FUNCTION "fc_515D_RecData" : VOID
TITLE =TYP GENERATOR  -select received MPI signals-
//version!date    !author !change_segm!change_description
//-------+--------+-------+-----------+-------------------------------
// 1.3   !23.05.00!Kahle  ! ---       ! last valid version
// 1.4   !11.08.00!Kahle  ! 1         ! new rec.data (DB101...124/DBB54)
// 1.5   !17.10.00!Kahle  ! 1         ! Rec.DBB124 change "IN_release"
// 1.6   !20.10.00!Kahle  ! 1         ! Rec dbx108.3 allways from actual config.
// 1.7   !10.11.00!Kahle  ! 2(new)    ! Option: commands supervision system
// 1.8   !11.11.00!Kahle  ! 2         ! Corr. call option
//       !        !       !           ! new rec.data (DB101...124/DBB55)
//       !        !       ! 1         ! Change mask DBX108.2 f_brk_clse
// 1.9   !08.12.00!Kahle  ! 1         ! new rec.date (DB105...124/DBB56)
AUTHOR : Kahle
FAMILY : PMA71
NAME : RecData
VERSION : 1.9


VAR_INPUT
  GENERATOR : BOOL ;
  IN_emergCond : BOOL ;	//Generator =Emergency generator
END_VAR
VAR_TEMP
  total_config11 : DWORD ;	//total configuration config11 (20bit long)
  total_configByte8 : DWORD ;	//total configuration byte8 only (20bit long)
  total_configPreSelect : DWORD ;	//total configuration pre select (20bit long)
  total_configAct : DWORD ;	//total actual configuration (20bit long)
  actCfg_byte8 : WORD ;	//actual configuration for received byte no.8
  cfg_preSelect : WORD ;	//bus configuration for preselection
  mpi_rcv_1 : BYTE ;	//temporary MPI receive Byte1 part1
  mpi_rcv_2 : BYTE ;	//temporary MPI receive Byte3 part2
  mpi_rcv_3 : BYTE ;	//temporary MPI receive Byte3 part3
  mpi_rcv_4 : BYTE ;	//temporary MPI receive Byte3 part4
  mpi_rcv_5 : BYTE ;	//temporary MPI receive Byte8 part1
  mpi_rcv_6 : BYTE ;	//temporary MPI receive Byte8 part2
  fdb_UBLunit : DINT ;	//temporary UBL unit
  equal_UBLunit : BOOL ;	//temporary equal flag UBL
END_VAR
BEGIN
NETWORK
TITLE =Select MPI signals
//Select MPI signals
//load cfg11
//
//1/1 bus configuration
      L     "prm_pma".p_cfg11; // 1/1 bus configuration (cfg11)
      L     "prm_pma".p_tiebrkCfg; //Tie breaker configuration
      CALL "fc_h17_20bitCfg" ;
      T     #total_config11;

//especial byte 8 configuration
      L     "prm_pma".p_cfg11; //configuration in case of EG
      U     #IN_emergCond;
      SPB   EG8B;
      L     "MEM".o51_actCfg; //standard configuration
EG8B: T     #actCfg_byte8;
      L     "prm_pma".p_tiebrkCfg; //Tie breaker configuration
      CALL "fc_h17_20bitCfg" ;
      T     #total_configByte8;

//PreSelect configuration
      L     "prm_pma".p_cfg11;
      L     "prm_pma".p_cfgUness;
      INVI  ;
      UW    ;
      L     2#1111111111111;
      UW    ;
      T     #cfg_preSelect; // 1/1 bus configuration without unessential stations, shore connection1&2,EG
      L     0; //Tie breaker configuration not used!
      CALL "fc_h17_20bitCfg" ;
      T     #total_configPreSelect;

//actual configuration
      L     "MEM".o51_actCfg; //only actual configuration
      L     "prm_pma".p_tiebrkCfg; //Tie breaker configuration
      CALL "fc_h17_20bitCfg" ;
      T     #total_configAct;

//Received commands from Gen 1 -13, EG, TieBrk 1-4, Shore1,2 (I_Gen1_SR ..13SR,I_tie1_SR ..4SR,I_Shr1SR..2SR  D30.0 -D 30.7) <OR>
      CALL "fc_95_fdbHndl" (
           IN_off                   := B#16#0,
           IN_mask                  := B#16#0,//bit0 -7: OR
           IN_release               := #total_config11,
           OUT_fdb                  := DB99.DBB  106);//received MPI commands (byte 0)

//Received commands from Gen 1 -13, EG, TieBrk 1-4, Shore1,2 (D31.0 -D 31.7) <OR>
      CALL "fc_95_fdbHndl" (
           IN_off                   := B#16#1,
           IN_mask                  := B#16#0,//bit0 -7: OR
           IN_release               := #total_config11,
           OUT_fdb                  := #mpi_rcv_1);//received MPI commands (byte 1, without bit1))

//no evaluation I_Gen1_SR ..13SR,I_tie1_SR ..4SR,I_Shr1SR..2SR  D31.1 "simultaneous lock" ->FC117 "simultanLock Handler
//              I_Gen1_SR ..13SR,I_tie1_SR ..4SR,I_Shr1SR..2SR  D31.6 "pre select lock" ->only single signal!
      L     #mpi_rcv_1;
      L     B#16#FD;
      UW    ;
      T     DB99.DBB  107; //received MPI commands (byte 1, bit x.0, x.2 -x.7)

//Received commands from Gen 1 -13, EG, TieBrk 1-4, Shore1,2 (D38.2, D 38.6) <OR>
      CALL "fc_95_fdbHndl" (
           IN_off                   := B#16#8,
           IN_mask                  := B#16#32,//bit1,4-5:AND ; bit0,2,3,6,7: OR
           IN_release               := #total_configByte8,
           OUT_fdb                  := #mpi_rcv_5);//received MPI commands (byte 8)
      L     #mpi_rcv_5;
      L     B#16#F3; //released bit 0,1,4,5,6,7
      UW    ;
      T     #mpi_rcv_5;

//Received commands from Gen 1 -13, EG, TieBrk 1-4, Shore1,2 (D38.2, D 38.6) <OR>
      CALL "fc_95_fdbHndl" (
           IN_off                   := B#16#8,
           IN_mask                  := B#16#32,//bit1,4-5:AND ; bit0,2,3,6,7: OR
           IN_release               := #total_configAct,
           OUT_fdb                  := #mpi_rcv_6);//received MPI commands (byte 8)
      L     #mpi_rcv_6;
      L     B#16#C; //released bit 2,3
      UW    ;
      L     #mpi_rcv_5;
      OW    ;
      T     DB99.DBB  108;

//Received commands from Gen 1 -13, EG, TieBrk 1-4, Shore1,2 (D39.3 -D 39.4) <AND>
      CALL "fc_95_fdbHndl" (
           IN_off                   := B#16#9,
           IN_mask                  := B#16#0,//bit0 -7: OR
           IN_release               := #total_config11,
           OUT_fdb                  := #mpi_rcv_2);//received MPI commands (byte 9)
      L     #mpi_rcv_2;
      L     B#16#18;
      UW    ;
      T     #mpi_rcv_2; //received MPI commands (byte 9, bit3, 4)

//Received commands from Gen 1 -13, EG, TieBrk 1-4, Shore1,2 (D39.2, D39.5 -D 39.7) <OR>
      CALL "fc_95_fdbHndl" (
           IN_off                   := B#16#9,
           IN_mask                  := B#16#0,// bit0 -7: OR
           IN_release               := #total_configAct,
           OUT_fdb                  := #mpi_rcv_3);//received MPI commands (byte 9)
      L     #mpi_rcv_3;
      L     B#16#E4;
      UW    ;
      T     #mpi_rcv_3; //received MPI commands (byte 9, bit2, 5 -7 )

//Received commands from Gen 1 -13, EG, TieBrk 1-4, Shore1,2 (D39.1) <AND>
      CALL "fc_95_fdbHndl" (
           IN_off                   := B#16#9,
           IN_mask                  := B#16#FF,//bit0 -7: AND
           IN_release               := #total_configPreSelect,// 1/1 bus configuration without unessential stations
           OUT_fdb                  := #mpi_rcv_4);//received MPI commands (byte 9)
      L     #mpi_rcv_4;
      L     B#16#2;
      UW    ;
      L     #mpi_rcv_2;
      OW    ;
      L     #mpi_rcv_3;
      OW    ;
      T     DB99.DBB  109; //received MPI commands (byte 9)

//Received commands from Gen 1 -13, EG, TieBrk 1-4, Shore1,2 (I_Gen1_SR ..13SR,I_tie1_SR ..4SR,I_Shr1SR..2SR  D40.0 -D 40.7) <OR>
      CALL "fc_95_fdbHndl" (
           IN_off                   := B#16#A,
           IN_mask                  := B#16#0,//bit0 -7: OR
           IN_release               := #total_configAct,//only actual configuration
           OUT_fdb                  := DB99.DBB  110);//received MPI commands (byte 4)


//Received commands from Gen 1 -13, EG, TieBrk 1-4, Shore1,2 (I_Gen1_SR ..13SR,I_tie1_SR ..4SR,I_Shr1SR..2SR  D41.0 -D 41.7) <OR>
      CALL "fc_95_fdbHndl" (
           IN_off                   := B#16#B,
           IN_mask                  := B#16#0,//bit0 -7: OR
           IN_release               := #total_config11,//1/1 bus configuration
           OUT_fdb                  := DB99.DBB  111);//received MPI commands (byte 5)


//Received commands from Gen 1 -13, EG, TieBrk 1-4, Shore1,2 (I_Gen1_SR ..13SR,I_tie1_SR ..4SR,I_Shr1SR..2SR  D54.0 -D 54.7) <OR>
      CALL "fc_95_fdbHndl" (
           IN_off                   := B#16#18,//24(d)
           IN_mask                  := B#16#0,//bit0 -7: OR
           IN_release               := #total_configAct,//only actual configuration
           OUT_fdb                  := DB99.DBB  124);//received MPI commands (especially up/down commands)

//Received commands from Gen 1 -13, EG, TieBrk 1-4, Shore1,2 (I_Gen1_SR ..13SR,I_tie1_SR ..4SR,I_Shr1SR..2SR  D55.0 -D 55.7) <OR>
      CALL "fc_95_fdbHndl" (
           IN_off                   := B#16#19,//25(d)
           IN_mask                  := B#16#0,//bit0 -7: OR
           IN_release               := #total_configAct,//only actual configuration
           OUT_fdb                  := DB99.DBB  125);//received MPI commands (especially up/down commands)

//Received commands from Gen 1 -13, EG, TieBrk 1-4, Shore1,2 (I_Gen1_SR ..13SR,I_tie1_SR ..4SR,I_Shr1SR..2SR  D56.0 -D 56.7) <OR>
      CALL "fc_95_fdbHndl" (
           IN_off                   := B#16#1A,//26(d)
           IN_mask                  := B#16#0,//bit0 -7: OR
           IN_release               := #total_config11,//only actual configuration
           OUT_fdb                  := DB99.DBB  126);//received MPI commands (especially up/down commands)

NETWORK
TITLE =Option: commands from the supervision system

      CALL "fb_opt_SVcmd" , "Options" ;

END_FUNCTION



FUNCTION "fb_515C_SendData" : VOID
TITLE =Collect the MPI Send signals especial Diesel generator
//version!date    !author !change_segm!change_description
//-------+--------+-------+-----------+-------------------------------
// 1.0   !12.11.99!Kahle  ! ---       ! 1st. valid version
// 1.1   !20.10.00!Kahle  ! 1         ! DBX86.0 f_EG_busbar
//       !        !       ! 1         ! del."I_MMI_SR".i_GenBrkClse->FB40
// 1.2   !26.01.01!Kahle  ! 1         ! corr.signal "on busbar in automatic"
AUTHOR : Kahle
FAMILY : PMA71
NAME : CollData
VERSION : 1.2


VAR_INPUT
  GENERATOR : BOOL ;
  IN_Mde_autoOP : BOOL ;	//mode =automatic from OP
END_VAR
VAR_OUTPUT
  IN_Mde_auto : BOOL ;	//mode =automatic from IMAC
END_VAR
VAR_TEMP
  local : BOOL ;	//mode =local
  semiOP : BOOL ;	//mode =semi OP
  autoOP : BOOL ;	//mode =auto OP
  semi : BOOL ;	//mode =semi
  auto : BOOL ;	//mode =auto
  var5 : BOOL ;
  var6 : BOOL ;
  var7 : BOOL ;
END_VAR
BEGIN
NETWORK
TITLE =Collect the MPI Send signals
// c_genBrkOpn, c_unitLock                            ->FB56 "GenProtect"
//
// c_simlLock                                         ->FC117 "SimultLockHandler"
//
// c_UBL_on, c_shoreMode, c_life, f_UBL_unit,         -> +++Baustelle+++
// UBLminU, f_UBL_on, f_shoreMode, f_actUBL,
// f_actMin, a_UBLunit
//
// c_preSeLock, f_preSeLock, f_busy_Gset              ->FC44 "Order Change", FC43
//"preSeLock"
//
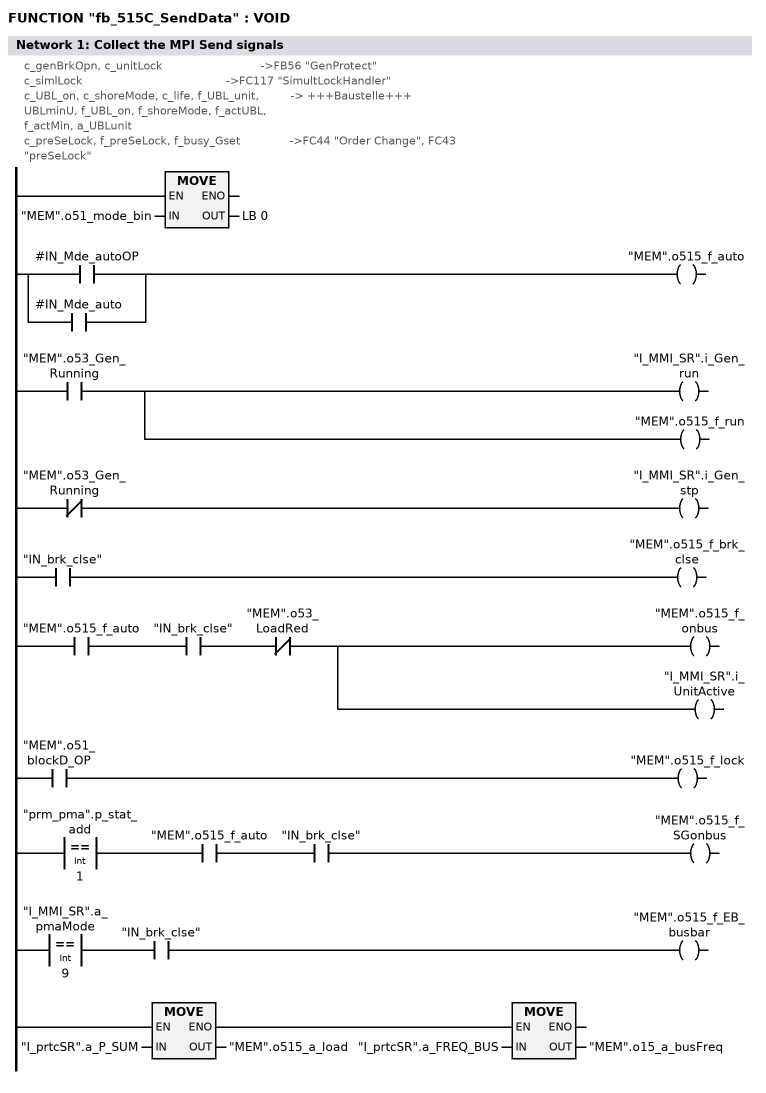
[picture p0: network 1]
      NOP   0;
//c_reqStrt, c_req2Start, c_reqEStart, c_req2EStart  ->FC60,FC61 "DG, SG"
//     O     "MEM".o511_req_Ustrt
//      O     "MEM".o512_req_Ustrt
//      =     "MEM".o515_c_reqStrt

//      O     "MEM".o511_req_Ustrt2
//      =     "MEM".o515_c_req2Strt

//      mode =automatic
      L     "MEM".o51_mode_bin;
      T     LB     0;
      O     #IN_Mde_autoOP;
      O     #IN_Mde_auto;
      =     "MEM".o515_f_auto;

// ready for standby   -->FC60/Segm 34

//Diesel/Shaftgenerator running
      U     "MEM".o53_Gen_Running;
      =     "I_MMI_SR".i_Gen_run;
      =     "MEM".o515_f_run;

//Diesel/Shaftgenerator stopped
      UN    "MEM".o53_Gen_Running;
      =     "I_MMI_SR".i_Gen_stp;

// generator breaker close
      U     "IN_brk_clse";
      =     "MEM".o515_f_brk_clse;

// f_onbus
      U     "MEM".o515_f_auto;
      U     "IN_brk_clse";
      UN    "MEM".o53_LoadRed;
      =     "MEM".o515_f_onbus;
      =     "I_MMI_SR".i_UnitActive;

// generator set blocked
      O     "MEM".o51_blockD_OP;
//                                                    ++++ FB56 "GenProtect" ++++
      =     "MEM".o515_f_lock;

// shaft generator set on busbar
      U(    ;
      L     "prm_pma".p_stat_add;
      L     1;
      ==I   ;
      )     ;
      U     "MEM".o515_f_auto;
      U     "IN_brk_clse";
      =     "MEM".o515_f_SGonbus;

// Diesel is running as emergency diesel on busbar
      U(    ;
      L     "I_MMI_SR".a_pmaMode;
      L     9; //mode =dynamic emergency mode
      ==I   ;
      )     ;
      U     "IN_brk_clse";
      =     "MEM".o515_f_EB_busbar;

// actual active load signal
      L     "I_prtcSR".a_P_SUM;
      T     "MEM".o515_a_load;

// order sequence start/stop                       ->FB44 "Order change"

// actual busbar frequency
      L     "I_prtcSR".a_FREQ_BUS;
      T     "MEM".o15_a_busFreq;

END_FUNCTION




FUNCTION "fc_917_minMax" : VOID
TITLE =Select the highest or lowest value
//The select typ is predefined by the selector switch.
//
//The following selections are possible:
//
//1.: the highest value of In_1, In_2, In_3
//2.: 1st step: the highest value of In_1 and In_2. From this result and In_3 the
//    lowest value.
//3.: the lowest value of In_1, In_2, In_3
//4.: 1st step: the lowest value of In_1 and In_2. From this result and In_3 the
//    highest value.
AUTHOR : Kahle
FAMILY : PMA71
NAME : Minmax
VERSION : 1.0


VAR_INPUT
  Selector : INT ;	//Selection type(1:HHH/2:HHL/3:LLL/4:LLH)
  In_1 : INT ;	//value 1
  In_2 : INT ;	//value 2
  In_3 : INT ;	//value 3
END_VAR
VAR_OUTPUT
  RetVal : INT ;	//return value
END_VAR
BEGIN
NETWORK
TITLE =Select the actual type

      L     #Selector;
      +     -1;
      SPL   fail;
      SPA   HHH;
      SPA   HHL;
      SPA   LLL;
      SPA   LLH;

fail: BEA   ; //in case of a wrong selctor value end of program
NETWORK
TITLE =Type: select the highest value

HHH:  L     #In_1;
      L     #In_2;
      >I    ;
      SPB   C_1; //In_1 > In_2 ?

//In_2 >In_1
      L     #In_2;
      L     #In_3;
      >I    ;
      SPBN  O_1; //In_2 > In_3 ?
      L     #In_2;
O_1:  T     #RetVal;
      BEA   ;

//In_1 >In_2
C_1:  L     #In_3;
      L     #In_1;
      >I    ;
      SPBN  O_1; //In_1 > In_3 ?
      L     #In_3;
      SPA   O_1;

NETWORK
TITLE =

HHL:  L     #In_1;
      L     #In_2;
      >I    ;
      SPB   C_2; //In_1 > In_2 ?

//In_2 >In_1
      L     #In_2;
      L     #In_3;
      <I    ;
      SPBN  O_2; //In_2 < In_3 ?
      L     #In_2;
O_2:  T     #RetVal;
      BEA   ;

//In_1 >In_2
C_2:  L     #In_3;
      L     #In_1;
      <I    ;
      SPBN  O_2; //In_1 < In_3 ?
      L     #In_3;
      SPA   O_2;

NETWORK
TITLE =

LLL:  L     #In_1;
      L     #In_2;
      <I    ;
      SPB   C_3; //In_1 < In_2 ?

//In_1 >In_2
      L     #In_2;
      L     #In_3;
      <I    ;
      SPBN  O_3; //In_2 < In_3 ?
      L     #In_2;
O_3:  T     #RetVal;
      BEA   ;

//In_1 <In_2
C_3:  L     #In_3;
      L     #In_1;
      <I    ;
      SPBN  O_1; //In_1 < In_3 ?
      L     #In_3;
      SPA   O_3;

NETWORK
TITLE =

LLH:  L     #In_1;
      L     #In_2;
      <I    ;
      SPB   C_4; //In_1 < In_2 ?

//In_1 >In_2
      L     #In_2;
      L     #In_3;
      >I    ;
      SPBN  O_4; //In_2 > In_3 ?
      L     #In_2;
O_4:  T     #RetVal;
      BEA   ;

//In_1 <In_2
C_4:  L     #In_3;
      L     #In_1;
      >I    ;
      SPBN  O_4; //In_1 > In_3 ?
      L     #In_3;
      SPA   O_4;

END_FUNCTION

FUNCTION_BLOCK "fb_59_GenSet"
TITLE =Start Unit
//version!date    !author !change_segm!change_description
//-------+--------+-------+-----------+-------------------------------
// 1.1   !28.02.00!Kahle  ! ---       ! last valid version
// 1.2   !15.11.00!Kahle  ! 11        ! no load sharing if semiIMAC (selectable)
// 1.3   !05.01.01!Kahle  ! 11        ! ext.lock L/F-controller
//
//
//
//  FUNKTION:
//  Es werden jeweils nur die Start-Kommandos der jeweiligen aktiven Betriebsart
//akzeptiert.
//
//  Start Kommandos 'Semi-Autom'
//  - Bedienerstart GenSch schliessen
//  Start Kommandos 'Autom'
//  - Bediener Start-Kommando
//  - Bediener Alarmstart-Kommando
//  - Aggregat anfordern
//  - 2. Aggregat anfordern
//  - Aggregat Alarmanforderung
//  - 2. Aggregat Alarmanforderung
//  Freigabe Kriterien
//  - Aggregat nicht am Netz
//  - Diesel verfügbar
//  - kein Notstopp Dieselschutz
//  - GenSch verfügbar
//  - Generatorschutz- u. Synchroniserung verfügbar
//
//  In der Start-Sequenz werden folgende Schritte ausgeführt:
//  - Diesel Start
//  - GenSch schliessen
//  - Lastverteilung
//
//  Bei bereits erfüllten Bedingungen wird der entspechende Schritt übersprungen
//(z.B. bei einem //  von Hand gestartetem Diesel geht die Startsequenz
//automatisch zum nächsten Schritt über).
//  Beim Kommando 'GenSch schliessen' wird der 1.Schritt (Dieselstart)
//übersprungen. Sobald die //  Freigabebedingungen für das Schliessen des GenSch
//erfüllt sind, wird das Kommando akzeptiert.
//  Es werden folgende Schritte ausgeführt:
//  - GenSch schliessen
//  - Lastverteilung
//
//  Beim Auftritt eines Fehlers innerhalb der Startsequenz wird ein neues
//Aggregat angefordert, //  sofern es ein Startkommando 'Automatik' war. Bei
//Startkommando 'Manuell' wird nur eine
// Fehlermeldung abgesetzt.
//  Siemens AG ATD IS3T, Kahle +494028892022, jens.kahle@hbg.siemens.de
//  PMA71
//  = Start Unit
//  Datum aktuelle Version: 09.02.99
//  Version, Datum,   Bearbeiter, geänderte Variablen
//   01.01,  09.02.99,  Kahle   , Ersterstellung
//
//KNOW_HOW_PROTECT
// (If specified, no more changes can be made once the block is generated)
//UNLINKED
// (If specified, the generated block is only available in the PLC load
//  memory)
//READ_ONLY
// (If specified, the generated block cannot be changed in the programmable
//  controller)
AUTHOR : Bauch
FAMILY : PMA71
NAME : StrtUnit
VERSION : 1.3


VAR_INPUT
  in_act_mode : BYTE ;	//Active operation mode
  in_Set_Avail : BOOL ;	//Generator set available for start
  in_PB_Start : BOOL ;	//Command from PB "Start" (in semi from OP/MMI or in local from local PB)
  in_PB_Stop : BOOL ;	//Command from PB "Stop" (in semi from OP/MMI or in local from local PB)
  in_PB_GB_Open : BOOL ;	//Command from PB "GB open" (in semi mode from OP/MMI)
  in_PB_Start_Auto : BOOL ;	//Command from PB "Start Generatorset" incl.Loadsharng (in auto mode)
  in_PB_Stop_Auto : BOOL ;	//Command from PB "Stop Generatorset" incl.Loadsharing (in auto mode)
  in_PB_StopRelease : BOOL ;	//Release for stop command in automatic mode
  in_Standby_Start : BOOL ;	//Standby start command (only in Automatic mode)
  in_Standby_Release : BOOL ;	//Release of standby start (this set as standby set)
  in_Standby_Start2 : BOOL ;	//2nd standby start command (only in Automatic mode)
  in_Standby_Release2 : BOOL ;	//Release of  2nd standby start (this set as standby set)
  in_Stop_Auto : BOOL ;	//Stop command in automatic mode
  in_DI_FB_GenBrk_On : BOOL ;	//Feedback signal Generator breaker is ON
  in_DI_FB_GenBrk_Off : BOOL ;	//Feedback signal Generator breaker is OFF
  in_DI_FireSpeed : BOOL ;	//Ignition speed
  in_GenVolt : BOOL ;	//Generator voltage available (>85%)
  in_lockCtrl : BOOL ;	//lock load/frequency controller
  in_reset : BOOL ;	//Reset failure memory
END_VAR
VAR_OUTPUT
  out_Start_Comm : BOOL ;	//Start command to own set (Pulse)
  out_Stop_Comm : BOOL ;	//Stop command to own set (Pulse)
  out_StopAuto : BOOL ;	//Auto stop command (deloading, GBoff, DG stop)
  out_GenBrk_Off : BOOL ;	//Command "OFF" to generator breaker (Pulse)
  out_LoadBal_On : BOOL ;	//Command "Load balancing ON" (Pulse)
  out_fail_noStopPos : BOOL ;	//In automatic mode no stop permitted
END_VAR
VAR
  stat_Automatic : BOOL ;	//Automatic mode
  stat_Auto_PAux : BOOL ;	//Auxiliary (pulse) flag for automatic mode
  stat_Auto_Pulse : BOOL ;	//Automatic mode (pulse)
  stat_Start_Auto_PAux : BOOL ;	//Auxiliary (pulse) flag for start in auto mode
  stat_Start_Semi_PAux : BOOL ;	//Auxiliary (pulse) flag for start in semi auto mode
  stat_Start_Auto_PB : BOOL ;	//Auxiliary (pulse) flag for PB "Start" in auto mode
  stat_Stop_Auto_PAux : BOOL ;	//Auxiliary (pulse) flag for stop in auto mode
  stat_Stop_Semi_PAux : BOOL ;	//Auxiliary (pulse) flag for stop in semi auto mode
  stat_Stop_Auto_PB : BOOL ;	//Auxiliary (pulse) flag for PB "Stop" in auto mode
  stat_GBOn_Semi_PAux : BOOL ;	//Auxiliary (pulse) flag for gen. breaker closing in semi auto mode
  stat_BrkOff_Semi_PAux : BOOL ;	//Auxiliary (pulse) flag for generator breaker Off command in semi auto mode
  stat_LoadBal_Auto_PAux : BOOL ;	//Auxiliary (pulse) flag for "Load balance mode" On command in auto mode
  stat_LoadBal_Semi_PAux : BOOL ;	//Auxiliary (pulse) flag for "Load balance mode" On command in semi auto mode
  stat_StpNoPos : BOOL ;	//Stop gen.set not possible
END_VAR
VAR_TEMP
  temp_OM_Local : BOOL ;	//Active operation mode: Local
  temp_OM_Semi_OP : BOOL ;	//Active operation mode: Semi automatic OP
  temp_OM_Auto_OP : BOOL ;	//Active operation mode: Auto OP
  temp_OM_Semi_MMI : BOOL ;	//Active operation mode: Semi automatic MMI
  temp_OM_Auto_MMI : BOOL ;	//Active operation mode: Auto MMI
  temp_Reserve_005 : BOOL ;	//Reserved (Transfer Byte --> Bit)
  temp_Reserve_006 : BOOL ;	//Reserved (Transfer Byte --> Bit)
  temp_Reserve_007 : BOOL ;	//Reserved (Transfer Byte --> Bit)
  temp_Auto : BOOL ;	//Active operation mode: Auto
  temp_Semi : BOOL ;	//Active operation mode: Semi automatic
  temp_ScratchFlag : BOOL ;	//Scratch flag
  in_Genop_noFail : BOOL ;	//	no failure at Genop
  in_loadsharing_ok : BOOL ;	//	feedback loadsharing in normal range
  temp_PB_autoStop : BOOL ;	//Stop generator set in automatic mode
  temp_preCondPBstp : BOOL ;	//Preconditions for stop via pushbutton
END_VAR
BEGIN
NETWORK
TITLE =Active operation mode (Transfer Byte --> Bit)
//This transfer function is relaying on the relative addresses of the "temp"
//variables "temp_OM_Local" ... "temp_OM_Auto" in the area from 0.0 ... 0.7.
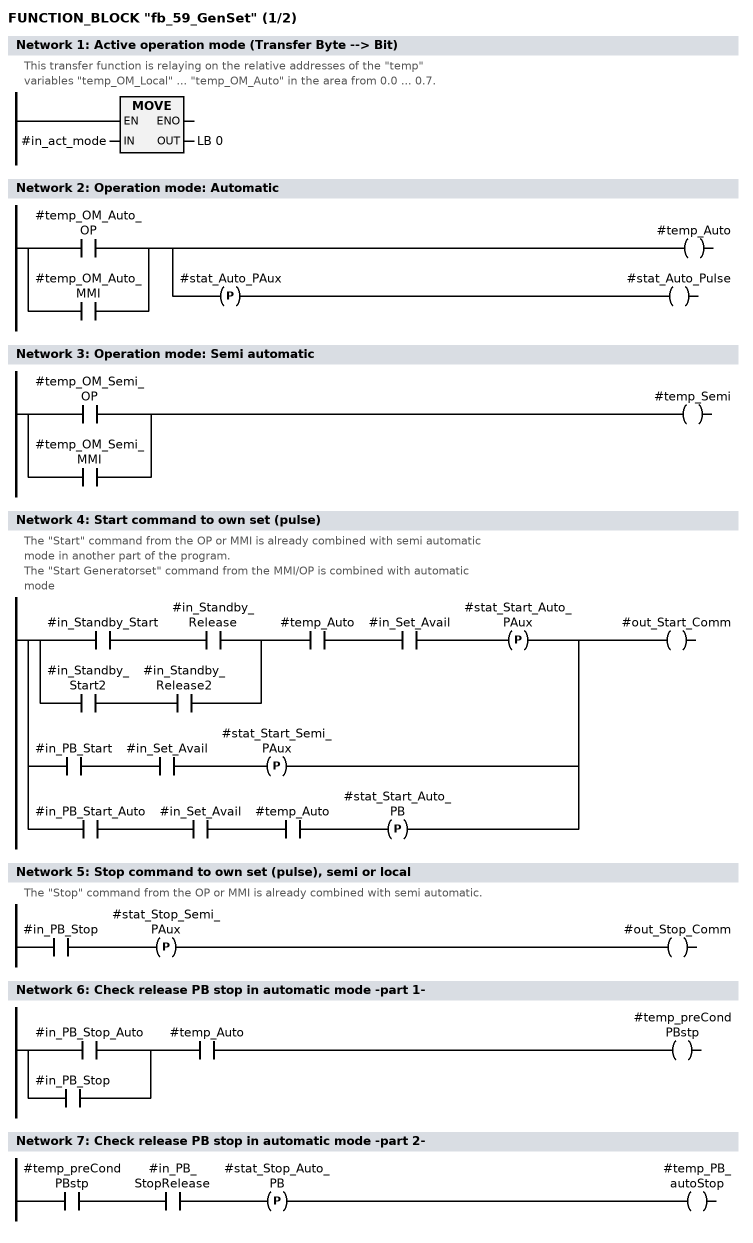
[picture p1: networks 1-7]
      L     #in_act_mode;
      T     LB     0;
NETWORK
TITLE =Operation mode: Automatic

      O     #temp_OM_Auto_OP;
      O     #temp_OM_Auto_MMI;
      =     L      2.0;
      U     L      2.0;
      BLD   102;
      =     #temp_Auto;
      U     L      2.0;
      FP    #stat_Auto_PAux;
      =     #stat_Auto_Pulse;
NETWORK
TITLE =Operation mode: Semi automatic

      O     #temp_OM_Semi_OP;
      O     #temp_OM_Semi_MMI;
      =     #temp_Semi;
NETWORK
TITLE =Start command to own set (pulse)
//The "Start" command from the OP or MMI is already combined with semi automatic
//mode in another part of the program.
//
//The "Start Generatorset" command from the MMI/OP is combined with automatic
//mode
      U(    ;
      U     #in_Standby_Start;
      U     #in_Standby_Release;
      O     ;
      U     #in_Standby_Start2;
      U     #in_Standby_Release2;
      )     ;
      U     #temp_Auto;
      U     #in_Set_Avail;
      FP    #stat_Start_Auto_PAux;
      O(    ;
      U     #in_PB_Start;
      U     #in_Set_Avail;
      FP    #stat_Start_Semi_PAux;
      )     ;
      O(    ;
      U     #in_PB_Start_Auto;
      U     #in_Set_Avail;
      U     #temp_Auto;
      FP    #stat_Start_Auto_PB;
      )     ;
      =     #out_Start_Comm;
NETWORK
TITLE =Stop command to own set (pulse), semi or local
//The "Stop" command from the OP or MMI is already combined with semi automatic.
//
//
      U     #in_PB_Stop;
      FP    #stat_Stop_Semi_PAux;
      =     #out_Stop_Comm;
NETWORK
TITLE =Check release PB stop in automatic mode -part 1-

      U(    ;
      O     #in_PB_Stop_Auto;
      O     #in_PB_Stop;
      )     ;
      U     #temp_Auto;
      =     #temp_preCondPBstp;
NETWORK
TITLE =Check release PB stop in automatic mode -part 2-

      U     #temp_preCondPBstp;
      U     #in_PB_StopRelease;
      FP    #stat_Stop_Auto_PB;
      =     #temp_PB_autoStop;
NETWORK
TITLE =Check release PB stop in automatic mode -part 2-

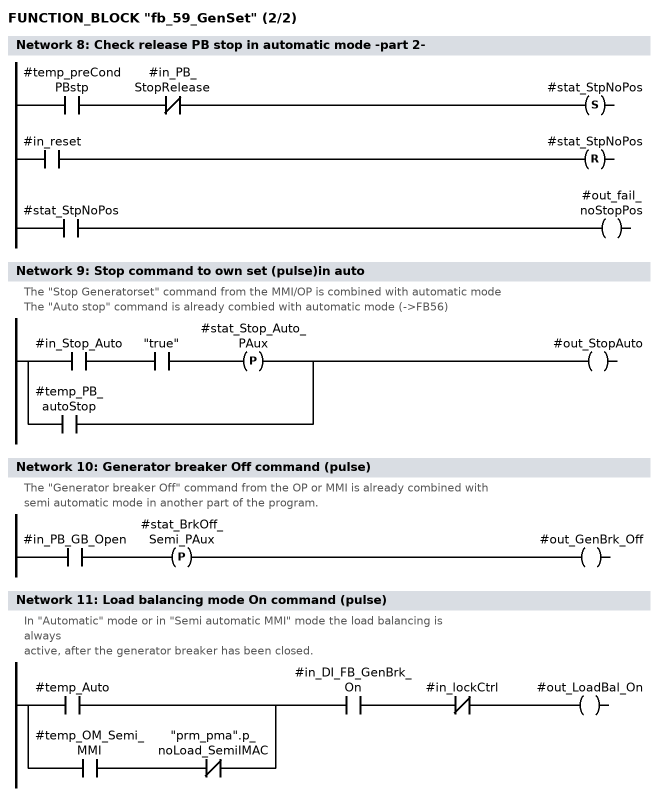
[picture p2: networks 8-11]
      U     #temp_preCondPBstp;
      UN    #in_PB_StopRelease;
      S     #stat_StpNoPos;
      U     #in_reset;
      R     #stat_StpNoPos;
      U     #stat_StpNoPos;
      =     #out_fail_noStopPos;
NETWORK
TITLE =Stop command to own set (pulse)in auto
//The "Stop Generatorset" command from the MMI/OP is combined with automatic mode
//
//The "Auto stop" command is already combied with automatic mode (->FB56)
      U     #in_Stop_Auto;
      U     "true";
      FP    #stat_Stop_Auto_PAux;
      O     #temp_PB_autoStop;
      =     #out_StopAuto;
NETWORK
TITLE =Generator breaker Off command (pulse)
//The "Generator breaker Off" command from the OP or MMI is already combined with
//semi automatic mode in another part of the program.
      U     #in_PB_GB_Open;
      FP    #stat_BrkOff_Semi_PAux;
      =     #out_GenBrk_Off;
NETWORK
TITLE =Load balancing mode On command (pulse)
//In "Automatic" mode or in "Semi automatic MMI" mode the load balancing is
//always
//active, after the generator breaker has been closed.
      U(    ;
      O     #temp_Auto;
      O     ;
      U     #temp_OM_Semi_MMI;
      UN    "prm_pma".p_noLoad_SemiIMAC;
      )     ;
      U     #in_DI_FB_GenBrk_On;
      UN    #in_lockCtrl;
      =     #out_LoadBal_On;
END_FUNCTION_BLOCK




DATA_BLOCK "startU"
TITLE =
VERSION : 0.0

"fb_59_GenSet"
BEGIN
   in_act_mode := B#16#0;
   in_Set_Avail := FALSE;
   in_PB_Start := FALSE;
   in_PB_Stop := FALSE;
   in_PB_GB_Open := FALSE;
   in_PB_Start_Auto := FALSE;
   in_PB_Stop_Auto := FALSE;
   in_PB_StopRelease := FALSE;
   in_Standby_Start := FALSE;
   in_Standby_Release := FALSE;
   in_Standby_Start2 := FALSE;
   in_Standby_Release2 := FALSE;
   in_Stop_Auto := FALSE;
   in_DI_FB_GenBrk_On := FALSE;
   in_DI_FB_GenBrk_Off := FALSE;
   in_DI_FireSpeed := FALSE;
   in_GenVolt := FALSE;
   in_reset := FALSE;
   out_Start_Comm := FALSE;
   out_Stop_Comm := FALSE;
   out_StopAuto := FALSE;
   out_GenBrk_Off := FALSE;
   out_LoadBal_On := FALSE;
   out_fail_noStopPos := FALSE;
   stat_Automatic := FALSE;
   stat_Auto_PAux := FALSE;
   stat_Auto_Pulse := FALSE;
   stat_Start_Auto_PAux := FALSE;
   stat_Start_Semi_PAux := FALSE;
   stat_Start_Auto_PB := FALSE;
   stat_Stop_Auto_PAux := FALSE;
   stat_Stop_Semi_PAux := FALSE;
   stat_Stop_Auto_PB := FALSE;
   stat_GBOn_Semi_PAux := FALSE;
   stat_BrkOff_Semi_PAux := FALSE;
   stat_LoadBal_Auto_PAux := FALSE;
   stat_LoadBal_Semi_PAux := FALSE;
   stat_StpNoPos := FALSE;
END_DATA_BLOCK





FUNCTION "fc_opt1_AO" : VOID
TITLE =Option: Analog output channels
//- active load as 4 -20mA signal
AUTHOR : Kahle
FAMILY : PMA71
NAME : Opt1_AO
VERSION : 1.0


VAR_TEMP
  temp_GEN_P_SUM : INT ;	//Generator active load (in 100.00% of nominal value)
END_VAR
BEGIN
END_FUNCTION

FUNCTION "fc_511A_Prtct_Limit" : VOID
TITLE =Limit monitoring with time delay (one limit, one value)
//version!date    !author !change_segm!change_description
//-------+--------+-------+-----------+-------------------------------
// 1.0   !10.11.99!Bauch  ! ---       ! 1st vaild version
// 1.1   !10.01.01!Kahle  ! 3,4(del)  ! Corr. time delay set 'limit exceeded'
//
//
//
//This FC compares the actual value (in %) with a limit (in %) and creates an
//output signal without and with time delay.
//
//This monitoring function can be adapted with the following parameters:
//
//- Limit (in 0.01% of nominal value)
//- Hysteresis (in 0.01%, percent points)
//- Time delay (formate: S5TIME)
//- Low limit or high limit evaluation (0=Low limit, 1=High limit)
//- Release of the function: 0=Function not released (Output="0"),
//                           1=Function released (Normal function)
//
//Example: Limit 85.00%, hysteresis 2.00%, MinMax="1":
//         Output "1" with actual value > 85%
//         Output "0" with actual value < 83%
AUTHOR : Bauch
FAMILY : PMA71
NAME : Limit
VERSION : 1.1


VAR_INPUT
  in_Actual : INT ;	//Actual value (in 0.01%)
  in_Limit : INT ;	//Limiting value (in 0.01%)
  in_Hysteresis : INT ;	//Hysteresis (in 0.01%)
  in_Delay : S5TIME ;	//Delay time (S5TIME)
  in_Timer : TIMER ;	//Timer No. for delay time
  in_MinMax : BOOL ;	//Selection min./max. (0=Min.=Low limit evaluation, 1=Max.=High limit evaluation)
  in_Prtct_Release : BOOL ;	//Release of limit monitoring (0=No monitoring, Output=Off)
END_VAR
VAR_OUTPUT
  out_Limit_Exc_Undel : BOOL ;	//Out-of-limit condition, undelayed
  out_Limit_Exc_Del : BOOL ;	//Out-of-limit condition, delayed
END_VAR
VAR_IN_OUT
  inout_Limit : BOOL ;	//Limit exceeded
END_VAR
VAR_TEMP
  temp_LimLowHyst : INT ;	//Low limit with hysteresis
  temp_LimHighHyst : INT ;	//High limit with hysteresis
END_VAR
BEGIN
NETWORK
TITLE =Low limit with hysteresis

      U     "true";
      SPBNB _001;
      L     #in_Limit;
      L     #in_Hysteresis;
      +I    ;
      T     #temp_LimLowHyst;
_001: NOP   0;
NETWORK
TITLE =High limit with hysteresis

      U     "true";
      SPBNB _002;
      L     #in_Limit;
      L     #in_Hysteresis;
      -I    ;
      T     #temp_LimHighHyst;
_002: NOP   0;
NETWORK
TITLE =Low limit exceeded

      U(    ;
      U(    ;
      L     #in_Actual;
      L     #in_Limit;
      <I    ;
      )     ;
      UN    #in_MinMax;
      O     ;
      U(    ;
      L     #in_Actual;
      L     #in_Limit;
      >I    ;
      )     ;
      U     #in_MinMax;
      )     ;
      U     #in_Prtct_Release;
      =     L      4.0;
      U(    ;
      U     L      4.0;
      L     #in_Delay;
      SE    #in_Timer;
      NOP   0;
      NOP   0;
      NOP   0;
      U     #in_Timer;
      )     ;
      S     #inout_Limit;
      U(    ;
      U(    ;
      L     #in_Actual;
      L     #temp_LimLowHyst;
      >I    ;
      )     ;
      UN    #in_MinMax;
      O     ;
      U(    ;
      L     #in_Actual;
      L     #temp_LimHighHyst;
      <I    ;
      )     ;
      U     #in_MinMax;
      ON    #in_Prtct_Release;
      )     ;
      R     #inout_Limit;
      U     #inout_Limit;
      =     #out_Limit_Exc_Del;
      U     L      4.0;
      BLD   102;
      =     #out_Limit_Exc_Undel;
END_FUNCTION


FUNCTION_BLOCK "fb_511_GenProtect"
TITLE =Monitoring and protection (generator, mains, etc.)
//version!date    !author !change_segm!change_description
//-------+--------+-------+-----------+-------------------------------
// 1.3   !28.02.00!Bauch  ! ---       ! last vaild version
// 1.4   !31.07.00!Bauch  ! 18,50     ! select the max.voltage
//       !        !       !58,67,68,69! function block if EG mode
//       !        !       ! 71        ! Ind'short circuit'
//       !        !       ! 83        ! Ind'underload SD'
//       !        !       ! 84        ! corr.pointer
// 1.5   !05.10.00!Kahle  ! 11        ! min.limit current monit.adjust.
// 1.6   !05.12.00!Bauch  ! 25        ! Blocking by short-circuit of other gen.
//       !        !       ! 15        ! New variable "temp_Volt_Blackout"
// 1.7   !11.10.01!Kahle  ! 67,68     ! Corr. blocking
// 1.8   !23.01.01!Kahle  ! 80        ! Underload shutdown possible (Calculation
//       !        !       !           ! is made for the whole network)
// 1.9   !07.03.01!Kahle  !27,55,56,57! blocked of uness.consumer trip if select
//       !        !       ! 72,73(new)! Ind 'overcurrent', Ind 'overload'
// 1.10  !12.03.01!Kahle  ! 26 new    ! Indication "diff.protection warning"
//       !        !       ! 40 new    ! load limit 7,especially EG
//       !        !       ! 61        ! add.signal'stat_Trip_TempOverc'
//       !        !       ! 71        ! Latch 'overcurrent + overtemp'
// 1.11  !16.11.01!Kahle  ! 4         ! EG mode active in automatic only
//       !        !       ! 28        ! del.block uness.consumer GENOP
//       !        !       !           ! ##### At GENOP Version 1.7 ############
//       !        !       ! 54        ! Genop71_GW3 exceeded ->Stdby Start only
//       !        !       !           ! #######################################
//       !        !       ! 60        ! I7& OvTemp ->Brk off in normMode also
//
//This FB carries out the following monitoring functions:
//- Blackout detection
//- Monitoring of the mains (busbar): Under-/overfrequency, under-/overvoltage
//- Generator protection: Overcurrent, overload
//- Underload detection with different limits for 2, 3, 4 generators in load
//  sharing mode
//- Plausibility check of generator currents
//- Monitoring of generator voltage, digital signal for normal generator
//  functions, after generator voltage is available
//
//The following signals are given:
//- Start command for standby generator
//- Trip command for unessential consumers (in 3 groups)
//- Trip command for generator breaker
//- Blackout
//- Start command for 2. standby generator in case of blackout (if selected)
//- Generator voltage available (standard: gen. voltage >85%, limit adjustable)
//- Underload shutdown
//- Indication signals (Standby start, uness. consumers 1, 2, 3, generator breaker
//
//  Off by overcurrent, reverse power, underfrequency 1, 2, 3, overfrequency,
//  undervoltage 1, 2, 3, overvoltage, failure busbar monitoring, failure
//  current measuring, underload indication)
//The indication for "Trip of unessential consumers" is not coming directly from
//this FB, as there are also other reasons for trip (for example shut down of the
//diesel engine).
AUTHOR : Bauch
FAMILY : PMA71
NAME : GenProt
VERSION : 1.11


VAR_INPUT
  in_GEN_I_L1 : INT ;	//Actual value generator current phase L1 (in 0.01% of nominal value)
  in_GEN_I_L2 : INT ;	//Actual value generator current phase L2 (in 0.01% of nominal value)
  in_GEN_I_L3 : INT ;	//Actual value generator current phase L3 (in 0.01% of nominal value)
  in_GEN_P_SUM : INT ;	//Actual value generator load L1/L2/L3 (in 0.01% of nominal value)
  in_BUS_f : INT ;	//Actual value mains (busbar) frequency (in 0.01% of nominal value)
  in_BUS_U_L1L2 : INT ;	//Actual value mains (busbar) voltage phase L1/L2 (in 0.01% of nominal value)
  in_BUS_U_L2L3 : INT ;	//Actual value mains (busbar) voltage phase L2/L3 (in 0.01% of nominal value)
  in_BUS_U_L3L1 : INT ;	//Actual value mains (busbar) voltage phase L3/L1 (in 0.01% of nominal value)
  in_GEN_U_L1L2 : INT ;	//Actual value generator voltage phase L1/L2 (in 0.01% of nominal value)
  in_GEN_U_L2L3 : INT ;	//Actual value generator voltage phase L2/L3 (in 0.01% of nominal value)
  in_GEN_U_L3L1 : INT ;	//Actual value generator voltage phase L3/L1 (in 0.01% of nominal value)
  in_Nmb_Generator : INT ;	//Number of other generators taking part in loadsharing (for underload shutdown)
  in_act_mode : BYTE ;	//Active operation mode
  in_EG_Set : BOOL ;	//Generator set is an Emergency generator
  in_EG_Harbour_Mode : BOOL ;	//Emergency generator is in "Harbour mode"
  in_EG_PowerFb_Mode : BOOL ;	//Emergency generator is in "Power feedback mode"
  in_DI_Blackout : BOOL ;	//Blackout, from DI
  in_DI_BusbarVolt : BOOL ;	//Busbar voltage present (no blackout), from DI
  in_DI_FireSpeedRelGenBrk : BOOL ;	//Ignition speed (DG) / Release of generator breaker (SG)
  in_DI_FB_GenBrk_On : BOOL ;	//Feedback signal generator breaker is ON
  in_DI_Wind_Overtemp : BOOL ;	//Generator windings overtemperature
  in_DiffProt_warn : BOOL ;	//Differentail protection device: Warning
  in_DiffProt_Trip : BOOL ;	//Differential protection device, tripping
  in_Overc_ShortC_extern : BOOL ;	//Signal "Overcurrent,Short circuit" from external device (gen. breaker built-in)
  in_GENOP_ShortCircuit : BOOL ;	//Signal "Short circuit" from GENOP71
  in_GENOP_OvCurr_trip : BOOL ;	//Signal "Generator breaker trip by overcurrent" from GENOP71
  in_GENOP_ReversePower : BOOL ;	//Signal "Generator breaker trip by reverse power" from GENOP71
  in_GENOP_OvCurr_1_dly_1 : BOOL ;	//"Trip uness.consumer 1" because of limit 1 & delay time exceeded (GENOP71)
  in_GENOP_OvCurr_1_dly_2 : BOOL ;	//"Trip uness.consumer 1" because of limit 2 & delay time exceeded (GENOP71)
  in_GENOP_OvCurr_1_dly_3 : BOOL ;	//"Trip uness.consumer 1" because of limit 3 & delay time exceeded (GENOP71)
  in_GENOP_OvCurr_3 : BOOL ;	//"Trip uness.consumers 1 -3" because of limit 3 exceeded (from GENOP71)
  in_Rel_UnderlShd : BOOL ;	//Release of underload shutdown
  in_UnderShd_pos : BOOL ;	//Underload shutdown posible
  in_ShortCirc_OtherGen : BOOL ;	//Short circuit signal from other generator set
  in_Reset : BOOL ;	//Reset
  in_p_uncond_reset : BOOL ;	//Reset without conditions possible
END_VAR
VAR_OUTPUT
  out_Blackout : BOOL ;	//Blackout
  out_BusVolt_avail : BOOL ;	//Busbar voltage available (standard: >85% of nominal value)
  out_GenVolt_avail : BOOL ;	//Generator voltage available (standard: >85% of nominal value; adjustable)
  out_StandbyStart : BOOL ;	//Request for standby generator start
  out_Uness1_Off : BOOL ;	//Trip command for unessential consumers 1
  out_Uness2_Off : BOOL ;	//Trip command for unessential consumers 2
  out_Uness3_Off : BOOL ;	//Trip command for unessential consumers 3
  out_GenBrk_Off : BOOL ;	//Trip command for generator breaker
  out_ShortCirc_OtherGen : BOOL ;	//Signal "Short circuit" to other generator sets (blocking of gen. sets)
  out_VoltContr_Off : BOOL ;	//Off command to the voltage controller (deexitation of the generator)
  out_UndelayStop : BOOL ;	//Undelayed stop command
  out_Blocking : BOOL ;	//Blocking of generator set
  out_ChOver_Semi : BOOL ;	//Forced change over from automatic to semi automatic mode
  out_ChOver_Blackout : BOOL ;	//Change over to new started standby set via blackout (no synchronizing)
  out_Underload_Limit : BOOL ;	//Load < underload limit (for shutdown from MMI)
  out_Underload_Shd : BOOL ;	//Shutdown by underload
  out_Fail_Busbar : BOOL ;	//Indication "Busbar monitoring failure"
  out_Fail_Current : BOOL ;	//Indication "Current monitoring failure"
  out_Fail_Overcurr : BOOL ;	//Indication "Generator breaker trip by overcurrent"
  out_Fail_shortCirc : BOOL ;	//Indication "Short circuit"
  out_Fail_RevPower : BOOL ;	//Indication "Reverse power trip"
  out_Fail_overcurrent : BOOL ;	//Indication "overcurrent"
  out_Fail_overload : BOOL ;	//Indication "overload"
  out_Fail_Underfrequ1 : BOOL ;	//Indication "Underfrequency 1"
  out_Fail_Underfrequ2 : BOOL ;	//Indication "Underfrequency 2"
  out_Fail_Underfrequ3 : BOOL ;	//Indication "Underfrequency 3"
  out_Fail_Overfrequ : BOOL ;	//Indication "Overfrequency"
  out_Fail_Undervolt1 : BOOL ;	//Indication "Undervoltage 1" (limit 1)
  out_Fail_Undervolt2 : BOOL ;	//Indication "Undervoltage 2" (U<85%)
  out_Fail_Overvolt1 : BOOL ;	//Indication "Overvoltage" (limit 3)
  out_Fail_Overvolt2 : BOOL ;	//Indication "Overvoltage 2" (limit 4)
  out_Fail_ShortCirc_Other : BOOL ;	//Indication "Blocking by short circuit from other gen. set"
  out_Fail_DiffProt_Warn : BOOL ;	//Indication "Differential protection device: warning"
  out_Fail_DiffProt_Trip : BOOL ;	//Indication "Differential protection device, tripping"
  out_Fail_Wind_Overtemp : BOOL ;	//Indication "Generator windings overtemperature"
  out_Fail_Underload : BOOL ;	//Indication "Underload"
  out_Fail_Underl_SD : BOOL ;	//Indication "Underload shutdown, activation"
  out_Spare_1 : BOOL ;	//Spare output 1
  out_Spare_2 : BOOL ;	//Spare output 2
  out_PrtcEG_sign : DWORD ;	//Protection signals especially for emergency diesel
END_VAR
VAR
  stat_GEN_I_Min : INT ;	//Generator current, lowest value (phase L1, L2, L3)
  stat_GEN_I_Max : INT ;	//Generator current, highest value (phase L1, L2, L3)
  stat_GEN_I_Mean : INT ;	//Generator current, mean value (phase L1, L2, L3)
  stat_BUS_U_Min : INT ;	//Mains (busbar) voltage, lowest value (phase L1/L2, L2/L3, L3/L1)
  stat_BUS_U_Max : INT ;	//Mains (busbar) voltage, highest value (phase L1/L2, L2/L3, L3/L1)
  stat_GEN_U_Min : INT ;	//Generator voltage, lowest value (phase L1/L2, L2/L3, L3/L1)
  stat_GEN_U_Max : INT ;	//Generator voltage, highest value (phase L1/L2, L2/L3, L3/L1)
  stat_Limit_I1 : BOOL ;	//Generator current, limit 1 exceeded (Standby start)
  stat_Limit_I2 : BOOL ;	//Generator current, limit 2 exceeded (Standby start)
  stat_Limit_I3 : BOOL ;	//Generator current, limit 3 exceeded (Uness. consumers 1)
  stat_Limit_I4 : BOOL ;	//Generator current, limit 4 exceeded (Uness. consumers 2)
  stat_Limit_I5 : BOOL ;	//Generator current, limit 5 exceeded (Uness. consumers 3)
  stat_Limit_I6 : BOOL ;	//Generator current, limit 6 exceeded (Standby start, Uness. consumers 1-3)
  stat_Limit_I7 : BOOL ;	//Generator current, limit 7 exceeded (Generator breaker Off)
  stat_Limit_P1 : BOOL ;	//Generator load, limit 1 exceeded (Standby start)
  stat_Limit_P2 : BOOL ;	//Generator load, limit 2 exceeded (Standby start)
  stat_Limit_P3 : BOOL ;	//Generator load, limit 3 exceeded (Uness. consumers 1)
  stat_Limit_P4 : BOOL ;	//Generator load, limit 4 exceeded (Uness. consumers 2)
  stat_Limit_P5 : BOOL ;	//Generator load, limit 5 exceeded (Uness. consumers 3)
  stat_Limit_P6 : BOOL ;	//Generator load, limit 6 exceeded (Standby start, Uness. consumers 1, 2, 3)
  stat_Limit_P7 : BOOL ;	//Generator load, limit 7 exceeded (Gen. breaker Off)
  stat_Limit_f1 : BOOL ;	//Busbar frequency, limit 1 exceeded (Standby start)
  stat_Limit_f2 : BOOL ;	//Busbar frequency, limit 2 exceeded (Standby start)
  stat_Limit_f3 : BOOL ;	//Busbar frequency, limit 3 exceeded (Uness. consumers 1)
  stat_Limit_f4 : BOOL ;	//Busbar frequency, limit 4 exceeded (Uness. consumers 2)
  stat_Limit_f5 : BOOL ;	//Busbar frequency, limit 5 exceeded (Uness. consumers 3)
  stat_Limit_f6 : BOOL ;	//Busbar frequency, limit 6 exceeded (Standby start, Uness. consumers 1, 2, 3)
  stat_Limit_f7 : BOOL ;	//Busbar frequency, limit 7 exceeded (Gen. breaker Off)
  stat_Limit_f8 : BOOL ;	//Busbar frequency, limit 8 exceeded (Overfrequency alarm)
  stat_Limit_U1 : BOOL ;	//Busbar voltage, limit 1 exceeded (Undervoltage, standby start)
  stat_Limit_U2 : BOOL ;	//Busbar voltage, limit 2 exceeded (Undervoltage, Gen. breaker Off)
  stat_Limit_U3 : BOOL ;	//Busbar voltage, limit 3 exceeded (Overvoltage, standby start)
  stat_Limit_U4 : BOOL ;	//Busbar voltage, limit 4 exceeded (Overvoltage, blocking of voltage controller)
  stat_Limit_P7_undel : BOOL ;	//Generator load, limit 7 exceeded, undelayed (Gen. breaker Off)
  stat_Limit_P7_Warn : BOOL ;	//Generator load, limit 7 exceeded, protection warning
  stat_ShortCircuit : BOOL ;	//Latch for signal "Short circuit"
  stat_Wind_Overtemp : BOOL ;	//Generator winding overtemperature, time delayed
  stat_Standby_ProtWarn : BOOL ;	//Request for standby start (EG: Protection warning)
  stat_Uness1_TransfLBrk : BOOL ;	//Trip command for unessential consumers 1 (EG: Trip of transfer line CB)
  stat_ShC_OtherSet_Aux : BOOL ;	//Auxiliary flag for signal "Short circuit from other set"
  stat_ShC_OtherSet_Pulse : BOOL ;	//Pulse signal "Short circuit from other generator set"
  stat_ShC_OtherSet1 : BOOL ;	//Latch for signal "1. short circuit from other generator set"
  stat_ShC_OtherSet2 : BOOL ;	//Latch for signal "2. short circuit from other generator set"
  stat_ShC_OtherSet_Reset : BOOL ;	//Automatic reset of short circuit from other generator set (after a delay time)
  stat_Block_ShC_OtherSet : BOOL ;	//Blocking of generator set by short circuit signal from other gen. set
  stat_DiffProt_Trip : BOOL ;	//Latch for signal "Diff. protection tripping"
  stat_Trip_Overcurrent : BOOL ;	//Latch for signal "Generator breaker trip by overcurrent"
  stat_Trip_RevPower : BOOL ;	//Latch for signal "Generator breaker trip by reverse power"
  stat_Trip_Underfrequ : BOOL ;	//Latch for signal "Generator breaker trip by underfrequency"
  stat_Trip_Undervoltage : BOOL ;	//Latch for signal "Generator breaker trip by undervoltage"
  stat_Uness2_Uness1 : BOOL ;	//Trip command for unessential consumers 2 (EG: Trip of uness. cons. 1)
  stat_Uness3_Uness2 : BOOL ;	//Trip command for unessential consumers 3 (EG: Trip of uness. cons. 3)
  stat_GenRunning : BOOL ;	//Diesel/Shaft generator running (Ignition speed/Release gen. breaker, or U>85%)
  stat_Harb_Feedb_Mode : BOOL ;	//Emergency generator in harbour mode or in power feedback mode
  stat_GENOP_StandbySt : BOOL ;	//Start command for standby generator, caused by GENOP71
  stat_FC56_Limit_01 : BOOL ;	//Memory for FC56, Limit No. 01 (Current, limit 1)
  stat_FC56_Limit_02 : BOOL ;	//Memory for FC56, Limit No. 02 (Current, limit 2)
  stat_FC56_Limit_03 : BOOL ;	//Memory for FC56, Limit No. 03 (Current, limit 3)
  stat_FC56_Limit_04 : BOOL ;	//Memory for FC56, Limit No. 04 (Current, limit 4)
  stat_FC56_Limit_05 : BOOL ;	//Memory for FC56, Limit No. 05 (Current, limit 5)
  stat_FC56_Limit_06 : BOOL ;	//Memory for FC56, Limit No. 06 (Current, limit 6)
  stat_FC56_Limit_07 : BOOL ;	//Memory for FC56, Limit No. 07 (Current, limit 7)
  stat_FC56_Limit_08 : BOOL ;	//Memory for FC56, Limit No. 08 (Load, limit 1)
  stat_FC56_Limit_09 : BOOL ;	//Memory for FC56, Limit No. 09 (Load, limit 2)
  stat_FC56_Limit_10 : BOOL ;	//Memory for FC56, Limit No. 10 (Load, limit 3)
  stat_FC56_Limit_11 : BOOL ;	//Memory for FC56, Limit No. 11 (Load, limit 4)
  stat_FC56_Limit_12 : BOOL ;	//Memory for FC56, Limit No. 12 (Load, limit 5)
  stat_FC56_Limit_13 : BOOL ;	//Memory for FC56, Limit No. 13 (Load, limit 6)
  stat_FC56_Limit_131 : BOOL ;	//Memory for FC56, Limit No. 14 (Load, limit 7)
  stat_FC56_Limit_14 : BOOL ;	//Memory for FC56, Limit No. 14 (Frequency, limit 1)
  stat_FC56_Limit_15 : BOOL ;	//Memory for FC56, Limit No. 15 (Frequency, limit 2)
  stat_FC56_Limit_16 : BOOL ;	//Memory for FC56, Limit No. 16 (Frequency, limit 3)
  stat_FC56_Limit_17 : BOOL ;	//Memory for FC56, Limit No. 17 (Frequency, limit 4)
  stat_FC56_Limit_18 : BOOL ;	//Memory for FC56, Limit No. 18 (Frequency, limit 5)
  stat_FC56_Limit_19 : BOOL ;	//Memory for FC56, Limit No. 19 (Frequency, limit 6)
  stat_FC56_Limit_20 : BOOL ;	//Memory for FC56, Limit No. 20 (Frequency, limit 7)
  stat_FC56_Limit_21 : BOOL ;	//Memory for FC56, Limit No. 21 (Frequency, limit 8)
  stat_FC56_Limit_22 : BOOL ;	//Memory for FC56, Limit No. 22 (Voltage, limit 1)
  stat_FC56_Limit_23 : BOOL ;	//Memory for FC56, Limit No. 23 (Voltage, limit 2)
  stat_FC56_Limit_24 : BOOL ;	//Memory for FC56, Limit No. 24 (Voltage, limit 3)
  stat_FC56_Limit_25 : BOOL ;	//Memory for FC56, Limit No. 25 (Voltage, limit 4)
  stat_Underload : BOOL ;	//Generator underload  and 2, 3, 4 or more gen. sets in loadsharing mode
  stat_UndelayStop : BOOL ;	//Undelayed stop activated by generator protection
  stat_Trip_Temp_Overcurr : BOOL ;	//Genrator breaker off by Gen.Overtemp+Current limit 7
END_VAR
VAR_TEMP
  temp_OM_Local : BOOL ;	//Active operation mode: Local
  temp_OM_Semi_OP : BOOL ;	//Active operation mode: Semi automatic OP
  temp_OM_Auto_OP : BOOL ;	//Active operation mode: Auto OP
  temp_OM_Semi_MMI : BOOL ;	//Active operation mode: Semi automatic MMI
  temp_OM_Auto_MMI : BOOL ;	//Active operation mode: Auto MMI
  temp_OM_Test : BOOL ;	//Active operation mode: Test (EG only)
  temp_Reserve_006 : BOOL ;	//Reserved (Transfer Byte --> Bit)
  temp_Reserve_007 : BOOL ;	//Reserved (Transfer Byte --> Bit)
  temp_Limit_I1_used : BOOL ;	//Generator current, limit 1 used
  temp_Limit_I2_used : BOOL ;	//Generator current, limit 2 used
  temp_Limit_I3_used : BOOL ;	//Generator current, limit 3 used
  temp_Limit_I4_used : BOOL ;	//Generator current, limit 4 used
  temp_Limit_I5_used : BOOL ;	//Generator current, limit 5 used
  temp_Limit_I6_used : BOOL ;	//Generator current, limit 6 used
  temp_Limit_I7_used : BOOL ;	//Generator current, limit 7 used
  temp_Reserve_017 : BOOL ;	//Reserved (Transfer Byte --> Bit)
  temp_Limit_P1_used : BOOL ;	//Generator load, limit 1 used
  temp_Limit_P2_used : BOOL ;	//Generator load, limit 2 used
  temp_Limit_P3_used : BOOL ;	//Generator load, limit 3 used
  temp_Limit_P4_used : BOOL ;	//Generator load, limit 4 used
  temp_Limit_P5_used : BOOL ;	//Generator load, limit 5 used
  temp_Limit_P6_used : BOOL ;	//Generator load, limit 6 used
  temp_Limit_P7_used : BOOL ;	//Generator load, limit 7 used
  temp_Reserve_027 : BOOL ;	//Reserved (Transfer Byte --> Bit)
  temp_Limit_f1_used : BOOL ;	//Busbar frequency, limit 1 used
  temp_Limit_f2_used : BOOL ;	//Busbar frequency, limit 2 used
  temp_Limit_f3_used : BOOL ;	//Busbar frequency, limit 3 used
  temp_Limit_f4_used : BOOL ;	//Busbar frequency, limit 4 used
  temp_Limit_f5_used : BOOL ;	//Busbar frequency, limit 5 used
  temp_Limit_f6_used : BOOL ;	//Busbar frequency, limit 6 used
  temp_Limit_f7_used : BOOL ;	//Busbar frequency, limit 7 used
  temp_Limit_f8_used : BOOL ;	//Busbar frequency, limit 8 used
  temp_Limit_U1_used : BOOL ;	//Busbar voltage, limit 1 used
  temp_Limit_U2_used : BOOL ;	//Busbar voltage, limit 2 used
  temp_Limit_U3_used : BOOL ;	//Busbar voltage, limit 3 used
  temp_Limit_U4_used : BOOL ;	//Busbar voltage, limit 4 used
  temp_Reserve_044 : BOOL ;	//Reserved (Transfer Byte --> Bit)
  temp_Reserve_045 : BOOL ;	//Reserved (Transfer Byte --> Bit)
  temp_Reserve_046 : BOOL ;	//Reserved (Transfer Byte --> Bit)
  temp_Reserve_047 : BOOL ;	//Reserved (Transfer Byte --> Bit)
  temp_Auto : BOOL ;	//Active operation mode: Auto
  temp_Semi : BOOL ;	//Active operation mode: Semi automatic
  temp_ScratchFlag : BOOL ;	//Scratch flag
  temp_GenBrk_IndOn_Del : BOOL ;	//Off-delayed signal "Generator breaker On"
  temp_Stop_Overcurrent : BOOL ;	//Generator undelayed stop caused by overcurrent
  temp_Stop_ReversePower : BOOL ;	//Generator undelayed stop caused by reverse power
  temp_Stop_Underfrequ : BOOL ;	//Generator undelayed stop caused by underfrequency
  temp_Stop_Undervoltage : BOOL ;	//Generator undelayed stop caused by undervoltage
  temp_I_MeanMax : INT ;	//Difference mean value - extreme value
  temp_I_Max075 : INT ;	//Extreme value x 0,75
  temp_OverC_ext : BOOL ;	//overcurrent external exceeded
  temp_Volt_Blackout : BOOL ;	//Busbar voltage below the level for detecting blackout
END_VAR
BEGIN
NETWORK
TITLE =Active operation mode (Transfer Byte --> Bit)
//This transfer function is relaying on the relative addresses of the "temp"
//variables "temp_OM_Local" ... "temp_OM_Auto" in the area from 0.0 ... 0.7.
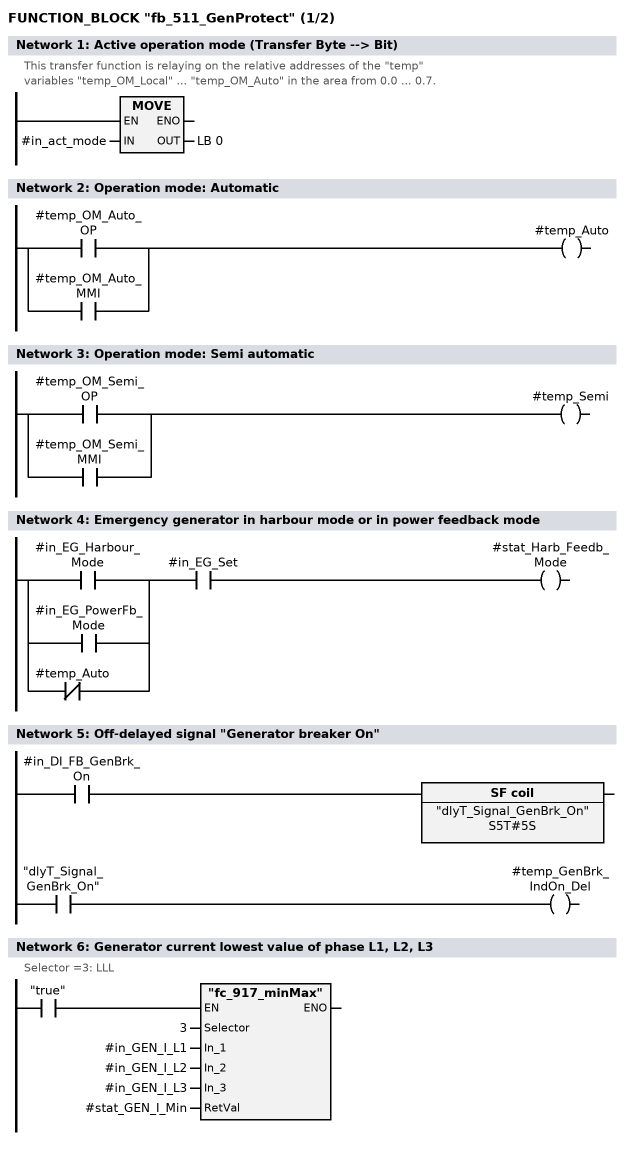
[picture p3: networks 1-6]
      L     #in_act_mode;
      T     LB     0;

NETWORK
TITLE =Operation mode: Automatic

      O     #temp_OM_Auto_OP;
      O     #temp_OM_Auto_MMI;
      =     #temp_Auto;
NETWORK
TITLE =Operation mode: Semi automatic

      O     #temp_OM_Semi_OP;
      O     #temp_OM_Semi_MMI;
      =     #temp_Semi;
NETWORK
TITLE =Emergency generator in harbour mode or in power feedback mode

      U(    ;
      O     #in_EG_Harbour_Mode;
      O     #in_EG_PowerFb_Mode;
      ON    #temp_Auto;
      )     ;
      U     #in_EG_Set;
      =     #stat_Harb_Feedb_Mode;
NETWORK
TITLE =Off-delayed signal "Generator breaker On"

      U     #in_DI_FB_GenBrk_On;
      L     S5T#5S;
      SA    "dlyT_Signal_GenBrk_On";
      NOP   0;
      NOP   0;
      NOP   0;
      U     "dlyT_Signal_GenBrk_On";
      =     #temp_GenBrk_IndOn_Del;
NETWORK
TITLE =Generator current lowest value of phase L1, L2, L3
//Selector =3: LLL
      U     "true";
      SPBNB _007;
      CALL "fc_917_minMax" (
           Selector                 := 3,
           In_1                     := #in_GEN_I_L1,
           In_2                     := #in_GEN_I_L2,
           In_3                     := #in_GEN_I_L3,
           RetVal                   := #stat_GEN_I_Min);
_007: NOP   0;
NETWORK
TITLE =Generator current highest value of phase L1, L2, L3
//Selector =1: HHH
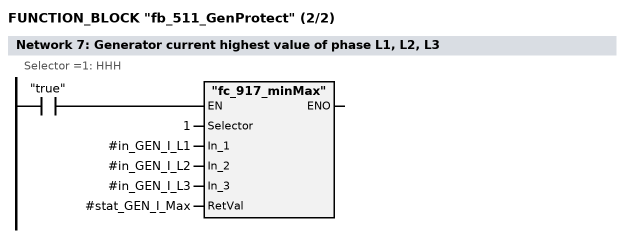
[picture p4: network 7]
      U     "true";
      SPBNB _00b;
      CALL "fc_917_minMax" (
           Selector                 := 1,
           In_1                     := #in_GEN_I_L1,
           In_2                     := #in_GEN_I_L2,
           In_3                     := #in_GEN_I_L3,
           RetVal                   := #stat_GEN_I_Max);
_00b: NOP   0;
NETWORK
TITLE =Generator current mean value of phase L1, L2, L3

      L     #in_GEN_I_L1;
      L     #in_GEN_I_L2;
      +I    ;
      L     #in_GEN_I_L3;
      +I    ;
      L     3;
      /I    ;
      T     #stat_GEN_I_Mean;
NETWORK
TITLE =Generator current highest value x factor (standard: 75%)

      L     #stat_GEN_I_Max;
      L     "prm_pma".p_DifCurrent;
      *D    ;
      L     10000;
      /D    ;
      T     #temp_I_Max075;
NETWORK
TITLE =Difference generator current mean value - highest value

      U     "true";
      SPBNB _00e;
      L     #stat_GEN_I_Mean;
      L     #stat_GEN_I_Max;
      -I    ;
      T     #temp_I_MeanMax;
_00e: NOP   0;
NETWORK
TITLE =Plausibility check of generator currents
//With this function the lowest value, the highest value and the mean value of
//the
//3 phases of the generator current are monitored and compared with each other.
//The monitoring is only active, when the generator breaker is closed.
//The following values are monitored:
//a) Mean value < 75% of highest value (i.e. unsymetrical current on the 3 phases)
//b) Mean value - highest value > 3% of nominal current
//   (i.e. mean value > highest value)
//c) Lowest value < 3% of nominal current
//d) Mean value < 3% of nominal current
//The monitoring functions a) or b) are only active, when the mean value or the
//highest value are > 10% of nominal current.
      U     #in_Reset;
      R     #out_Fail_Current;
      U(    ;
      U(    ;
      U(    ;
      L     #stat_GEN_I_Mean;
      L     #temp_I_Max075;
      <I    ;
      )     ;
      U(    ;
      L     #stat_GEN_I_Mean;
      L     1000;
      >I    ;
      )     ;
      O     ;
      U(    ;
      L     #temp_I_MeanMax;
      L     "prm_pma".p_LimCurrMonit;
      >I    ;
      )     ;
      U(    ;
      L     #stat_GEN_I_Max;
      L     1000;
      >I    ;
      )     ;
      O(    ;
      L     #stat_GEN_I_Min;
      L     "prm_pma".p_LimCurrMonit;
      <I    ;
      )     ;
      O(    ;
      L     #stat_GEN_I_Mean;
      L     "prm_pma".p_LimCurrMonit;
      <I    ;
      )     ;
      )     ;
      U     #in_DI_FB_GenBrk_On;
      L     "prm_pma".P_TFCurrent;
      SE    "dlyT_CurrMeasFail";
      NOP   0;
      NOP   0;
      NOP   0;
      U     "dlyT_CurrMeasFail";
      )     ;
      S     #out_Fail_Current;
      NOP   0;
NETWORK
TITLE =Mains (busbar) voltage, lowest value phase L1/L2, L2/L3, L3/L1
//Selector =3: LLL
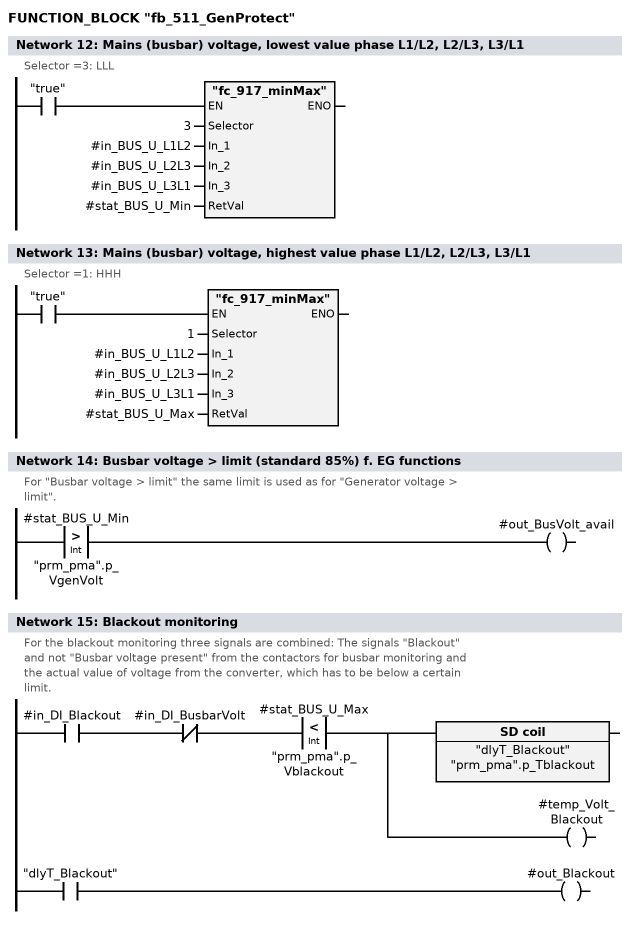
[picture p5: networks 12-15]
      U     "true";
      SPBNB _011;
      CALL "fc_917_minMax" (
           Selector                 := 3,
           In_1                     := #in_BUS_U_L1L2,
           In_2                     := #in_BUS_U_L2L3,
           In_3                     := #in_BUS_U_L3L1,
           RetVal                   := #stat_BUS_U_Min);
_011: NOP   0;
NETWORK
TITLE =Mains (busbar) voltage, highest value phase L1/L2, L2/L3, L3/L1
//Selector =1: HHH
      U     "true";
      SPBNB _012;
      CALL "fc_917_minMax" (
           Selector                 := 1,
           In_1                     := #in_BUS_U_L1L2,
           In_2                     := #in_BUS_U_L2L3,
           In_3                     := #in_BUS_U_L3L1,
           RetVal                   := #stat_BUS_U_Max);
_012: NOP   0;
NETWORK
TITLE =Busbar voltage > limit (standard 85%) f. EG functions
//For "Busbar voltage > limit" the same limit is used as for "Generator voltage >
//limit".
      L     #stat_BUS_U_Min;
      L     "prm_pma".p_VgenVolt;
      >I    ;
      =     #out_BusVolt_avail;
NETWORK
TITLE =Blackout monitoring
//For the blackout monitoring three signals are combined: The signals "Blackout"
//and not "Busbar voltage present" from the contactors for busbar monitoring and
//the actual value of voltage from the converter, which has to be below a certain
//limit.
      U     #in_DI_Blackout;
      UN    #in_DI_BusbarVolt;
      U(    ;
      L     #stat_BUS_U_Max;
      L     "prm_pma".p_Vblackout;
      <I    ;
      )     ;
      =     L     11.0;
      U     L     11.0;
      L     "prm_pma".p_Tblackout;
      SE    "dlyT_Blackout";
      NOP   0;
      NOP   0;
      NOP   0;
      U     "dlyT_Blackout";
      =     #out_Blackout;
      U     L     11.0;
      BLD   102;
      =     #temp_Volt_Blackout;
NETWORK
TITLE =Indication "Failure busbar/blackout monitoring"
//If both signals "Blackout" and "Busbar voltage present" from the contactors for
//busbar monitoring are present or both are not present, there is a failure in
//the
//busbar monitoring.
      U     #in_Reset;
      R     #out_Fail_Busbar;
      U(    ;
      U(    ;
      U     #in_DI_Blackout;
      U     #in_DI_BusbarVolt;
      O     ;
      UN    #in_DI_Blackout;
      UN    #in_DI_BusbarVolt;
      )     ;
      L     "prm_pma".p_TFBusbar;
      SE    "dlyT_BusbarFail";
      NOP   0;
      NOP   0;
      NOP   0;
      U     "dlyT_BusbarFail";
      )     ;
      S     #out_Fail_Busbar;
      NOP   0;
NETWORK
TITLE =Generator voltage, lowest value of phase L1/L2, L2/L3, L3/L1
//Selector =3: LLL
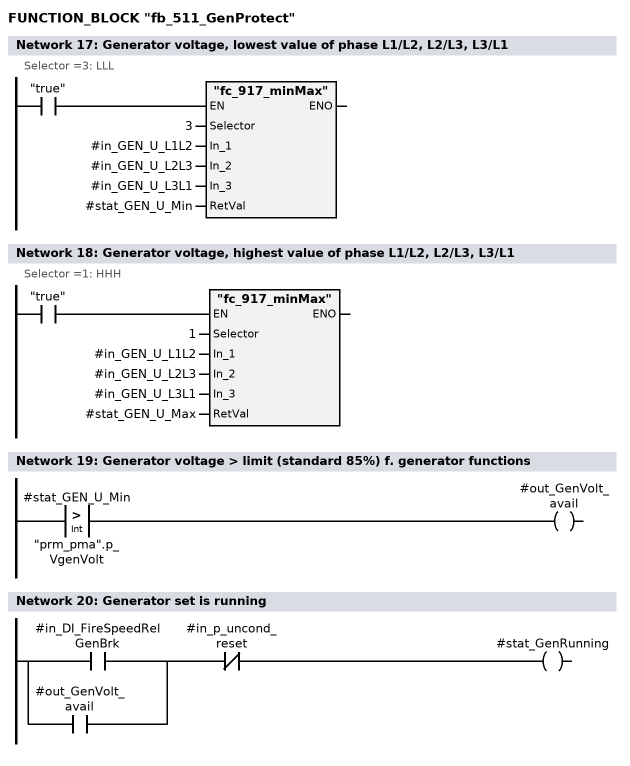
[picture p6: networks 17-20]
      U     "true";
      SPBNB _013;
      CALL "fc_917_minMax" (
           Selector                 := 3,
           In_1                     := #in_GEN_U_L1L2,
           In_2                     := #in_GEN_U_L2L3,
           In_3                     := #in_GEN_U_L3L1,
           RetVal                   := #stat_GEN_U_Min);
_013: NOP   0;
NETWORK
TITLE =Generator voltage, highest value of phase L1/L2, L2/L3, L3/L1
//Selector =1: HHH
      U     "true";
      SPBNB _017;
      CALL "fc_917_minMax" (
           Selector                 := 1,
           In_1                     := #in_GEN_U_L1L2,
           In_2                     := #in_GEN_U_L2L3,
           In_3                     := #in_GEN_U_L3L1,
           RetVal                   := #stat_GEN_U_Max);
_017: NOP   0;
NETWORK
TITLE =Generator voltage > limit (standard 85%) f. generator functions

      L     #stat_GEN_U_Min;
      L     "prm_pma".p_VgenVolt;
      >I    ;
      =     #out_GenVolt_avail;
NETWORK
TITLE =Generator set is running

      U(    ;
      O     #in_DI_FireSpeedRelGenBrk;
      O     #out_GenVolt_avail;
      )     ;
      UN    #in_p_uncond_reset;
      =     #stat_GenRunning;
NETWORK
TITLE =Short circuit
//The generator breaker trip in case of short circuit is made independently of
//the
//Simatic S7
//a) by the GENOP71 (internal) or
//b) by a tripping device installed in the generator breaker (external).
//
//The signal from the GENOP71 is surpressed after the run-up of the SIMATIC
//S7-CPU
//(Initializing pulse, 2s) in order to avoid a short circuit trip due to wrong
//signals on the bus GENOP71-CPU at this time.
//
//The signal from an external tripping device can be used only, if this signals
//is
//exclusively a short circuit signal, and is not activated by other reasons (for
//example overcurrent).
//
//The short circuit signal is sent to other generator sets in order to avoid a
//second generator to connect to a bus bar short circuit. This signal is delayed
//for a short time in order to give time for a bus tie breaker to open. It is
//given as a pulse in order to allow other sets to be resetted and started by the
//operator.
      U(    ;
      U     #in_Reset;
      UN    #stat_GenRunning;
      R     #stat_ShortCircuit;
      U(    ;
      U     #in_GENOP_ShortCircuit;
      UN    "INIT_Pulse";
      O     ;
      U     #in_Overc_ShortC_extern;
      U     "prm_pma".p_SC_Device_Avail;
      )     ;
      S     #stat_ShortCircuit;
      U     #stat_ShortCircuit;
      )     ;
      L     "prm_pma".p_TPulse_sc;
      SV    "plsT_sc";
      NOP   0;
      NOP   0;
      NOP   0;
      U     "plsT_sc";
      =     #out_ShortCirc_OtherGen;
NETWORK
TITLE =Latch for signal "2. short circuit from other generator set"

      U     #in_ShortCirc_OtherGen;
      FP    #stat_ShC_OtherSet_Aux;
      =     L     11.0;
      U     #stat_ShC_OtherSet1;
      U     L     11.0;
      S     #stat_ShC_OtherSet2;
      U     #stat_ShC_OtherSet_Reset;
      R     #stat_ShC_OtherSet2;
      NOP   0;
      U     L     11.0;
      BLD   102;
      =     #stat_ShC_OtherSet_Pulse;
NETWORK
TITLE =Latch for signal "1. short circuit from other generator set"

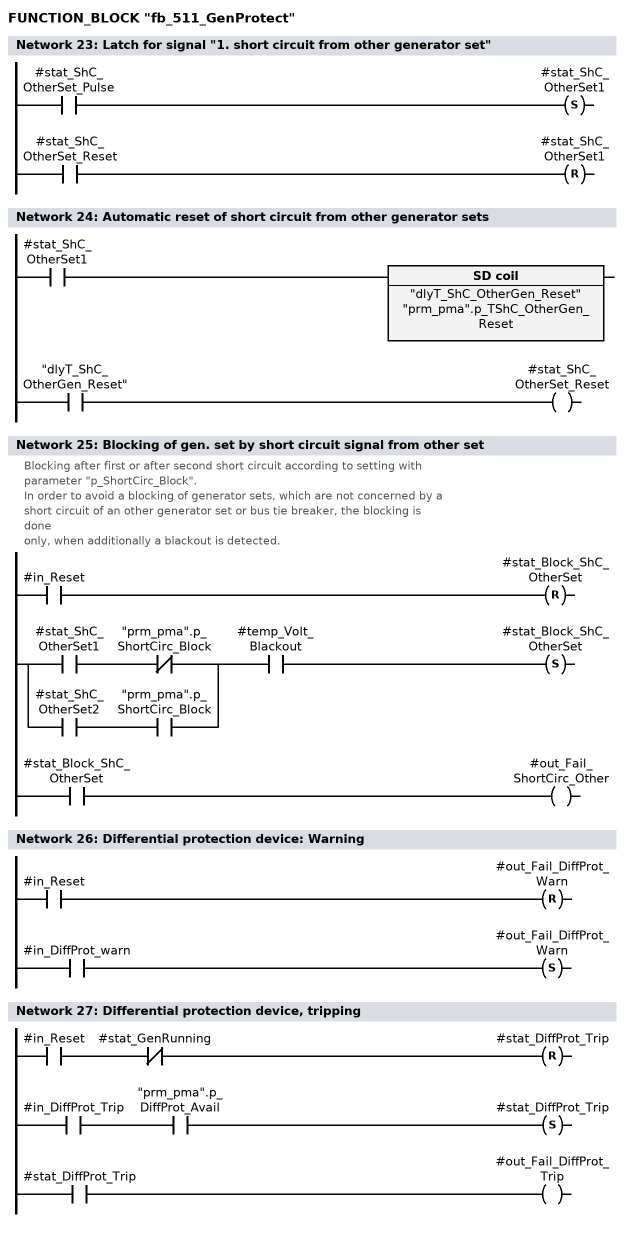
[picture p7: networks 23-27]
      U     #stat_ShC_OtherSet_Pulse;
      S     #stat_ShC_OtherSet1;
      U     #stat_ShC_OtherSet_Reset;
      R     #stat_ShC_OtherSet1;
      NOP   0;
NETWORK
TITLE =Automatic reset of short circuit from other generator sets

      U     #stat_ShC_OtherSet1;
      L     "prm_pma".p_TShC_OtherGen_Reset;
      SE    "dlyT_ShC_OtherGen_Reset";
      NOP   0;
      NOP   0;
      NOP   0;
      U     "dlyT_ShC_OtherGen_Reset";
      =     #stat_ShC_OtherSet_Reset;
NETWORK
TITLE =Blocking of gen. set by short circuit signal from other set
//Blocking after first or after second short circuit according to setting with
//parameter "p_ShortCirc_Block".
//In order to avoid a blocking of generator sets, which are not concerned by a
//short circuit of an other generator set or bus tie breaker, the blocking is
//done
//only, when additionally a blackout is detected.
      U     #in_Reset;
      R     #stat_Block_ShC_OtherSet;
      U(    ;
      U     #stat_ShC_OtherSet1;
      UN    "prm_pma".p_ShortCirc_Block;
      O     ;
      U     #stat_ShC_OtherSet2;
      U     "prm_pma".p_ShortCirc_Block;
      )     ;
      U     #temp_Volt_Blackout;
      S     #stat_Block_ShC_OtherSet;
      U     #stat_Block_ShC_OtherSet;
      =     #out_Fail_ShortCirc_Other;
NETWORK
TITLE =Differential protection device: Warning

      U     #in_Reset;
      R     #out_Fail_DiffProt_Warn;
      U     #in_DiffProt_warn;
      S     #out_Fail_DiffProt_Warn;
      NOP   0;
NETWORK
TITLE =Differential protection device, tripping

      U     #in_Reset;
      UN    #stat_GenRunning;
      R     #stat_DiffProt_Trip;
      U     #in_DiffProt_Trip;
      U     "prm_pma".p_DiffProt_Avail;
      S     #stat_DiffProt_Trip;
      U     #stat_DiffProt_Trip;
      =     #out_Fail_DiffProt_Trip;
NETWORK
TITLE =Transfer of parameters (Byte --> Bit)
//This transfer function is relaying on the relative adresses of the "temp"
//variables "temp_Limit_I1_used" ... "temp_Limit_U3_used" in the address area
//1.0 ...  4.7.
      U     #in_EG_Set;
      SPB   EG;
//Standard Diesel/Shaft generator mode
      L     DB41.DBW  178;
      T     LB     1;
      L     DB41.DBW  180;
      T     LB     2;
      L     DB41.DBW  182;
      T     LB     3;
      L     DB41.DBW  184;
      T     LB     4;
      SPA   End;

EG:   O     #in_EG_Harbour_Mode;
      O     #in_EG_PowerFb_Mode;
      SPB   Harb;
//Emergency generator mode
      L     DB41.DBW  564;
      T     LB     1;
      L     DB41.DBW  566;
      T     LB     2;
      L     DB41.DBW  568;
      T     LB     3;
      L     DB41.DBW  570;
      T     LB     4;
      SPA   End;

Harb: U     #in_EG_PowerFb_Mode;
      SPB   PFbk;
//Harbour mode
      L     DB41.DBW  572;
      T     LB     1;
      L     DB41.DBW  574;
      T     LB     2;
      L     DB41.DBW  576;
      T     LB     3;
      L     DB41.DBW  578;
      T     LB     4;
      SPA   End;

PFbk: NOP   0;
//Power feedback mode
      L     DB41.DBW  580;
      T     LB     1;
      L     DB41.DBW  582;
      T     LB     2;
      L     DB41.DBW  584;
      T     LB     3;
      L     DB41.DBW  586;
      T     LB     4;

End:  NOP   0;
NETWORK
TITLE =Generator current, limit 1 (Standby start)

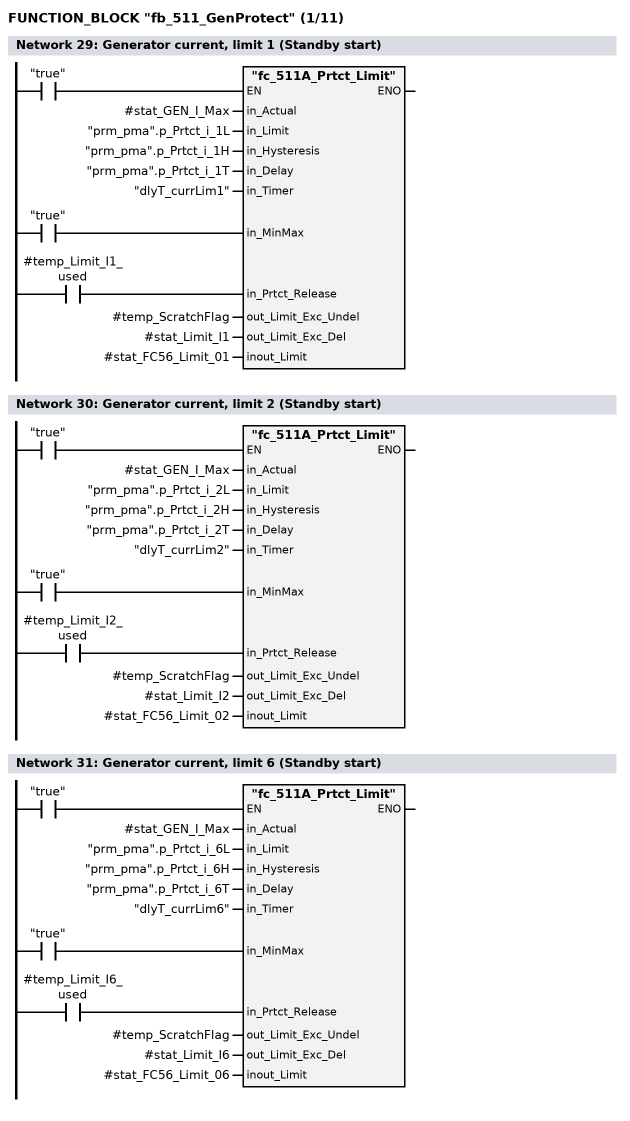
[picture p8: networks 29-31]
      U     "true";
      =     L     11.0;
      BLD   103;
      U     #temp_Limit_I1_used;
      =     L     11.1;
      BLD   103;
      U     "true";
      SPBNB _01b;
      CALL "fc_511A_Prtct_Limit" (
           in_Actual                := #stat_GEN_I_Max,
           in_Limit                 := "prm_pma".p_Prtct_i_1L,
           in_Hysteresis            := "prm_pma".p_Prtct_i_1H,
           in_Delay                 := "prm_pma".p_Prtct_i_1T,
           in_Timer                 := "dlyT_currLim1",
           in_MinMax                := L     11.0,
           in_Prtct_Release         := L     11.1,
           out_Limit_Exc_Undel      := #temp_ScratchFlag,
           out_Limit_Exc_Del        := #stat_Limit_I1,
           inout_Limit              := #stat_FC56_Limit_01);
_01b: NOP   0;
NETWORK
TITLE =Generator current, limit 2 (Standby start)

      U     "true";
      =     L     11.0;
      BLD   103;
      U     #temp_Limit_I2_used;
      =     L     11.1;
      BLD   103;
      U     "true";
      SPBNB _01c;
      CALL "fc_511A_Prtct_Limit" (
           in_Actual                := #stat_GEN_I_Max,
           in_Limit                 := "prm_pma".p_Prtct_i_2L,
           in_Hysteresis            := "prm_pma".p_Prtct_i_2H,
           in_Delay                 := "prm_pma".p_Prtct_i_2T,
           in_Timer                 := "dlyT_currLim2",
           in_MinMax                := L     11.0,
           in_Prtct_Release         := L     11.1,
           out_Limit_Exc_Undel      := #temp_ScratchFlag,
           out_Limit_Exc_Del        := #stat_Limit_I2,
           inout_Limit              := #stat_FC56_Limit_02);
_01c: NOP   0;
NETWORK
TITLE =Generator current, limit 6 (Standby start)

      U     "true";
      =     L     11.0;
      BLD   103;
      U     #temp_Limit_I6_used;
      =     L     11.1;
      BLD   103;
      U     "true";
      SPBNB _01d;
      CALL "fc_511A_Prtct_Limit" (
           in_Actual                := #stat_GEN_I_Max,
           in_Limit                 := "prm_pma".p_Prtct_i_6L,
           in_Hysteresis            := "prm_pma".p_Prtct_i_6H,
           in_Delay                 := "prm_pma".p_Prtct_i_6T,
           in_Timer                 := "dlyT_currLim6",
           in_MinMax                := L     11.0,
           in_Prtct_Release         := L     11.1,
           out_Limit_Exc_Undel      := #temp_ScratchFlag,
           out_Limit_Exc_Del        := #stat_Limit_I6,
           inout_Limit              := #stat_FC56_Limit_06);
_01d: NOP   0;
NETWORK
TITLE =Generator current, limit 7 (Generator breaker Off)

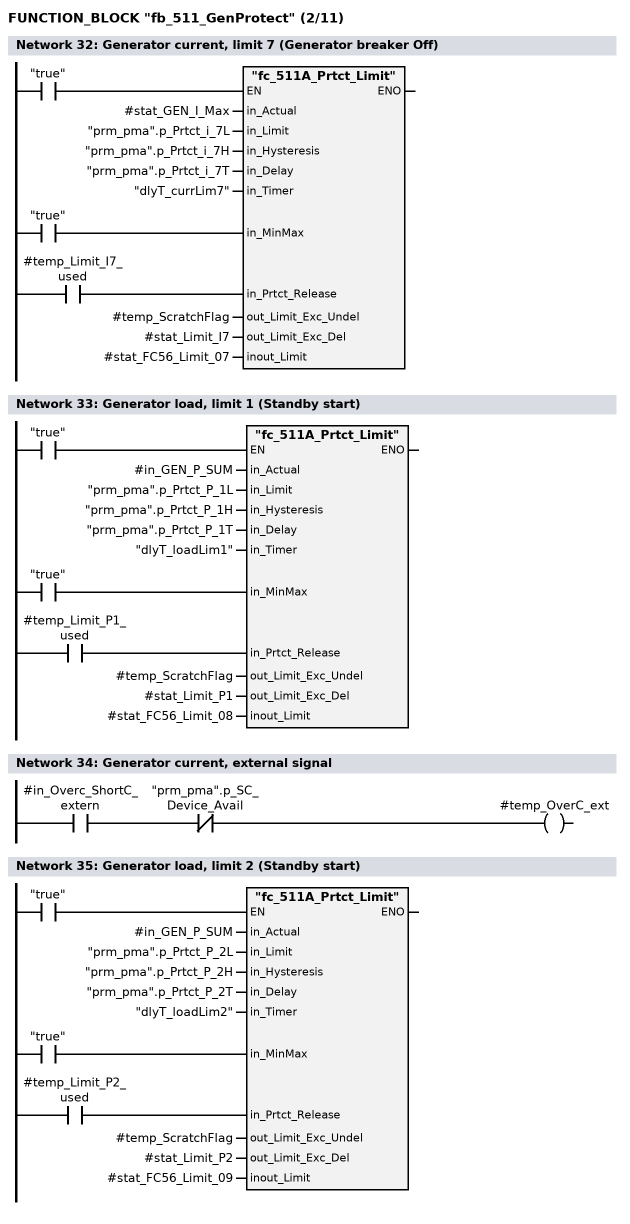
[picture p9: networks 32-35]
      U     "true";
      =     L     11.0;
      BLD   103;
      U     #temp_Limit_I7_used;
      =     L     11.1;
      BLD   103;
      U     "true";
      SPBNB _01e;
      CALL "fc_511A_Prtct_Limit" (
           in_Actual                := #stat_GEN_I_Max,
           in_Limit                 := "prm_pma".p_Prtct_i_7L,
           in_Hysteresis            := "prm_pma".p_Prtct_i_7H,
           in_Delay                 := "prm_pma".p_Prtct_i_7T,
           in_Timer                 := "dlyT_currLim7",
           in_MinMax                := L     11.0,
           in_Prtct_Release         := L     11.1,
           out_Limit_Exc_Undel      := #temp_ScratchFlag,
           out_Limit_Exc_Del        := #stat_Limit_I7,
           inout_Limit              := #stat_FC56_Limit_07);
_01e: NOP   0;
NETWORK
TITLE =Generator load, limit 1 (Standby start)

      U     "true";
      =     L     11.0;
      BLD   103;
      U     #temp_Limit_P1_used;
      =     L     11.1;
      BLD   103;
      U     "true";
      SPBNB _01f;
      CALL "fc_511A_Prtct_Limit" (
           in_Actual                := #in_GEN_P_SUM,
           in_Limit                 := "prm_pma".p_Prtct_P_1L,
           in_Hysteresis            := "prm_pma".p_Prtct_P_1H,
           in_Delay                 := "prm_pma".p_Prtct_P_1T,
           in_Timer                 := "dlyT_loadLim1",
           in_MinMax                := L     11.0,
           in_Prtct_Release         := L     11.1,
           out_Limit_Exc_Undel      := #temp_ScratchFlag,
           out_Limit_Exc_Del        := #stat_Limit_P1,
           inout_Limit              := #stat_FC56_Limit_08);
_01f: NOP   0;
NETWORK
TITLE =Generator current, external signal

      U     #in_Overc_ShortC_extern;
      UN    "prm_pma".p_SC_Device_Avail;
      =     #temp_OverC_ext;
NETWORK
TITLE =Generator load, limit 2 (Standby start)

      U     "true";
      =     L     11.0;
      BLD   103;
      U     #temp_Limit_P2_used;
      =     L     11.1;
      BLD   103;
      U     "true";
      SPBNB _024;
      CALL "fc_511A_Prtct_Limit" (
           in_Actual                := #in_GEN_P_SUM,
           in_Limit                 := "prm_pma".p_Prtct_P_2L,
           in_Hysteresis            := "prm_pma".p_Prtct_P_2H,
           in_Delay                 := "prm_pma".p_Prtct_P_2T,
           in_Timer                 := "dlyT_loadLim2",
           in_MinMax                := L     11.0,
           in_Prtct_Release         := L     11.1,
           out_Limit_Exc_Undel      := #temp_ScratchFlag,
           out_Limit_Exc_Del        := #stat_Limit_P2,
           inout_Limit              := #stat_FC56_Limit_09);
_024: NOP   0;
NETWORK
TITLE =Generator load, limit 3 (Unessential consumers 1)

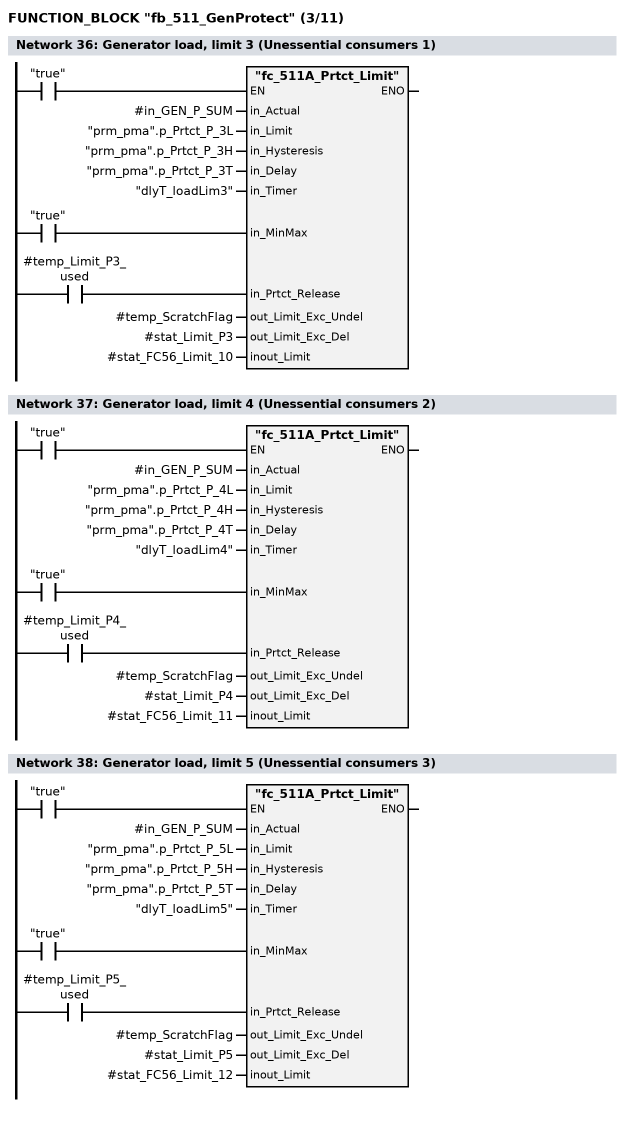
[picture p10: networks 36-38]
      U     "true";
      =     L     11.0;
      BLD   103;
      U     #temp_Limit_P3_used;
      =     L     11.1;
      BLD   103;
      U     "true";
      SPBNB _025;
      CALL "fc_511A_Prtct_Limit" (
           in_Actual                := #in_GEN_P_SUM,
           in_Limit                 := "prm_pma".p_Prtct_P_3L,
           in_Hysteresis            := "prm_pma".p_Prtct_P_3H,
           in_Delay                 := "prm_pma".p_Prtct_P_3T,
           in_Timer                 := "dlyT_loadLim3",
           in_MinMax                := L     11.0,
           in_Prtct_Release         := L     11.1,
           out_Limit_Exc_Undel      := #temp_ScratchFlag,
           out_Limit_Exc_Del        := #stat_Limit_P3,
           inout_Limit              := #stat_FC56_Limit_10);
_025: NOP   0;
NETWORK
TITLE =Generator load, limit 4 (Unessential consumers 2)

      U     "true";
      =     L     11.0;
      BLD   103;
      U     #temp_Limit_P4_used;
      =     L     11.1;
      BLD   103;
      U     "true";
      SPBNB _026;
      CALL "fc_511A_Prtct_Limit" (
           in_Actual                := #in_GEN_P_SUM,
           in_Limit                 := "prm_pma".p_Prtct_P_4L,
           in_Hysteresis            := "prm_pma".p_Prtct_P_4H,
           in_Delay                 := "prm_pma".p_Prtct_P_4T,
           in_Timer                 := "dlyT_loadLim4",
           in_MinMax                := L     11.0,
           in_Prtct_Release         := L     11.1,
           out_Limit_Exc_Undel      := #temp_ScratchFlag,
           out_Limit_Exc_Del        := #stat_Limit_P4,
           inout_Limit              := #stat_FC56_Limit_11);
_026: NOP   0;
NETWORK
TITLE =Generator load, limit 5 (Unessential consumers 3)

      U     "true";
      =     L     11.0;
      BLD   103;
      U     #temp_Limit_P5_used;
      =     L     11.1;
      BLD   103;
      U     "true";
      SPBNB _027;
      CALL "fc_511A_Prtct_Limit" (
           in_Actual                := #in_GEN_P_SUM,
           in_Limit                 := "prm_pma".p_Prtct_P_5L,
           in_Hysteresis            := "prm_pma".p_Prtct_P_5H,
           in_Delay                 := "prm_pma".p_Prtct_P_5T,
           in_Timer                 := "dlyT_loadLim5",
           in_MinMax                := L     11.0,
           in_Prtct_Release         := L     11.1,
           out_Limit_Exc_Undel      := #temp_ScratchFlag,
           out_Limit_Exc_Del        := #stat_Limit_P5,
           inout_Limit              := #stat_FC56_Limit_12);
_027: NOP   0;
NETWORK
TITLE =Gen. load, limit 6 (Standby start, uness. consumers 1, 2, 3)

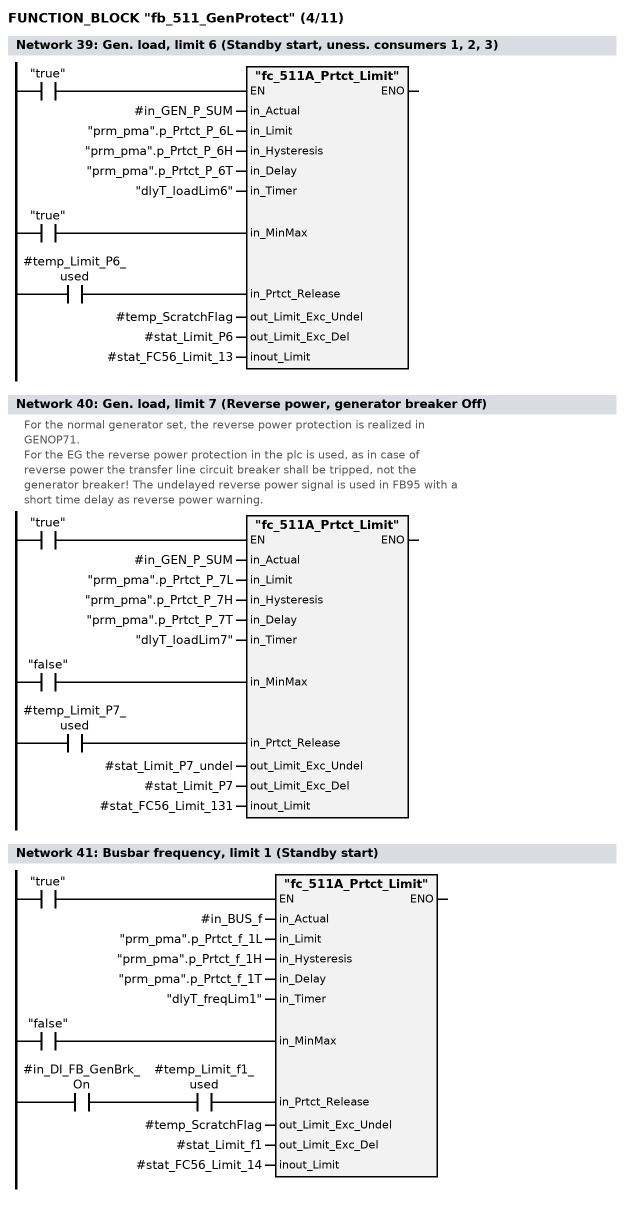
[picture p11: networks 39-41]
      U     "true";
      =     L     11.0;
      BLD   103;
      U     #temp_Limit_P6_used;
      =     L     11.1;
      BLD   103;
      U     "true";
      SPBNB _02a;
      CALL "fc_511A_Prtct_Limit" (
           in_Actual                := #in_GEN_P_SUM,
           in_Limit                 := "prm_pma".p_Prtct_P_6L,
           in_Hysteresis            := "prm_pma".p_Prtct_P_6H,
           in_Delay                 := "prm_pma".p_Prtct_P_6T,
           in_Timer                 := "dlyT_loadLim6",
           in_MinMax                := L     11.0,
           in_Prtct_Release         := L     11.1,
           out_Limit_Exc_Undel      := #temp_ScratchFlag,
           out_Limit_Exc_Del        := #stat_Limit_P6,
           inout_Limit              := #stat_FC56_Limit_13);
_02a: NOP   0;
NETWORK
TITLE =Gen. load, limit 7 (Reverse power, generator breaker Off)
//For the normal generator set, the reverse power protection is realized in
//GENOP71.
//
//For the EG the reverse power protection in the plc is used, as in case of
//reverse power the transfer line circuit breaker shall be tripped, not the
//generator breaker! The undelayed reverse power signal is used in FB95 with a
//short time delay as reverse power warning.
      U     "false";
      =     L     11.0;
      BLD   103;
      U     #temp_Limit_P7_used;
      =     L     11.1;
      BLD   103;
      U     "true";
      SPBNB _02f;
      CALL "fc_511A_Prtct_Limit" (
           in_Actual                := #in_GEN_P_SUM,
           in_Limit                 := "prm_pma".p_Prtct_P_7L,
           in_Hysteresis            := "prm_pma".p_Prtct_P_7H,
           in_Delay                 := "prm_pma".p_Prtct_P_7T,
           in_Timer                 := "dlyT_loadLim7",
           in_MinMax                := L     11.0,
           in_Prtct_Release         := L     11.1,
           out_Limit_Exc_Undel      := #stat_Limit_P7_undel,
           out_Limit_Exc_Del        := #stat_Limit_P7,
           inout_Limit              := #stat_FC56_Limit_131);
_02f: NOP   0;
NETWORK
TITLE =Busbar frequency, limit 1 (Standby start)

      U     "false";
      =     L     11.0;
      BLD   103;
      U     #in_DI_FB_GenBrk_On;
      U     #temp_Limit_f1_used;
      =     L     11.1;
      BLD   103;
      U     "true";
      SPBNB _031;
      CALL "fc_511A_Prtct_Limit" (
           in_Actual                := #in_BUS_f,
           in_Limit                 := "prm_pma".p_Prtct_f_1L,
           in_Hysteresis            := "prm_pma".p_Prtct_f_1H,
           in_Delay                 := "prm_pma".p_Prtct_f_1T,
           in_Timer                 := "dlyT_freqLim1",
           in_MinMax                := L     11.0,
           in_Prtct_Release         := L     11.1,
           out_Limit_Exc_Undel      := #temp_ScratchFlag,
           out_Limit_Exc_Del        := #stat_Limit_f1,
           inout_Limit              := #stat_FC56_Limit_14);
_031: NOP   0;
NETWORK
TITLE =Busbar frequency, limit 2 (Standby start)

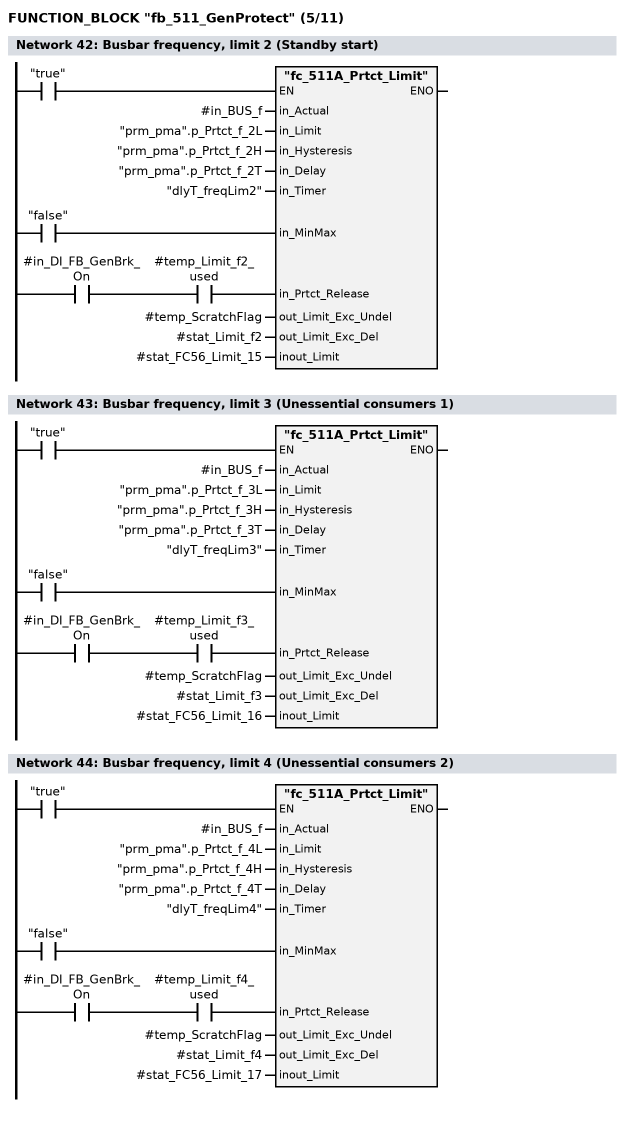
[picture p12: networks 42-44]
      U     "false";
      =     L     11.0;
      BLD   103;
      U     #in_DI_FB_GenBrk_On;
      U     #temp_Limit_f2_used;
      =     L     11.1;
      BLD   103;
      U     "true";
      SPBNB _032;
      CALL "fc_511A_Prtct_Limit" (
           in_Actual                := #in_BUS_f,
           in_Limit                 := "prm_pma".p_Prtct_f_2L,
           in_Hysteresis            := "prm_pma".p_Prtct_f_2H,
           in_Delay                 := "prm_pma".p_Prtct_f_2T,
           in_Timer                 := "dlyT_freqLim2",
           in_MinMax                := L     11.0,
           in_Prtct_Release         := L     11.1,
           out_Limit_Exc_Undel      := #temp_ScratchFlag,
           out_Limit_Exc_Del        := #stat_Limit_f2,
           inout_Limit              := #stat_FC56_Limit_15);
_032: NOP   0;
NETWORK
TITLE =Busbar frequency, limit 3 (Unessential consumers 1)

      U     "false";
      =     L     11.0;
      BLD   103;
      U     #in_DI_FB_GenBrk_On;
      U     #temp_Limit_f3_used;
      =     L     11.1;
      BLD   103;
      U     "true";
      SPBNB _033;
      CALL "fc_511A_Prtct_Limit" (
           in_Actual                := #in_BUS_f,
           in_Limit                 := "prm_pma".p_Prtct_f_3L,
           in_Hysteresis            := "prm_pma".p_Prtct_f_3H,
           in_Delay                 := "prm_pma".p_Prtct_f_3T,
           in_Timer                 := "dlyT_freqLim3",
           in_MinMax                := L     11.0,
           in_Prtct_Release         := L     11.1,
           out_Limit_Exc_Undel      := #temp_ScratchFlag,
           out_Limit_Exc_Del        := #stat_Limit_f3,
           inout_Limit              := #stat_FC56_Limit_16);
_033: NOP   0;
NETWORK
TITLE =Busbar frequency, limit 4 (Unessential consumers 2)

      U     "false";
      =     L     11.0;
      BLD   103;
      U     #in_DI_FB_GenBrk_On;
      U     #temp_Limit_f4_used;
      =     L     11.1;
      BLD   103;
      U     "true";
      SPBNB _037;
      CALL "fc_511A_Prtct_Limit" (
           in_Actual                := #in_BUS_f,
           in_Limit                 := "prm_pma".p_Prtct_f_4L,
           in_Hysteresis            := "prm_pma".p_Prtct_f_4H,
           in_Delay                 := "prm_pma".p_Prtct_f_4T,
           in_Timer                 := "dlyT_freqLim4",
           in_MinMax                := L     11.0,
           in_Prtct_Release         := L     11.1,
           out_Limit_Exc_Undel      := #temp_ScratchFlag,
           out_Limit_Exc_Del        := #stat_Limit_f4,
           inout_Limit              := #stat_FC56_Limit_17);
_037: NOP   0;
NETWORK
TITLE =Busbar frequency, limit 5 (Unessential consumers 3)

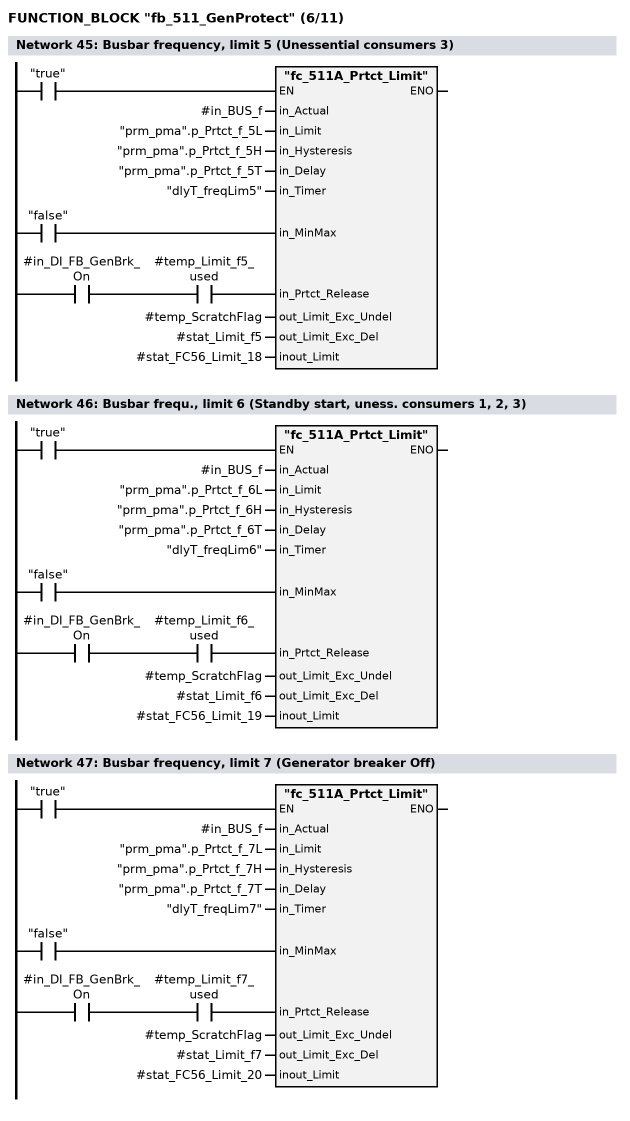
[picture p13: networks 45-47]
      U     "false";
      =     L     11.0;
      BLD   103;
      U     #in_DI_FB_GenBrk_On;
      U     #temp_Limit_f5_used;
      =     L     11.1;
      BLD   103;
      U     "true";
      SPBNB _03b;
      CALL "fc_511A_Prtct_Limit" (
           in_Actual                := #in_BUS_f,
           in_Limit                 := "prm_pma".p_Prtct_f_5L,
           in_Hysteresis            := "prm_pma".p_Prtct_f_5H,
           in_Delay                 := "prm_pma".p_Prtct_f_5T,
           in_Timer                 := "dlyT_freqLim5",
           in_MinMax                := L     11.0,
           in_Prtct_Release         := L     11.1,
           out_Limit_Exc_Undel      := #temp_ScratchFlag,
           out_Limit_Exc_Del        := #stat_Limit_f5,
           inout_Limit              := #stat_FC56_Limit_18);
_03b: NOP   0;
NETWORK
TITLE =Busbar frequ., limit 6 (Standby start, uness. consumers 1, 2, 3)

      U     "false";
      =     L     11.0;
      BLD   103;
      U     #in_DI_FB_GenBrk_On;
      U     #temp_Limit_f6_used;
      =     L     11.1;
      BLD   103;
      U     "true";
      SPBNB _03c;
      CALL "fc_511A_Prtct_Limit" (
           in_Actual                := #in_BUS_f,
           in_Limit                 := "prm_pma".p_Prtct_f_6L,
           in_Hysteresis            := "prm_pma".p_Prtct_f_6H,
           in_Delay                 := "prm_pma".p_Prtct_f_6T,
           in_Timer                 := "dlyT_freqLim6",
           in_MinMax                := L     11.0,
           in_Prtct_Release         := L     11.1,
           out_Limit_Exc_Undel      := #temp_ScratchFlag,
           out_Limit_Exc_Del        := #stat_Limit_f6,
           inout_Limit              := #stat_FC56_Limit_19);
_03c: NOP   0;
NETWORK
TITLE =Busbar frequency, limit 7 (Generator breaker Off)

      U     "false";
      =     L     11.0;
      BLD   103;
      U     #in_DI_FB_GenBrk_On;
      U     #temp_Limit_f7_used;
      =     L     11.1;
      BLD   103;
      U     "true";
      SPBNB _03d;
      CALL "fc_511A_Prtct_Limit" (
           in_Actual                := #in_BUS_f,
           in_Limit                 := "prm_pma".p_Prtct_f_7L,
           in_Hysteresis            := "prm_pma".p_Prtct_f_7H,
           in_Delay                 := "prm_pma".p_Prtct_f_7T,
           in_Timer                 := "dlyT_freqLim7",
           in_MinMax                := L     11.0,
           in_Prtct_Release         := L     11.1,
           out_Limit_Exc_Undel      := #temp_ScratchFlag,
           out_Limit_Exc_Del        := #stat_Limit_f7,
           inout_Limit              := #stat_FC56_Limit_20);
_03d: NOP   0;
NETWORK
TITLE =Busbar frequency, limit 8 (Overfrequency alarm)

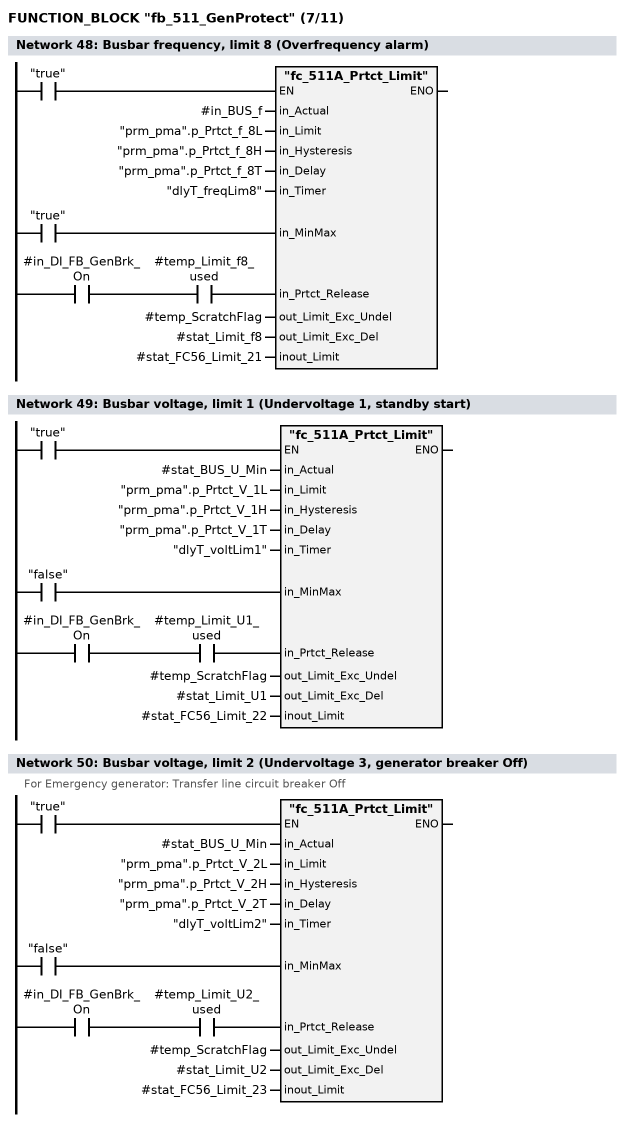
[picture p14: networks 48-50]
      U     "true";
      =     L     11.0;
      BLD   103;
      U     #in_DI_FB_GenBrk_On;
      U     #temp_Limit_f8_used;
      =     L     11.1;
      BLD   103;
      U     "true";
      SPBNB _03e;
      CALL "fc_511A_Prtct_Limit" (
           in_Actual                := #in_BUS_f,
           in_Limit                 := "prm_pma".p_Prtct_f_8L,
           in_Hysteresis            := "prm_pma".p_Prtct_f_8H,
           in_Delay                 := "prm_pma".p_Prtct_f_8T,
           in_Timer                 := "dlyT_freqLim8",
           in_MinMax                := L     11.0,
           in_Prtct_Release         := L     11.1,
           out_Limit_Exc_Undel      := #temp_ScratchFlag,
           out_Limit_Exc_Del        := #stat_Limit_f8,
           inout_Limit              := #stat_FC56_Limit_21);
_03e: NOP   0;
NETWORK
TITLE =Busbar voltage, limit 1 (Undervoltage 1, standby start)

      U     "false";
      =     L     11.0;
      BLD   103;
      U     #in_DI_FB_GenBrk_On;
      U     #temp_Limit_U1_used;
      =     L     11.1;
      BLD   103;
      U     "true";
      SPBNB _03f;
      CALL "fc_511A_Prtct_Limit" (
           in_Actual                := #stat_BUS_U_Min,
           in_Limit                 := "prm_pma".p_Prtct_V_1L,
           in_Hysteresis            := "prm_pma".p_Prtct_V_1H,
           in_Delay                 := "prm_pma".p_Prtct_V_1T,
           in_Timer                 := "dlyT_voltLim1",
           in_MinMax                := L     11.0,
           in_Prtct_Release         := L     11.1,
           out_Limit_Exc_Undel      := #temp_ScratchFlag,
           out_Limit_Exc_Del        := #stat_Limit_U1,
           inout_Limit              := #stat_FC56_Limit_22);
_03f: NOP   0;
NETWORK
TITLE =Busbar voltage, limit 2 (Undervoltage 3, generator breaker Off)
//For Emergency generator: Transfer line circuit breaker Off
      U     "false";
      =     L     11.0;
      BLD   103;
      U     #in_DI_FB_GenBrk_On;
      U     #temp_Limit_U2_used;
      =     L     11.1;
      BLD   103;
      U     "true";
      SPBNB _043;
      CALL "fc_511A_Prtct_Limit" (
           in_Actual                := #stat_BUS_U_Min,
           in_Limit                 := "prm_pma".p_Prtct_V_2L,
           in_Hysteresis            := "prm_pma".p_Prtct_V_2H,
           in_Delay                 := "prm_pma".p_Prtct_V_2T,
           in_Timer                 := "dlyT_voltLim2",
           in_MinMax                := L     11.0,
           in_Prtct_Release         := L     11.1,
           out_Limit_Exc_Undel      := #temp_ScratchFlag,
           out_Limit_Exc_Del        := #stat_Limit_U2,
           inout_Limit              := #stat_FC56_Limit_23);
_043: NOP   0;
NETWORK
TITLE =Busbar voltage, limit 3 (Overvoltage 1, standby start)

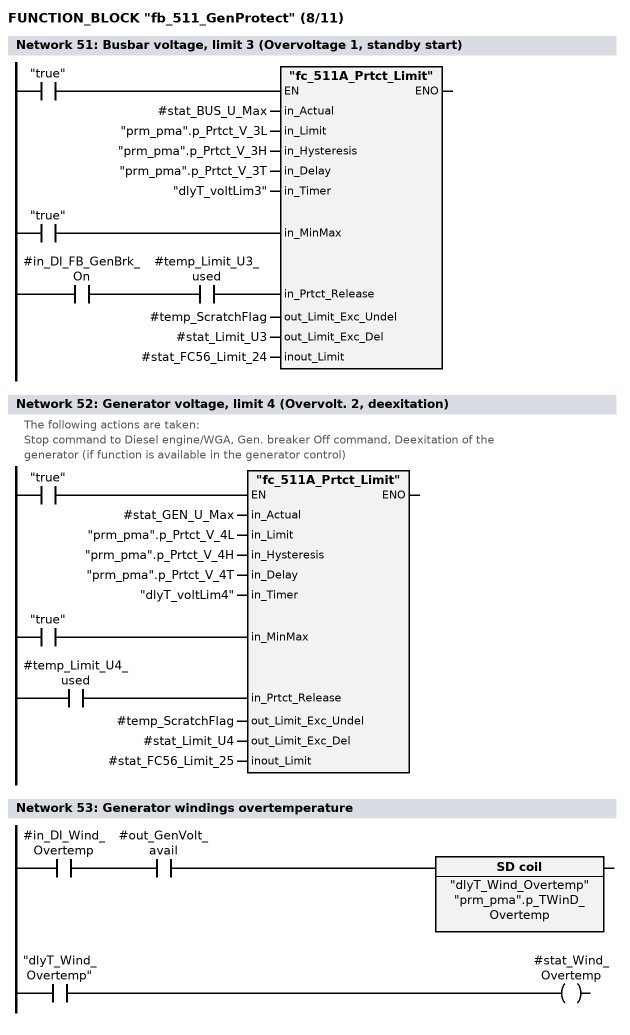
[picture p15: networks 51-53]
      U     "true";
      =     L     11.0;
      BLD   103;
      U     #in_DI_FB_GenBrk_On;
      U     #temp_Limit_U3_used;
      =     L     11.1;
      BLD   103;
      U     "true";
      SPBNB _056;
      CALL "fc_511A_Prtct_Limit" (
           in_Actual                := #stat_BUS_U_Max,
           in_Limit                 := "prm_pma".p_Prtct_V_3L,
           in_Hysteresis            := "prm_pma".p_Prtct_V_3H,
           in_Delay                 := "prm_pma".p_Prtct_V_3T,
           in_Timer                 := "dlyT_voltLim3",
           in_MinMax                := L     11.0,
           in_Prtct_Release         := L     11.1,
           out_Limit_Exc_Undel      := #temp_ScratchFlag,
           out_Limit_Exc_Del        := #stat_Limit_U3,
           inout_Limit              := #stat_FC56_Limit_24);
_056: NOP   0;
NETWORK
TITLE =Generator voltage, limit 4 (Overvolt. 2, deexitation)
//The following actions are taken:
//Stop command to Diesel engine/WGA, Gen. breaker Off command, Deexitation of the
//generator (if function is available in the generator control)
      U     "true";
      =     L     11.0;
      BLD   103;
      U     #temp_Limit_U4_used;
      =     L     11.1;
      BLD   103;
      U     "true";
      SPBNB _05d;
      CALL "fc_511A_Prtct_Limit" (
           in_Actual                := #stat_GEN_U_Max,
           in_Limit                 := "prm_pma".p_Prtct_V_4L,
           in_Hysteresis            := "prm_pma".p_Prtct_V_4H,
           in_Delay                 := "prm_pma".p_Prtct_V_4T,
           in_Timer                 := "dlyT_voltLim4",
           in_MinMax                := L     11.0,
           in_Prtct_Release         := L     11.1,
           out_Limit_Exc_Undel      := #temp_ScratchFlag,
           out_Limit_Exc_Del        := #stat_Limit_U4,
           inout_Limit              := #stat_FC56_Limit_25);
_05d: NOP   0;
NETWORK
TITLE =Generator windings overtemperature

      U     #in_DI_Wind_Overtemp;
      U     #out_GenVolt_avail;
      L     "prm_pma".p_TWinD_Overtemp;
      SE    "dlyT_Wind_Overtemp";
      NOP   0;
      NOP   0;
      NOP   0;
      U     "dlyT_Wind_Overtemp";
      =     #stat_Wind_Overtemp;
NETWORK
TITLE =Start command for standby generator, caused by GENOP71

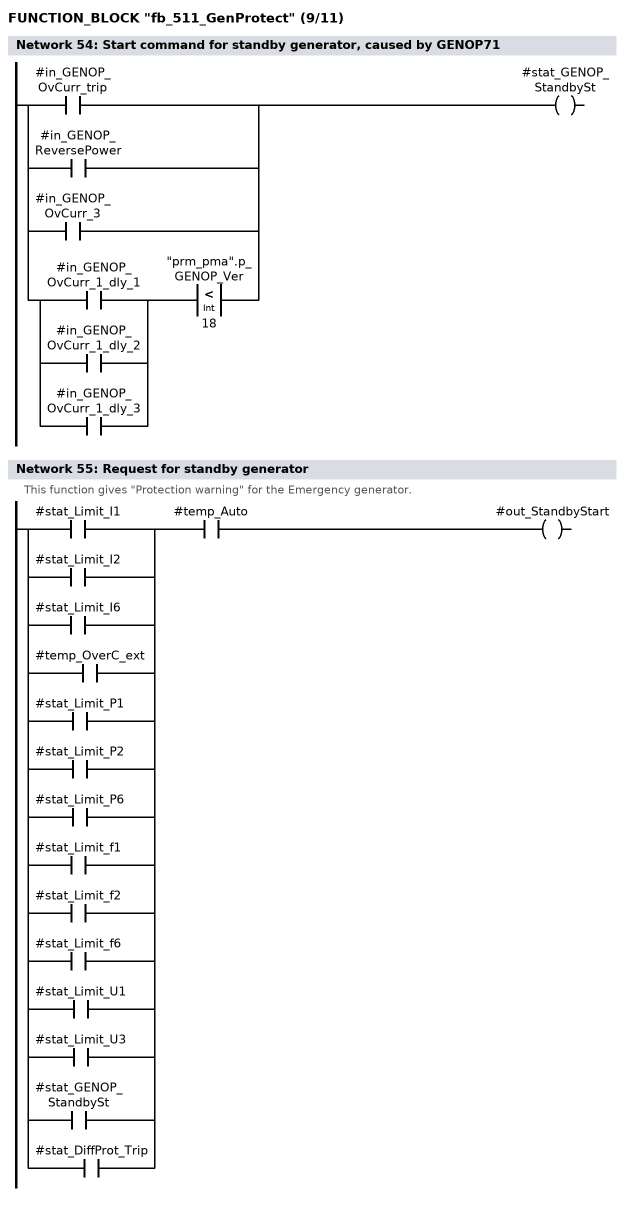
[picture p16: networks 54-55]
      O     #in_GENOP_OvCurr_trip;
      O     #in_GENOP_ReversePower;
      O     #in_GENOP_OvCurr_3;
      O     ;
      U(    ;
      O     #in_GENOP_OvCurr_1_dly_1;
      O     #in_GENOP_OvCurr_1_dly_2;
      O     #in_GENOP_OvCurr_1_dly_3;
      )     ;
      U(    ;
      L     "prm_pma".p_GENOP_Ver;
      L     18;
      <I    ;
      )     ;
      =     #stat_GENOP_StandbySt;
NETWORK
TITLE =Request for standby generator
//This function gives "Protection warning" for the Emergency generator.
      U(    ;
      O     #stat_Limit_I1;
      O     #stat_Limit_I2;
      O     #stat_Limit_I6;
      O     #temp_OverC_ext;
      O     #stat_Limit_P1;
      O     #stat_Limit_P2;
      O     #stat_Limit_P6;
      O     #stat_Limit_f1;
      O     #stat_Limit_f2;
      O     #stat_Limit_f6;
      O     #stat_Limit_U1;
      O     #stat_Limit_U3;
      O     #stat_GENOP_StandbySt;
      O     #stat_DiffProt_Trip;
      )     ;
      U     #temp_Auto;
      =     #out_StandbyStart;
NETWORK
TITLE =Change over to new started set via blackout (no synchronizing)
//In some cases after the standby start no synchronizing is made, but change-over
//with blackout:
//Underfrequency: Synchronizing may be not possible due to limiting of the speed
//controller of the diesel engine / shaft generator
//Under-/Overvoltage: High currents due to different voltages generator/busbar
//
//This function is controlled with parameters in DB41.
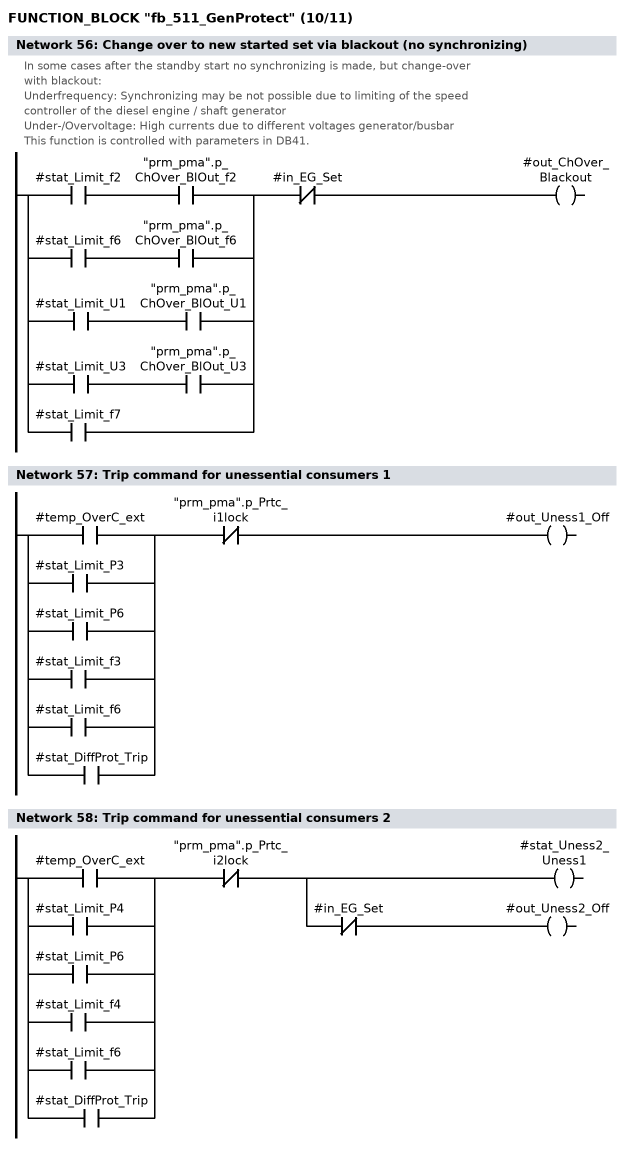
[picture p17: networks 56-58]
      U(    ;
      U     #stat_Limit_f2;
      U     "prm_pma".p_ChOver_BlOut_f2;
      O     ;
      U     #stat_Limit_f6;
      U     "prm_pma".p_ChOver_BlOut_f6;
      O     ;
      U     #stat_Limit_U1;
      U     "prm_pma".p_ChOver_BlOut_U1;
      O     ;
      U     #stat_Limit_U3;
      U     "prm_pma".p_ChOver_BlOut_U3;
      O     #stat_Limit_f7;
      )     ;
      UN    #in_EG_Set;
      =     #out_ChOver_Blackout;
NETWORK
TITLE =Trip command for unessential consumers 1

      U(    ;
      O     #temp_OverC_ext;
      O     #stat_Limit_P3;
      O     #stat_Limit_P6;
      O     #stat_Limit_f3;
      O     #stat_Limit_f6;
      O     #stat_DiffProt_Trip;
      )     ;
      UN    "prm_pma".p_Prtc_i1lock;
      =     #out_Uness1_Off;
NETWORK
TITLE =Trip command for unessential consumers 2

      U(    ;
      O     #temp_OverC_ext;
      O     #stat_Limit_P4;
      O     #stat_Limit_P6;
      O     #stat_Limit_f4;
      O     #stat_Limit_f6;
      O     #stat_DiffProt_Trip;
      )     ;
      UN    "prm_pma".p_Prtc_i2lock;
      =     L     11.0;
      U     L     11.0;
      BLD   102;
      =     #stat_Uness2_Uness1;
      U     L     11.0;
      UN    #in_EG_Set;
      =     #out_Uness2_Off;
NETWORK
TITLE =Trip command for unessential consumers 3

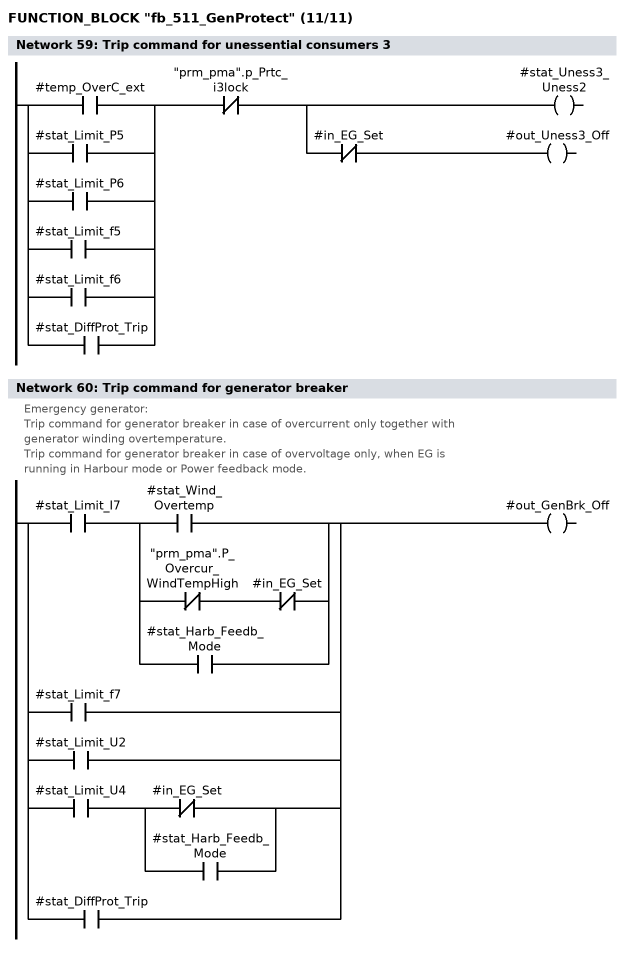
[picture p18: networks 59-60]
      U(    ;
      O     #temp_OverC_ext;
      O     #stat_Limit_P5;
      O     #stat_Limit_P6;
      O     #stat_Limit_f5;
      O     #stat_Limit_f6;
      O     #stat_DiffProt_Trip;
      )     ;
      UN    "prm_pma".p_Prtc_i3lock;
      =     L     11.0;
      U     L     11.0;
      BLD   102;
      =     #stat_Uness3_Uness2;
      U     L     11.0;
      UN    #in_EG_Set;
      =     #out_Uness3_Off;
NETWORK
TITLE =Trip command for generator breaker
//Emergency generator:
//Trip command for generator breaker in case of overcurrent only together with
//generator winding overtemperature.
//Trip command for generator breaker in case of overvoltage only, when EG is
//running in Harbour mode or Power feedback mode.
      U     #stat_Limit_I7;
      U(    ;
      O     #stat_Wind_Overtemp;
      O     ;
      UN    "prm_pma".P_Overcur_WindTempHigh;
      UN    #in_EG_Set;
      O     #stat_Harb_Feedb_Mode;
      )     ;
      O     #stat_Limit_f7;
      O     #stat_Limit_U2;
      O     ;
      U     #stat_Limit_U4;
      U(    ;
      ON    #in_EG_Set;
      O     #stat_Harb_Feedb_Mode;
      )     ;
      O     #stat_DiffProt_Trip;
      =     #out_GenBrk_Off;
NETWORK
TITLE =Latch for signal "Generator breaker trip by overcurrent"
//Indication "Overcurrent"
      O(    ;
      U     #in_Reset;
      R     #stat_Trip_Overcurrent;
      U(    ;
      O     #in_GENOP_OvCurr_trip;
      O     #temp_OverC_ext;
      )     ;
      S     #stat_Trip_Overcurrent;
      U     #stat_Trip_Overcurrent;
      )     ;
      O     #stat_Trip_Temp_Overcurr;
      =     #out_Fail_Overcurr;
NETWORK
TITLE =Latch for signal "Generator breaker trip by reverse power"
//Indication "Reverse power"
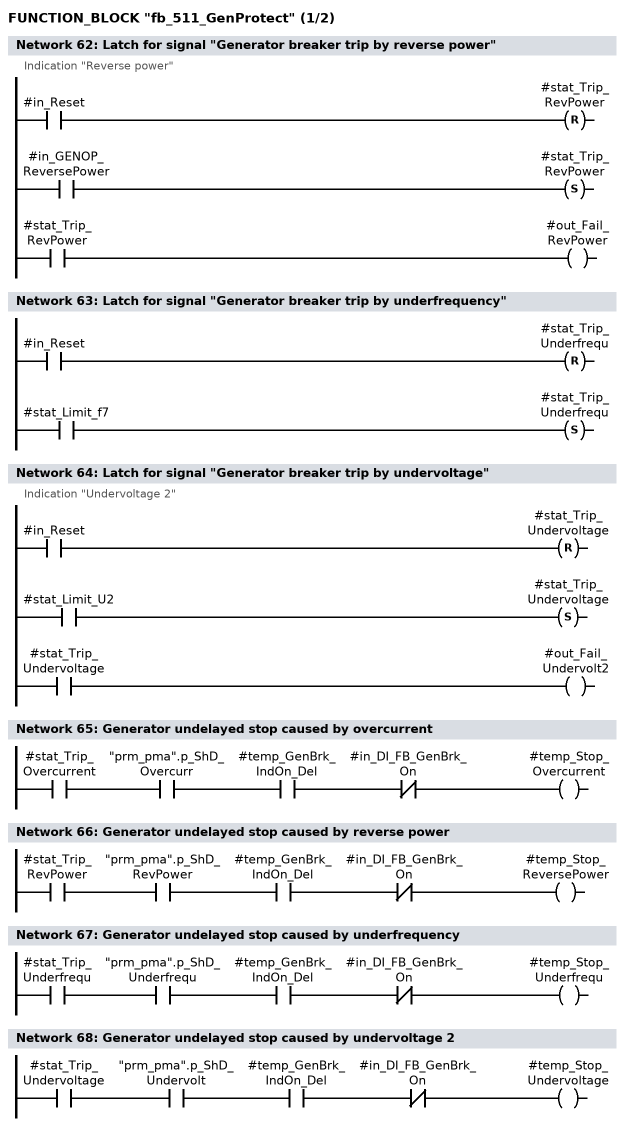
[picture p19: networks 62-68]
      U     #in_Reset;
      R     #stat_Trip_RevPower;
      U     #in_GENOP_ReversePower;
      S     #stat_Trip_RevPower;
      U     #stat_Trip_RevPower;
      =     #out_Fail_RevPower;
NETWORK
TITLE =Latch for signal "Generator breaker trip by underfrequency"

      U     #in_Reset;
      R     #stat_Trip_Underfrequ;
      U     #stat_Limit_f7;
      S     #stat_Trip_Underfrequ;
      NOP   0;
NETWORK
TITLE =Latch for signal "Generator breaker trip by undervoltage"
//Indication "Undervoltage 2"
      U     #in_Reset;
      R     #stat_Trip_Undervoltage;
      U     #stat_Limit_U2;
      S     #stat_Trip_Undervoltage;
      U     #stat_Trip_Undervoltage;
      =     #out_Fail_Undervolt2;
NETWORK
TITLE =Generator undelayed stop caused by overcurrent

      U     #stat_Trip_Overcurrent;
      U     "prm_pma".p_ShD_Overcurr;
      U     #temp_GenBrk_IndOn_Del;
      UN    #in_DI_FB_GenBrk_On;
      =     #temp_Stop_Overcurrent;
NETWORK
TITLE =Generator undelayed stop caused by reverse power

      U     #stat_Trip_RevPower;
      U     "prm_pma".p_ShD_RevPower;
      U     #temp_GenBrk_IndOn_Del;
      UN    #in_DI_FB_GenBrk_On;
      =     #temp_Stop_ReversePower;
NETWORK
TITLE =Generator undelayed stop caused by underfrequency

      U     #stat_Trip_Underfrequ;
      U     "prm_pma".p_ShD_Underfrequ;
      U     #temp_GenBrk_IndOn_Del;
      UN    #in_DI_FB_GenBrk_On;
      =     #temp_Stop_Underfrequ;
NETWORK
TITLE =Generator undelayed stop caused by undervoltage 2

      U     #stat_Trip_Undervoltage;
      U     "prm_pma".p_ShD_Undervolt;
      U     #temp_GenBrk_IndOn_Del;
      UN    #in_DI_FB_GenBrk_On;
      =     #temp_Stop_Undervoltage;
NETWORK
TITLE =Undelayed stop to diesel engine (FB47)/shaft generator (FB49)

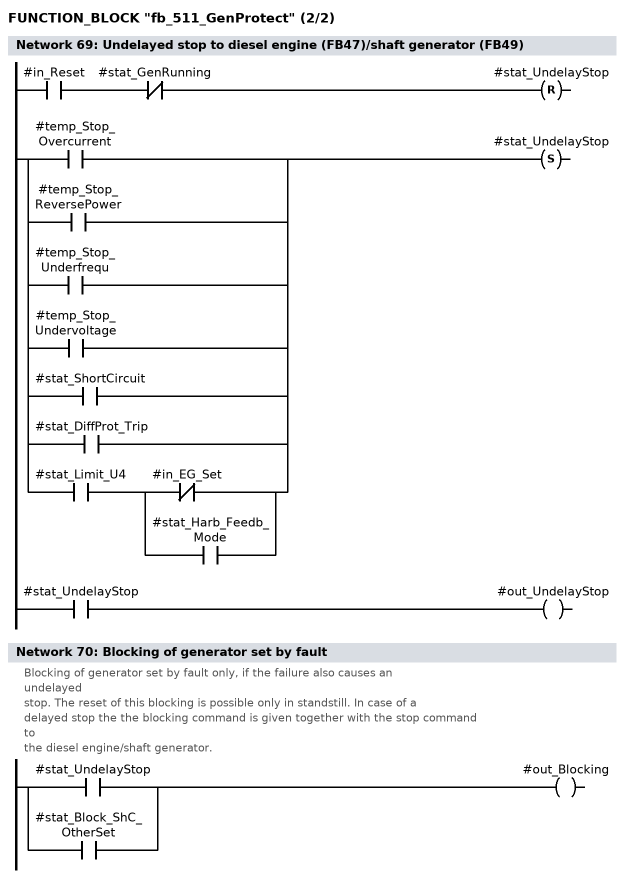
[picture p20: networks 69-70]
      U     #in_Reset;
      UN    #stat_GenRunning;
      R     #stat_UndelayStop;
      U(    ;
      O     #temp_Stop_Overcurrent;
      O     #temp_Stop_ReversePower;
      O     #temp_Stop_Underfrequ;
      O     #temp_Stop_Undervoltage;
      O     #stat_ShortCircuit;
      O     #stat_DiffProt_Trip;
      O     ;
      U     #stat_Limit_U4;
      U(    ;
      ON    #in_EG_Set;
      O     #stat_Harb_Feedb_Mode;
      )     ;
      )     ;
      S     #stat_UndelayStop;
      U     #stat_UndelayStop;
      =     #out_UndelayStop;
NETWORK
TITLE =Blocking of generator set by fault
//Blocking of generator set by fault only, if the failure also causes an
//undelayed
//stop. The reset of this blocking is possible only in standstill. In case of a
//delayed stop the the blocking command is given together with the stop command
//to
//the diesel engine/shaft generator.
      O     #stat_UndelayStop;
      O     #stat_Block_ShC_OtherSet;
      =     #out_Blocking;
NETWORK
TITLE =Forced change over from "Automatic" to "Semi automatic" mode
//The blocking of the generator set always causes a change over from "Automatic"
//to "Semi automatic" mode. There may be some additional conditions, which cause
//a
//changeover to "Semi automatic" mode, but no blocking.
      O     #out_Blocking;
      O     #stat_Trip_Overcurrent;
      O(    ;
      U     #stat_Limit_I7;
      U(    ;
      O     #stat_Wind_Overtemp;
      ON    #in_EG_Set;
      )     ;
      S     #stat_Trip_Temp_Overcurr;
      U     #in_Reset;
      R     #stat_Trip_Temp_Overcurr;
      U     #stat_Trip_Temp_Overcurr;
      )     ;
      O     #stat_Trip_RevPower;
      O     #stat_Trip_Underfrequ;
      O     #stat_Trip_Undervoltage;
      =     #out_ChOver_Semi;
NETWORK
TITLE =Blocking of the voltage controller in case of overvoltage
//In case of a heavy exceeding of the nominal voltage or in case of a
//differential protection trip signal, the voltage controller is
//blocked (deexitation of the generator). At the same time the generator breaker
//is tripped and an undelayed stop command is given to the diesel engine/shaft
//generator control.
//The reset is not possible, before the diesel engine/SG is stopped.
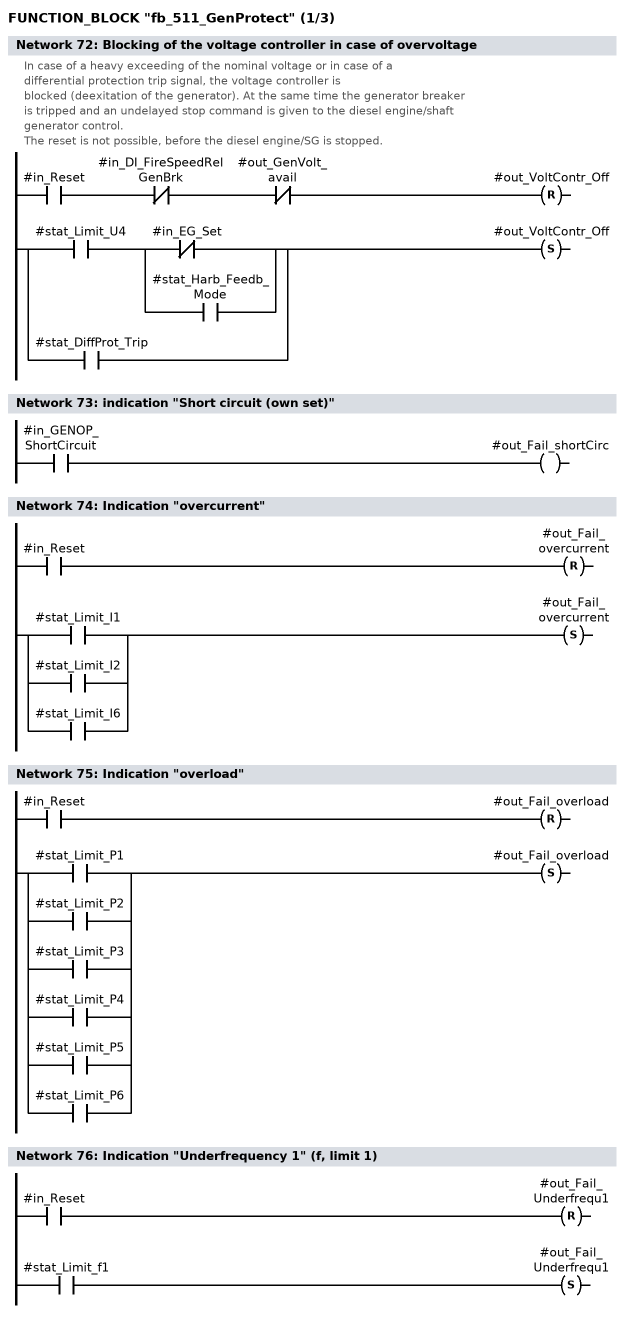
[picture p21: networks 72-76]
      U     #in_Reset;
      UN    #in_DI_FireSpeedRelGenBrk;
      UN    #out_GenVolt_avail;
      R     #out_VoltContr_Off;
      U(    ;
      U     #stat_Limit_U4;
      U(    ;
      ON    #in_EG_Set;
      O     #stat_Harb_Feedb_Mode;
      )     ;
      O     #stat_DiffProt_Trip;
      )     ;
      S     #out_VoltContr_Off;
      NOP   0;
NETWORK
TITLE =indication "Short circuit (own set)"

      U     #in_GENOP_ShortCircuit;
      =     #out_Fail_shortCirc;
NETWORK
TITLE =Indication "overcurrent"

      U     #in_Reset;
      R     #out_Fail_overcurrent;
      U(    ;
      O     #stat_Limit_I1;
      O     #stat_Limit_I2;
      O     #stat_Limit_I6;
      )     ;
      S     #out_Fail_overcurrent;
      NOP   0;
NETWORK
TITLE =Indication "overload"

      U     #in_Reset;
      R     #out_Fail_overload;
      U(    ;
      O     #stat_Limit_P1;
      O     #stat_Limit_P2;
      O     #stat_Limit_P3;
      O     #stat_Limit_P4;
      O     #stat_Limit_P5;
      O     #stat_Limit_P6;
      )     ;
      S     #out_Fail_overload;
      NOP   0;
NETWORK
TITLE =Indication "Underfrequency 1" (f, limit 1)

      U     #in_Reset;
      R     #out_Fail_Underfrequ1;
      U     #stat_Limit_f1;
      S     #out_Fail_Underfrequ1;
      NOP   0;
NETWORK
TITLE =Indication "Underfrequency 2" (f, limit 3)

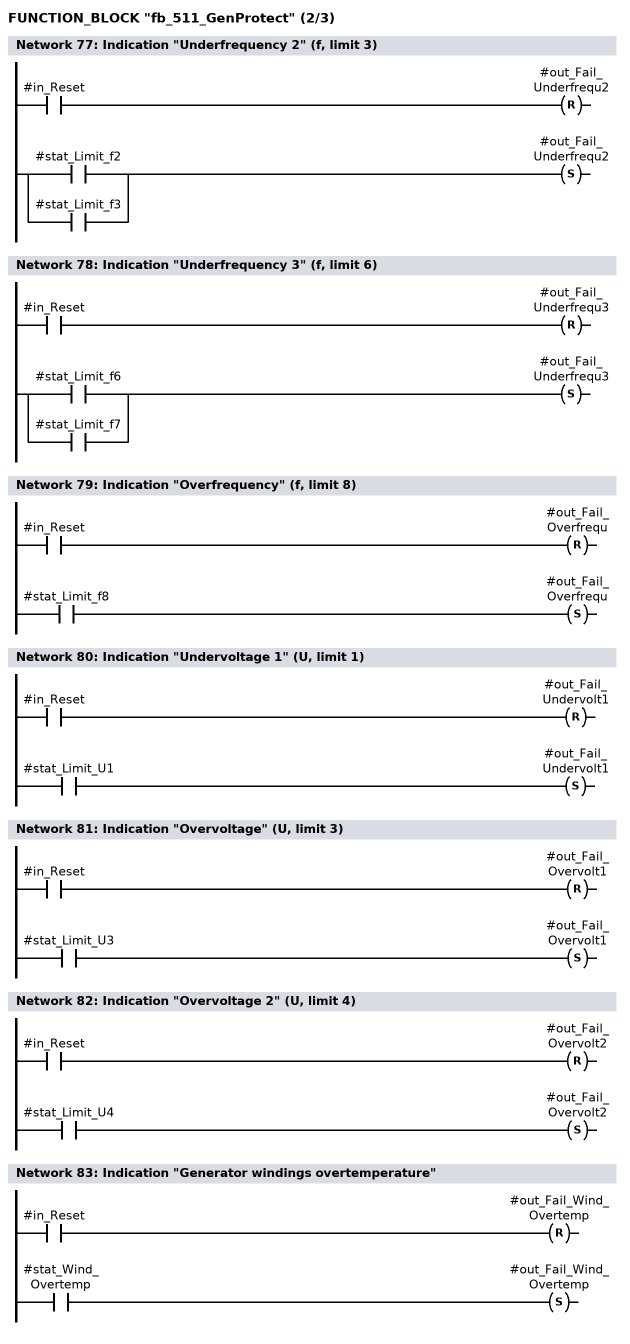
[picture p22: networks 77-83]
      U     #in_Reset;
      R     #out_Fail_Underfrequ2;
      U(    ;
      O     #stat_Limit_f2;
      O     #stat_Limit_f3;
      )     ;
      S     #out_Fail_Underfrequ2;
      NOP   0;
NETWORK
TITLE =Indication "Underfrequency 3" (f, limit 6)

      U     #in_Reset;
      R     #out_Fail_Underfrequ3;
      U(    ;
      O     #stat_Limit_f6;
      O     #stat_Limit_f7;
      )     ;
      S     #out_Fail_Underfrequ3;
      NOP   0;
NETWORK
TITLE =Indication "Overfrequency" (f, limit 8)

      U     #in_Reset;
      R     #out_Fail_Overfrequ;
      U     #stat_Limit_f8;
      S     #out_Fail_Overfrequ;
      NOP   0;
NETWORK
TITLE =Indication "Undervoltage 1" (U, limit 1)

      U     #in_Reset;
      R     #out_Fail_Undervolt1;
      U     #stat_Limit_U1;
      S     #out_Fail_Undervolt1;
      NOP   0;
NETWORK
TITLE =Indication "Overvoltage" (U, limit 3)

      U     #in_Reset;
      R     #out_Fail_Overvolt1;
      U     #stat_Limit_U3;
      S     #out_Fail_Overvolt1;
      NOP   0;
NETWORK
TITLE =Indication "Overvoltage 2" (U, limit 4)

      U     #in_Reset;
      R     #out_Fail_Overvolt2;
      U     #stat_Limit_U4;
      S     #out_Fail_Overvolt2;
      NOP   0;
NETWORK
TITLE =Indication "Generator windings overtemperature"

      U     #in_Reset;
      R     #out_Fail_Wind_Overtemp;
      U     #stat_Wind_Overtemp;
      S     #out_Fail_Wind_Overtemp;
      NOP   0;
NETWORK
TITLE =Underload and 2, 3, 4 or more gen. sets in load sharing mode

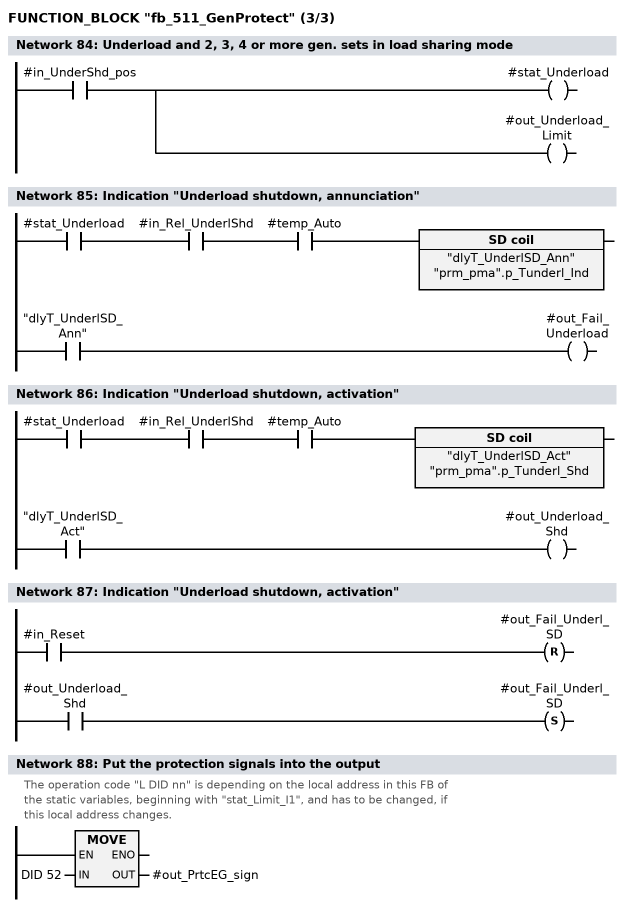
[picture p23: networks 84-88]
      U     #in_UnderShd_pos;
      =     #stat_Underload;
      =     #out_Underload_Limit;
NETWORK
TITLE =Indication "Underload shutdown, annunciation"

      U     #stat_Underload;
      U     #in_Rel_UnderlShd;
      U     #temp_Auto;
      L     "prm_pma".p_Tunderl_Ind;
      SE    "dlyT_UnderlSD_Ann";
      NOP   0;
      NOP   0;
      NOP   0;
      U     "dlyT_UnderlSD_Ann";
      =     #out_Fail_Underload;
NETWORK
TITLE =Indication "Underload shutdown, activation"

      U     #stat_Underload;
      U     #in_Rel_UnderlShd;
      U     #temp_Auto;
      L     "prm_pma".p_Tunderl_Shd;
      SE    "dlyT_UnderlSD_Act";
      NOP   0;
      NOP   0;
      NOP   0;
      U     "dlyT_UnderlSD_Act";
      =     #out_Underload_Shd;
NETWORK
TITLE =Indication "Underload shutdown, activation"

      U     #in_Reset;
      R     #out_Fail_Underl_SD;
      U     #out_Underload_Shd;
      S     #out_Fail_Underl_SD;
      NOP   0;
NETWORK
TITLE =Put the protection signals into the output
//The operation code "L DID nn" is depending on the local address in this FB of
//the static variables, beginning with "stat_Limit_I1", and has to be changed, if
//this local address changes.
      L     DID   52; //stat:Limit_I1...
      T     #out_PrtcEG_sign;

END_FUNCTION_BLOCK



DATA_BLOCK "GPrtct"
TITLE =
VERSION : 0.0

"fb_511_GenProtect"
BEGIN
   in_GEN_I_L1 := 0;
   in_GEN_I_L2 := 0;
   in_GEN_I_L3 := 0;
   in_GEN_P_SUM := 0;
   in_BUS_f := 0;
   in_BUS_U_L1L2 := 0;
   in_BUS_U_L2L3 := 0;
   in_BUS_U_L3L1 := 0;
   in_GEN_U_L1L2 := 0;
   in_GEN_U_L2L3 := 0;
   in_GEN_U_L3L1 := 0;
   in_Nmb_Generator := 0;
   in_act_mode := B#16#0;
   in_EG_Set := FALSE;
   in_EG_Harbour_Mode := FALSE;
   in_EG_PowerFb_Mode := FALSE;
   in_DI_Blackout := FALSE;
   in_DI_BusbarVolt := FALSE;
   in_DI_FireSpeedRelGenBrk := FALSE;
   in_DI_FB_GenBrk_On := FALSE;
   in_DI_Wind_Overtemp := FALSE;
   in_DiffProt_warn := FALSE;
   in_DiffProt_Trip := FALSE;
   in_Overc_ShortC_extern := FALSE;
   in_GENOP_ShortCircuit := FALSE;
   in_GENOP_OvCurr_trip := FALSE;
   in_GENOP_ReversePower := FALSE;
   in_GENOP_OvCurr_1_dly_1 := FALSE;
   in_GENOP_OvCurr_1_dly_2 := FALSE;
   in_GENOP_OvCurr_1_dly_3 := FALSE;
   in_GENOP_OvCurr_3 := FALSE;
   in_Rel_UnderlShd := FALSE;
   in_UnderShd_pos := FALSE;
   in_ShortCirc_OtherGen := FALSE;
   in_Reset := FALSE;
   in_p_uncond_reset := FALSE;
   out_Blackout := FALSE;
   out_BusVolt_avail := FALSE;
   out_GenVolt_avail := FALSE;
   out_StandbyStart := FALSE;
   out_Uness1_Off := FALSE;
   out_Uness2_Off := FALSE;
   out_Uness3_Off := FALSE;
   out_GenBrk_Off := FALSE;
   out_ShortCirc_OtherGen := FALSE;
   out_VoltContr_Off := FALSE;
   out_UndelayStop := FALSE;
   out_Blocking := FALSE;
   out_ChOver_Semi := FALSE;
   out_ChOver_Blackout := FALSE;
   out_Underload_Limit := FALSE;
   out_Underload_Shd := FALSE;
   out_Fail_Busbar := FALSE;
   out_Fail_Current := FALSE;
   out_Fail_Overcurr := FALSE;
   out_Fail_shortCirc := FALSE;
   out_Fail_RevPower := FALSE;
   out_Fail_overcurrent := FALSE;
   out_Fail_overload := FALSE;
   out_Fail_Underfrequ1 := FALSE;
   out_Fail_Underfrequ2 := FALSE;
   out_Fail_Underfrequ3 := FALSE;
   out_Fail_Overfrequ := FALSE;
   out_Fail_Undervolt1 := FALSE;
   out_Fail_Undervolt2 := FALSE;
   out_Fail_Overvolt1 := FALSE;
   out_Fail_Overvolt2 := FALSE;
   out_Fail_ShortCirc_Other := FALSE;
   out_Fail_DiffProt_Warn := FALSE;
   out_Fail_DiffProt_Trip := FALSE;
   out_Fail_Wind_Overtemp := FALSE;
   out_Fail_Underload := FALSE;
   out_Fail_Underl_SD := FALSE;
   out_Spare_1 := FALSE;
   out_Spare_2 := FALSE;
   out_PrtcEG_sign := DW#16#0;
   stat_GEN_I_Min := 0;
   stat_GEN_I_Max := 0;
   stat_GEN_I_Mean := 0;
   stat_BUS_U_Min := 0;
   stat_BUS_U_Max := 0;
   stat_GEN_U_Min := 0;
   stat_GEN_U_Max := 0;
   stat_Limit_I1 := FALSE;
   stat_Limit_I2 := FALSE;
   stat_Limit_I3 := FALSE;
   stat_Limit_I4 := FALSE;
   stat_Limit_I5 := FALSE;
   stat_Limit_I6 := FALSE;
   stat_Limit_I7 := FALSE;
   stat_Limit_P1 := FALSE;
   stat_Limit_P2 := FALSE;
   stat_Limit_P3 := FALSE;
   stat_Limit_P4 := FALSE;
   stat_Limit_P5 := FALSE;
   stat_Limit_P6 := FALSE;
   stat_Limit_P7 := FALSE;
   stat_Limit_f1 := FALSE;
   stat_Limit_f2 := FALSE;
   stat_Limit_f3 := FALSE;
   stat_Limit_f4 := FALSE;
   stat_Limit_f5 := FALSE;
   stat_Limit_f6 := FALSE;
   stat_Limit_f7 := FALSE;
   stat_Limit_f8 := FALSE;
   stat_Limit_U1 := FALSE;
   stat_Limit_U2 := FALSE;
   stat_Limit_U3 := FALSE;
   stat_Limit_U4 := FALSE;
   stat_Limit_P7_undel := FALSE;
   stat_Limit_P7_Warn := FALSE;
   stat_ShortCircuit := FALSE;
   stat_Wind_Overtemp := FALSE;
   stat_Standby_ProtWarn := FALSE;
   stat_Uness1_TransfLBrk := FALSE;
   stat_ShC_OtherSet_Aux := FALSE;
   stat_ShC_OtherSet_Pulse := FALSE;
   stat_ShC_OtherSet1 := FALSE;
   stat_ShC_OtherSet2 := FALSE;
   stat_ShC_OtherSet_Reset := FALSE;
   stat_Block_ShC_OtherSet := FALSE;
   stat_DiffProt_Trip := FALSE;
   stat_Trip_Overcurrent := FALSE;
   stat_Trip_RevPower := FALSE;
   stat_Trip_Underfrequ := FALSE;
   stat_Trip_Undervoltage := FALSE;
   stat_Uness2_Uness1 := FALSE;
   stat_Uness3_Uness2 := FALSE;
   stat_GenRunning := FALSE;
   stat_Harb_Feedb_Mode := FALSE;
   stat_GENOP_StandbySt := FALSE;
   stat_FC56_Limit_01 := FALSE;
   stat_FC56_Limit_02 := FALSE;
   stat_FC56_Limit_03 := FALSE;
   stat_FC56_Limit_04 := FALSE;
   stat_FC56_Limit_05 := FALSE;
   stat_FC56_Limit_06 := FALSE;
   stat_FC56_Limit_07 := FALSE;
   stat_FC56_Limit_08 := FALSE;
   stat_FC56_Limit_09 := FALSE;
   stat_FC56_Limit_10 := FALSE;
   stat_FC56_Limit_11 := FALSE;
   stat_FC56_Limit_12 := FALSE;
   stat_FC56_Limit_13 := FALSE;
   stat_FC56_Limit_131 := FALSE;
   stat_FC56_Limit_14 := FALSE;
   stat_FC56_Limit_15 := FALSE;
   stat_FC56_Limit_16 := FALSE;
   stat_FC56_Limit_17 := FALSE;
   stat_FC56_Limit_18 := FALSE;
   stat_FC56_Limit_19 := FALSE;
   stat_FC56_Limit_20 := FALSE;
   stat_FC56_Limit_21 := FALSE;
   stat_FC56_Limit_22 := FALSE;
   stat_FC56_Limit_23 := FALSE;
   stat_FC56_Limit_24 := FALSE;
   stat_FC56_Limit_25 := FALSE;
   stat_Underload := FALSE;
   stat_UndelayStop := FALSE;
   stat_Trip_Temp_Overcurr := FALSE;
END_DATA_BLOCK

FUNCTION_BLOCK "fb_57_clseopnBrk"
TITLE =Control of generator breaker
//version!date    !author !change_segm!change_description
//-------+--------+-------+-----------+-------------------------------
// 1.2   !07.04.00!Bauch  ! ---       ! last vaild version
// 1.3   !10.05.00!Kahle  ! 11        ! signal "temp_auto" of the conn. deleted
//       !        !       ! 30        ! signal "change over via blackout" changed
//       !        !       ! 45        ! add.signal "feedback breaker off"
//       !        !       ! 12        ! Ready-signal doesn't store
// 1.4   !11.07.00!Kahle  ! 13        ! add.signal "#out_Fail_SynTime"
// 1.5   !13.07.00!Kahle  ! 44,45     ! add.signal "blocked trip signal"
// 1.6   !20.10.00!Kahle  ! 13        ! PB open interrupt close process
// 1.7   !13.01.01!Bauch  ! 45 new    ! Time delay Gen. breaker Off commands
//       !        !       ! 46        ! Input for pushbutton "Gen. breaker OFF"
//       !        !       !           ! (in manual/local mode) added
//       !        !       ! 44,46     ! Comments
// 1.8   !08.03.01!Kahle  ! 8         ! Breaker ready for close also in test pos.
//       !        !       ! 19        ! add.signal "#in_reset_synchron"
//       !        !       ! 44,46     ! Alarm'Brk trip' if no ext.block.active
// 1.9   !02.01.02!Kahle  ! 40->38    ! delayStp: same conditions as standbyStrt
AUTHOR : Bauch
FAMILY : PMA71
NAME : BrkContr
VERSION : 1.9


VAR_INPUT
  in_DGLoad_off : BOOL ;	//Generator actual load less than DG off load
  in_Nmb_Gen_LoadSh : INT ;	//Number of other generators, taking part in loadsharing
  in_act_mode : BYTE ;	//Active operation mode
  in_EG_Set : BOOL ;	//Generator set is an Emergency generator
  in_Blackout : BOOL ;	//Blackout
  in_SimLock_Blocked : BOOL ;	//Signal from simultaneous locking: Blocked (no request possible)
  in_SimLock_Fault : BOOL ;	//Signal from simultaneous locking: Fault (reset of request)
  in_SimLock_Release : BOOL ;	//Signal from simultaneous locking: Release for generator breaker closing
  in_DGWG_run : BOOL ;	//Diesel/shaft generator is running
  in_DGWG_Stop : BOOL ;	//Stop command for diesel/shaft generator activated
  in_GenBrkOff_LoadRed : BOOL ;	//Generator breaker Off after load reduction (Off after P < Limit)
  in_DGWG_GenBrk_Cmd_Off : BOOL ;	//Generator breaker Off command from DG/WG (without previous load reduction)
  in_DGWG_GenBrk_Cmd_Trip : BOOL ;	//Generator breaker trip command
  in_ChOver_Blackout : BOOL ;	//Change over to new started set via blackout (no synchronizing)
  in_Standby_ReadyConn : BOOL ;	//New started standby set ready for connecting
  in_ShoreConn_Off : BOOL ;	//All shore connections are Off
  in_DI_GenBrk_ReadyClose : BOOL ;	//Generator breaker is ready for closing
  in_DI_GenBrk_Tripped : BOOL ;	//Generator breaker is tripped
  in_DI_GenBrk_PosNorm : BOOL ;	//Generator breaker is in normal (operating) position
  in_DI_GenBrk_PosTest : BOOL ;	//Generator breaker is in test position
  in_DI_GenBrk_FB_On : BOOL ;	//Feedback signal generator breaker is ON
  in_DI_GenBrk_FB_Off : BOOL ;	//Feedback signal generator breaker is OFF
  in_GENOP_SynCmd_On : BOOL ;	//On command from GENOP71 to generator breaker (for check of breaker closing)
  in_GenBrk_Ext_Release : BOOL ;	//External release for generator breaker closing (DG/SG running, gen. volt., etc)
  in_ext_DG_block : BOOL ;	//External DG blocking is activated
  in_EG_GB_Close : BOOL ;	//Generator breaker closing command from FB92 (EG)
  in_EG_Cmd_Synchr_On : BOOL ;	//Emergency generator synchronizing On command (in harbour mode)
  in_EG_GB_Open : BOOL ;	//Generator breaker opening command from FB92 (EG)
  in_PB_GenBrk_Close : BOOL ;	//Command from PB "GB close" (in semi automatic mode, OP or MMI)
  in_PB_GenBrk_Open : BOOL ;	//Command from PB "GB open" (in semi automatic mode, OP or MMI)
  in_PB_GenBrk_Open_Man : BOOL ;	//Command from PB "GB open" (in Manual/local mode)
  in_reset_synchron : BOOL ;	//Reset synchronizing process
  in_Reset : BOOL ;	//Reset
  in_power_avail : BOOL ;
END_VAR
VAR_OUTPUT
  out_Operat_Status : INT ;	//Actual operational status (as number)
  out_StandbyStart : BOOL ;	//Request of standby start
  out_SimLock_Request : BOOL ;	//Signal to simultaneous locking: Request for breaker closing
  out_DO_GenBrk_Cmd_Off : BOOL ;	//Digital output: Generator breaker OFF command
  out_GENOP_GenBrk_Cmd_On : BOOL ;	//Signal to GENOP71: Generator breaker ON command
  out_GENOP_GenBrk_Cmd_Off : BOOL ;	//Signal to GENOP71: Generator breaker OFF command
  out_GENOP_SynchRelease : BOOL ;	//Signal to GENOP71: Synchronizing release
  out_GenBrk_Ready : BOOL ;	//Generator breaker ready
  out_GenBrk_Ready_Standby : BOOL ;	//Generator breaker ready for standby
  out_GenBrk_Ready_Close : BOOL ;	//Generator breaker ready for closing
  out_Brk_Closed_Plausib : BOOL ;	//Generator breaker closed (plausibility controlled)
  out_UndelayStop : BOOL ;	//Undelayed stop command
  out_DelayStop : BOOL ;	//Delayed stop command
  out_LoadReduction : BOOL ;	//Load reduction command to frequency/load controller
  out_Blocking : BOOL ;	//Blocking of generator set
  out_ChOver_Semi : BOOL ;	//Forced change over from automatic to semi automatic mode
  out_Fail_Ready : BOOL ;	//Failure: Signal generator breaker ready missing
  out_Fail_FeedbOn : BOOL ;	//Failure: Feedback signal "Generator breaker ON" missing
  out_Fail_FeedbOff : BOOL ;	//Failure: Feedback signal "Generator breaker OFF" missing
  out_Fail_FeedbOffOn : BOOL ;	//Failure: No plausibility of feedback signals "Generator breaker OFF/ON"
  out_Fail_BrkTrip : BOOL ;	//Failure: Generator breaker tripped
  out_Fail_SynTime : BOOL ;	//Failure: Synchronizing time exceeded
  out_Fail_GenFailure : BOOL ;	//Failure: General failure
  out_Fail_ShoreC_GenBrk : BOOL ;	//Alarm: Shore connection blocks generator breaker
  out_Fail_ChgViaBlack : BOOL ;	//Alarm: generator set change over via blackout
END_VAR
VAR
  stat_CntValue01 : INT ;	//Memory for FC100 (timer/counter) No. 01 (Gen. breaker not ready)
  stat_CntValue02 : INT ;	//Memory for FC100 (timer/counter) No. 02 (GenBrk On after sim lock)
  stat_CntValue03 : INT ;	//Memory for FC100 (timer/counter) No. 03 (simult. lock request)
  stat_CntValue04 : INT ;	//Memory for FC100 (timer/counter) No. 04 (Synchronizing time)
  stat_CntValue05 : INT ;	//Memory for FC100 (timer/counter) No. 05 (Time for load reduction)
  stat_CntValue06 : INT ;	//Memory for FC100 (timer/counter) No. 06 (p_TGenBrkTrip)
  stat_CntValue07 : INT ;	//Memory for FC100 (timer/counter) No. 07 (Pulse gen. breaker On comm.)
  stat_CntValue08 : INT ;	//Memory for FC100 (timer/counter) No. 08 (Pulse gen. breaker Off comm.)
  stat_CntValue09 : INT ;	//Memory for FC100 (timer/counter) No. 09 (Gen. breaker feedback On)
  stat_CntValue10 : INT ;	//Memory for FC100 (timer/counter) No. 10 (Gen. breaker feedback Off)
  stat_CntValue11 : INT ;	//Memory for FC100 (timer/counter) No. 11 (Plausibility feedback GB On/Off)
  stat_CntValue12 : INT ;	//Memory for FC100 (timer/counter) No. 12 (Pulse gen. breaker Trip comm.)
  stat_CntValue13 : INT ;	//Memory for FC100 (timer/counter) No. 13 (Time delay gen. breaker Off)
  stat_CntValue14 : INT ;	//Memory for FC100 (timer/counter) No. 14 (Time delay gen. breaker Off command)
  stat_CntStart01 : BOOL ;	//Memory for FC100 (timer/counter) No. 01
  stat_CntStarted01 : BOOL ;	//Memory for FC100 (timer/counter) No. 01
  stat_CntStart02 : BOOL ;	//Memory for FC100 (timer/counter) No. 02
  stat_CntStarted02 : BOOL ;	//Memory for FC100 (timer/counter) No. 02
  stat_CntStart03 : BOOL ;	//Memory for FC100 (timer/counter) No. 03
  stat_CntStarted03 : BOOL ;	//Memory for FC100 (timer/counter) No. 03
  stat_CntStart04 : BOOL ;	//Memory for FC100 (timer/counter) No. 04
  stat_CntStarted04 : BOOL ;	//Memory for FC100 (timer/counter) No. 04
  stat_CntStart05 : BOOL ;	//Memory for FC100 (timer/counter) No. 05
  stat_CntStarted05 : BOOL ;	//Memory for FC100 (timer/counter) No. 05
  stat_CntStart06 : BOOL ;	//Memory for FC100 (timer/counter) No. 06
  stat_CntStarted06 : BOOL ;	//Memory for FC100 (timer/counter) No. 06
  stat_CntStart07 : BOOL ;	//Memory for FC100 (timer/counter) No. 07
  stat_CntStarted07 : BOOL ;	//Memory for FC100 (timer/counter) No. 07
  stat_CntStart08 : BOOL ;	//Memory for FC100 (timer/counter) No. 08
  stat_CntStarted08 : BOOL ;	//Memory for FC100 (timer/counter) No. 08
  stat_CntStart09 : BOOL ;	//Memory for FC100 (timer/counter) No. 09
  stat_CntStarted09 : BOOL ;	//Memory for FC100 (timer/counter) No. 09
  stat_CntStart10 : BOOL ;	//Memory for FC100 (timer/counter) No. 10
  stat_CntStarted10 : BOOL ;	//Memory for FC100 (timer/counter) No. 10
  stat_CntStart11 : BOOL ;	//Memory for FC100 (timer/counter) No. 11
  stat_CntStarted11 : BOOL ;	//Memory for FC100 (timer/counter) No. 11
  stat_CntStart12 : BOOL ;	//Memory for FC100 (timer/counter) No. 12
  stat_CntStarted12 : BOOL ;	//Memory for FC100 (timer/counter) No. 12
  stat_CntStart13 : BOOL ;	//Memory for FC100 (timer/counter) No. 13
  stat_CntStarted13 : BOOL ;	//Memory for FC100 (timer/counter) No. 13
  stat_CntStart14 : BOOL ;	//Memory for FC100 (timer/counter) No. 14
  stat_CntStarted14 : BOOL ;	//Memory for FC100 (timer/counter) No. 14
  stat_BrkReady_TimeEx : BOOL ;	//Time expired for generator breaker not ready
  stat_BrkClose_Semi : BOOL ;	//Request for gen. breaker closing in semi automatic
  stat_BrkOn_Sim : BOOL ;	//Release from simultaneous locking for generator breaker closing (delayed)
  stat_SynchOn_Pulse : BOOL ;	//Auxiliary (pulse) flag for synchronizing
  stat_SynchOn_EG_PAux : BOOL ;	//Auxiliary (pulse) flag for synchronizing in EG harbour mode
  stat_SynchOn : BOOL ;	//Synchronizing start in auto/semiautomatic mode
  stat_Synch_TimeEx : BOOL ;	//Time expired for synchronizing of generator breaker
  stat_GenBrk_Off_NoLoadR : BOOL ;	//Generator breaker Off without load reduction
  stat_GenBrk_Off_LoadRed : BOOL ;	//Generator breaker Off with load reduction
  stat_LoadRed_TimeEx : BOOL ;	//Time expired for generator breaker Off after load reduction
  stat_GenBrkOff_Limit : BOOL ;	//Generator breaker Off command after load < limit
  stat_GenBrkOff_StbyReady : BOOL ;	//Generator breaker Off command after standby set is ready for connecting
  stat_FeedbOn_TimeSt : BOOL ;	//Time started for feedback signal generator breaker ON
  stat_FeedbOn_TimeEx : BOOL ;	//Time expired for feedback signal generator breaker ON
  stat_FeedbOff_TimeSt : BOOL ;	//Time started for feedback signal generator breaker OFF
  stat_FeedbOff_TimeEx : BOOL ;	//Time expired for feedback signal generator breaker OFF
  stat_GenBrk_DelayOff : BOOL ;	//Time delay generator breaker OFF
  stat_PulseAux_Trip : BOOL ;	//Auxiliary flag for pulse "Gen. breaker tripped"
  stat_Fail_GenBrk : BOOL ;	//Failure: Generator breaker control general failure
  stat_Fail_ShoreC : BOOL ;	//Failure: Generator breaker blocked by shore connection
  stat_synchron : BOOL ;
  stat_Fail_GenBrk_TripExt : BOOL ;	//Failure: Generator breaker tripped from external
  stat_PulseAux_GenBrk_Off : BOOL ;	//Auxiliary flag for pulse "Gen. breaker is Off"
  stat_Fail_GenBrk_TripNoR : BOOL ;	//Failure: Generator breaker tripped, no reason detected (No Off command)
  stat_GENOP_GenBrk_CmdOff : BOOL ;	//Signal to GENOP71: Generator breaker OFF command
  stat_power_avail : BOOL ;
END_VAR
VAR_TEMP
  temp_OM_Local : BOOL ;	//Active operation mode: Local
  temp_OM_Semi_OP : BOOL ;	//Active operation mode: Semi automatic OP
  temp_OM_Auto_OP : BOOL ;	//Active operation mode: Auto OP
  temp_OM_Semi_MMI : BOOL ;	//Active operation mode: Semi automatic MMI
  temp_OM_Auto_MMI : BOOL ;	//Active operation mode: Auto MMI
  temp_OM_Test : BOOL ;	//Active operation mode: Test (EG only)
  temp_Reserve_006 : BOOL ;	//Reserved (Transfer Byte --> Bit)
  temp_Reserve_007 : BOOL ;	//Reserved (Transfer Byte --> Bit)
  temp_Auto : BOOL ;	//Active operation mode: Automatic
  temp_Semi : BOOL ;	//Active operation mode: Semi automatic
  temp_ScratchFlag : BOOL ;	//Scratch flag
  temp_DI_GenBrk_ReadyClos : BOOL ;	//Generator breaker is ready for closing (DI or parameter)
  temp_DI_GenBrk_PosNorm : BOOL ;	//Generator breaker is in normal position (DI or parameter)
  temp_DI_GenBrk_PosTest : BOOL ;	//Generator breaker is in test position (DI or parameter)
  temp_GenBrk_ShoreConn_Bl : BOOL ;	//Generator breaker blocked by shore connection
  temp_simLockReleased : BOOL ;	//Simultaneous lock is released
  temp_LoadReduction : BOOL ;	//Load reduction command to frequency/load controller
  temp_Indication_44 : BOOL ;	//Indication no. 44
  temp_synchron : BOOL ;
  temp_power_avail : BOOL ;
  temp_Indication_45 : BOOL ;	//Indication no. 45
  temp_GenBrkOff_StbyReady : BOOL ;	//Generator breaker Off command after standby set is ready for connecting
  temp_GenBrkOffCmd_Delay : BOOL ;	//Generator breaker Off command OFF delayed (inverted)
END_VAR
BEGIN
NETWORK
TITLE =Active operation mode (Transfer Byte --> Bit)
//This transfer function is relaying on the relative addresses of the "temp"
//variables "temp_OM_Local" ... "temp_OM_Auto" in the area from 0.0 ... 0.7.
      L     #in_act_mode;
      T     LB     0;
NETWORK
TITLE =Operation mode: Automatic
//Some functions of the generator breaker control (breaker closing in case of
//blackout) are working only, if the system is in automatic mode and if
//there is no failure. After reset of the failures, the functions are starting
//again, as long as the system is in automatic mode.
      O     #temp_OM_Auto_OP;
      O     #temp_OM_Auto_MMI;
      =     #temp_Auto;
NETWORK
TITLE =Operation mode: Semi automatic

      O     #temp_OM_Semi_OP;
      O     #temp_OM_Semi_MMI;
      =     #temp_Semi;
NETWORK
TITLE =Generator breaker is ready for closing (DI or parameter)
//If there is no signal "Generator breaker ready for closing" available, the
//parameter "p_Monit_BrkReady" is to be set to "0".
      O     #in_DI_GenBrk_ReadyClose;
      ON    "prm_pma".p_Monit_BrkReady;
      =     #temp_DI_GenBrk_ReadyClos;
NETWORK
TITLE =Generator breaker is in normal position (DI or parameter)
//If there is no signal "Generator breaker in normal position" available, the
//parameter "p_Monit_BrkPosNorm" is to be set to "0".
      O     #in_DI_GenBrk_PosNorm;
      ON    "prm_pma".P_Monit_BrkPosNorm;
      =     #temp_DI_GenBrk_PosNorm;
NETWORK
TITLE =Generator breaker is in test position (DI or parameter)
//If there is no signal "Generator breaker in normal position" available, the
//parameter "p_Monit_BrkPosNorm" is to be set to "0".
      O     #in_DI_GenBrk_PosTest;
      ON    "prm_pma".p_Monit_BrkPosTest;
      =     #temp_DI_GenBrk_PosTest;
NETWORK
TITLE =Generator breaker blocked by shore connection (DI or parameter)
//If there is no signal "Generator breaker in normal position" available, the
//parameter "p_Monit_BrkPosNorm" is to be set to "0".
      UN    #in_ShoreConn_Off;
      U     "prm_pma".p_GenBrk_ShoreBlock;
      =     #temp_GenBrk_ShoreConn_Bl;
NETWORK
TITLE =Generator breaker ready

      U(    ;
      O     #temp_DI_GenBrk_PosNorm;
      O     #temp_DI_GenBrk_PosTest;
      )     ;
      U     #temp_DI_GenBrk_ReadyClos;
      UN    #stat_Fail_GenBrk;
      =     #out_GenBrk_Ready;
NETWORK
TITLE =Generator breaker ready for "standby set function"
//These conditions of the generator breaker control are necessary for a generator
//set to be selected as a "standby set". As the generator voltage from the
//running
//generator is necessary for charging the spring energy store of the generator
//breaker, the signal "Generator breaker ready for closing" is not included here.
      U     #temp_DI_GenBrk_PosNorm;
      UN    #stat_Fail_GenBrk;
      U     #in_DI_GenBrk_FB_Off;
      =     #out_GenBrk_Ready_Standby;
NETWORK
TITLE =Generator breaker ready for closing

      U(    ;
      O     #temp_DI_GenBrk_PosNorm;
      O     #temp_DI_GenBrk_PosTest;
      )     ;
      U     #temp_DI_GenBrk_ReadyClos;
      UN    #stat_Fail_GenBrk;
      U     #in_DI_GenBrk_FB_Off;
      U     #in_GenBrk_Ext_Release;
      UN    #in_GenBrkOff_LoadRed;
      =     L      3.0;
      BLD   103;
      U     "true";
      SPBNB _001;
      CALL "fc_h1_CntState16" (
           CntTyp                   := 'D',
           CntStart                 := L      3.0,
           CntValue                 := "sys_freeCnt16_100ms",
           CntOffset                := "prm_pma".p_TgenBrkRel,
           CntRun                   := #out_GenBrk_Ready_Close,
           puls_CntStart            := #stat_CntStart03,
           Cnt_started              := #stat_CntStarted03,
           mem_CntValue             := #stat_CntValue03);
_001: NOP   0;
NETWORK
TITLE =Waiting time for failure signal "Gen. breaker not ready"
//The signal "Generator breaker ready" is expected a short time after run-up of
//the diesel engine.
      U     #in_GenBrk_Ext_Release;
      UN    #in_DI_GenBrk_FB_On;
      UN    #out_GENOP_GenBrk_Cmd_Off;
      UN    #temp_DI_GenBrk_ReadyClos;
      =     L      3.0;
      BLD   103;
      U     "true";
      SPBNB _002;
      CALL "fc_h1_CntState16" (
           CntTyp                   := 'D',
           CntStart                 := L      3.0,
           CntValue                 := "sys_freeCnt16_100ms",
           CntOffset                := "prm_pma".p_TgenBrkReady,
           CntRun                   := #stat_BrkReady_TimeEx,
           puls_CntStart            := #stat_CntStart01,
           Cnt_started              := #stat_CntStarted01,
           mem_CntValue             := #stat_CntValue01);
_002: NOP   0;
NETWORK
TITLE =Generator breaker signal "ready for closing" is missing

      U     #stat_BrkReady_TimeEx;
      =     #out_Fail_Ready;
NETWORK
TITLE =To simultaneous locking: Request for breaker closing
//In automatic mode, black-out and after run-up of the diesel generator a request
//for generator breaker closing to the simultaneous locking is given.
//
//In semiautomatic mode, black-out and after run-up of the diesel generator a
//request for generator breaker closing to the simultaneous locking is given,
//when
//the PBs "GB close" and "CONFIRM" are operated.
//
//A request signal is possible only, when the simultaneous locking itself does
//not
//give a blocking signal.
//
//After the other sets are blocked, the simultaneous locking gives a release
//signal to this FB. With this release signal this FB will close the generator
//breaker. If there is something wrong or if the monitoring time has expired, the
//simultaneous locking will give a failure signal. With this signal this FB will
//take back the request signal.
//
//The selection, which diesel generators (1 or 2 possible) are to be started in
//case of blackout, is made in FB53. The first DG, which is ready for generator
//breaker closing, will try to get the release from the simultaneous locking.
      O(    ;
      U     #in_PB_GenBrk_Close;
      S     #stat_BrkClose_Semi;
      U(    ;
      ON    #temp_Semi;
      O     #in_EG_Set;
      ON    #out_GenBrk_Ready_Close;
      O     #in_SimLock_Blocked;
      O     #in_SimLock_Fault;
      O     #out_Fail_SynTime;
      O     #temp_GenBrk_ShoreConn_Bl;
      O     #in_PB_GenBrk_Open;
      )     ;
      R     #stat_BrkClose_Semi;
      U     #stat_BrkClose_Semi;
      )     ;
      O     ;
      UN    #in_EG_Set;
      U     #temp_Auto;
      U     #out_GenBrk_Ready_Close;
      UN    #in_SimLock_Blocked;
      UN    #in_SimLock_Fault;
      UN    #temp_GenBrk_ShoreConn_Bl;
      =     #out_SimLock_Request;
NETWORK
TITLE =Indication: Shore connection blocks generator breaker

      U(    ;
      U     #temp_Semi;
      U     #in_PB_GenBrk_Close;
      O     #temp_Auto;
      O     #in_EG_Set;
      )     ;
      U     #out_GenBrk_Ready_Close;
      UN    #in_SimLock_Blocked;
      UN    #in_SimLock_Fault;
      U     #temp_GenBrk_ShoreConn_Bl;
      S     #stat_Fail_ShoreC;
      U     #in_Reset;
      R     #stat_Fail_ShoreC;
      U     #stat_Fail_ShoreC;
      =     #out_Fail_ShoreC_GenBrk;
NETWORK
TITLE =Simultaneous lock release received

      U     #out_SimLock_Request;
      U     #in_SimLock_Release;
      =     #temp_simLockReleased;
NETWORK
TITLE =Delay time between sim lock release and gen. breaker closing
//in case of blackout
      U     #temp_simLockReleased;
      U     #in_Blackout;
      =     L      3.0;
      BLD   103;
      U     "true";
      SPBNB _003;
      CALL "fc_h1_CntState16" (
           CntTyp                   := 'D',
           CntStart                 := L      3.0,
           CntValue                 := "sys_freeCnt16_100ms",
           CntOffset                := "prm_pma".p_TgenBrkSimOn,
           CntRun                   := #stat_BrkOn_Sim,
           puls_CntStart            := #stat_CntStart02,
           Cnt_started              := #stat_CntStarted02,
           mem_CntValue             := #stat_CntValue02);
_003: NOP   0;
NETWORK
TITLE =Signal to GENOP71: Generator breaker ON command (Pulse)

      U(    ;
      O     #stat_BrkOn_Sim;
      O     ;
      U     #in_EG_GB_Close;
      U     #in_EG_Set;
      U     #out_GenBrk_Ready_Close;
      )     ;
      =     L      3.0;
      BLD   103;
      U     "true";
      SPBNB _01a;
      CALL "fc_h1_CntState16" (
           CntTyp                   := 'P',
           CntStart                 := L      3.0,
           CntValue                 := "sys_freeCnt16_100ms",
           CntOffset                := "prm_pma".p_TgenBrkOn,
           CntRun                   := #out_GENOP_GenBrk_Cmd_On,
           puls_CntStart            := #stat_CntStart07,
           Cnt_started              := #stat_CntStarted07,
           mem_CntValue             := #stat_CntValue07);
_01a: NOP   0;
NETWORK
TITLE =Synchronizing On command (pulse)
//The "Synchronizing On" command from the OP or MMI is already combined with semi
//automatic mode in another part of the program.
      U     #temp_simLockReleased;
      UN    #in_Blackout;
      FP    #stat_SynchOn_Pulse;
      O(    ;
      U     #in_EG_Cmd_Synchr_On;
      U     #in_EG_Set;
      U     #out_GenBrk_Ready_Close;
      FP    #stat_SynchOn_EG_PAux;
      )     ;
      =     #stat_SynchOn;
NETWORK
TITLE =Signal to GENOP71: Release of Synchronizing
//If there is no blackout --> closing of generator breaker with synchronizing.
//If there is blackout --> closing of generator breaker with simultaneous
//locking.
      U     #stat_SynchOn;
      S     #stat_synchron;
      U(    ;
      ON    #in_DGWG_run;
      O     #in_Blackout;
      O     #in_GENOP_SynCmd_On;
      O     #in_DI_GenBrk_FB_On;
      ON    #in_DI_GenBrk_FB_Off;
      O     #out_Fail_SynTime;
      O     ;
      UN    #temp_Auto;
      UN    #temp_Semi;
      O     ;
      U     #temp_Semi;
      U     #in_PB_GenBrk_Open;
      O     #in_reset_synchron;
      )     ;
      R     #stat_synchron;
      NOP   0;
NETWORK
TITLE =no frequency adjusting

      U     #stat_synchron;
      =     #out_GENOP_SynchRelease;
NETWORK
TITLE =Monitoring time for synchronizing

      U     #stat_synchron;
      UN    #in_GENOP_SynCmd_On;
      UN    #in_DI_GenBrk_FB_On;
      =     L      3.0;
      BLD   103;
      U     "true";
      SPBNB _01b;
      CALL "fc_h1_CntState16" (
           CntTyp                   := 'D',
           CntStart                 := L      3.0,
           CntValue                 := "sys_freeCnt16_100ms",
           CntOffset                := "prm_pma".P_TgenBrkSyn,
           CntRun                   := #stat_Synch_TimeEx,
           puls_CntStart            := #stat_CntStart04,
           Cnt_started              := #stat_CntStarted04,
           mem_CntValue             := #stat_CntValue04);
_01b: NOP   0;
NETWORK
TITLE =Failure: Synchronizing time exceeded

      U     #in_Reset;
      R     #out_Fail_SynTime;
      U     #stat_Synch_TimeEx;
      UN    #out_Fail_FeedbOn;
      S     #out_Fail_SynTime;
      NOP   0;
NETWORK
TITLE =Generator breaker closed (plausibility controlled)

      U     #in_DI_GenBrk_FB_On;
      UN    #in_DI_GenBrk_FB_Off;
      =     #out_Brk_Closed_Plausib;
NETWORK
TITLE =Generator breaker feedback signal after ON command missing
//The "ON" command, which is given from the synchronizer (GENOP71) directly to
//the
//generator breaker, when the conditions for closing are met, is signalised also
//to this FB ("#in_GenBrk_Cmd_OnSyn"). If the feedback signal "Generator breaker
//closed" does not come, this is a failure of the generator breaker and not of
//the
//synchronizing.
      U     #in_Reset;
      R     #out_Fail_FeedbOn;
      U(    ;
      U(    ;
      O     #out_GENOP_GenBrk_Cmd_On;
      O     #in_GENOP_SynCmd_On;
      )     ;
      S     #stat_FeedbOn_TimeSt;
      U(    ;
      O     #in_DI_GenBrk_FB_On;
      O     #in_Reset;
      )     ;
      R     #stat_FeedbOn_TimeSt;
      U     #stat_FeedbOn_TimeSt;
      )     ;
      U     #stat_FeedbOn_TimeEx;
      S     #out_Fail_FeedbOn;
      NOP   0;
NETWORK
TITLE =Monitoring time for feedback signal after ON command

      U     #stat_FeedbOn_TimeSt;
      =     L      3.0;
      BLD   103;
      U     "true";
      SPBNB _01c;
      CALL "fc_h1_CntState16" (
           CntTyp                   := 'D',
           CntStart                 := L      3.0,
           CntValue                 := "sys_freeCnt16_100ms",
           CntOffset                := "prm_pma".p_TgenBrkFbOn,
           CntRun                   := #stat_FeedbOn_TimeEx,
           puls_CntStart            := #stat_CntStart09,
           Cnt_started              := #stat_CntStarted09,
           mem_CntValue             := #stat_CntValue09);
_01c: NOP   0;
NETWORK
TITLE =Gen. breaker Off without load reduction

      U(    ;
      U(    ;
      O(    ;
      L     #in_Nmb_Gen_LoadSh;
      L     1;
      <I    ;
      )     ;
      ON    "prm_pma".p_GenBrk_LoadRed;
      )     ;
      U     #temp_Semi;
      U     #in_PB_GenBrk_Open;
      U     #in_DI_GenBrk_FB_On;
      O     #in_DGWG_GenBrk_Cmd_Off;
      )     ;
      S     #stat_GenBrk_Off_NoLoadR;
      U(    ;
      ON    #in_DI_GenBrk_FB_On;
      O     #in_DI_GenBrk_FB_Off;
      O     #out_Fail_FeedbOff;
      )     ;
      R     #stat_GenBrk_Off_NoLoadR;
      NOP   0;
NETWORK
TITLE =Gen. breaker Off with load reduction

      O(    ;
      U     #temp_Semi;
      U     #in_PB_GenBrk_Open;
      U     "prm_pma".p_GenBrk_LoadRed;
      U     #in_DI_GenBrk_FB_On;
      S     #stat_GenBrk_Off_LoadRed;
      U(    ;
      ON    #in_DI_GenBrk_FB_On;
      O     #in_DI_GenBrk_FB_Off;
      O     #out_Fail_FeedbOff;
      O     #stat_GenBrk_Off_NoLoadR;
      O     #in_EG_Set;
      )     ;
      R     #stat_GenBrk_Off_LoadRed;
      U     #stat_GenBrk_Off_LoadRed;
      )     ;
      O     ;
      U     #in_GenBrkOff_LoadRed;
      U     #in_DI_GenBrk_FB_On;
      UN    #in_DI_GenBrk_FB_Off;
      UN    #out_Fail_FeedbOff;
      UN    #in_EG_Set;
      =     #temp_LoadReduction;
      =     #out_LoadReduction;
NETWORK
TITLE =Monitoring time for gen. breaker Off after load reduction
//If the load reduction did not work, the generator breaker will be opened
//without load reduction.
      U     #temp_LoadReduction;
      =     L      3.0;
      BLD   103;
      U     "true";
      SPBNB _01d;
      CALL "fc_h1_CntState16" (
           CntTyp                   := 'D',
           CntStart                 := L      3.0,
           CntValue                 := "sys_freeCnt16_100ms",
           CntOffset                := "prm_pma".p_TgenBrkLoadOff,
           CntRun                   := #stat_LoadRed_TimeEx,
           puls_CntStart            := #stat_CntStart05,
           Cnt_started              := #stat_CntStarted05,
           mem_CntValue             := #stat_CntValue05);
_01d: NOP   0;
NETWORK
TITLE =Breaker Off after P < Limit

      U     #in_DGLoad_off;
      U     #temp_LoadReduction;
      =     #stat_GenBrkOff_Limit;
NETWORK
TITLE =Generator breaker Off command after standby set is ready
//Changeover via blackout
      U     #in_ChOver_Blackout;
      U     #in_Standby_ReadyConn;
      UN    #in_DI_GenBrk_FB_Off;
      UN    #in_EG_Set;
      U     #temp_Auto;
      =     L      3.0;
      U     L      3.0;
      BLD   102;
      =     #temp_GenBrkOff_StbyReady;
      U     L      3.0;
      S     #stat_GenBrkOff_StbyReady;
      U     #in_Reset;
      R     #stat_GenBrkOff_StbyReady;
      U     #stat_GenBrkOff_StbyReady;
      =     #out_Fail_ChgViaBlack;
NETWORK
TITLE =

      U     #in_power_avail;
      BLD   100;
      FP    #stat_power_avail;
      =     #temp_power_avail;
NETWORK
TITLE =Generator breaker trip command

      U     #in_DGWG_GenBrk_Cmd_Trip;
      =     L      3.0;
      BLD   103;
      U     "true";
      SPBNB _01e;
      CALL "fc_h1_CntState16" (
           CntTyp                   := 'P',
           CntStart                 := L      3.0,
           CntValue                 := "sys_freeCnt16_100ms",
           CntOffset                := "prm_pma".p_TgenBrkOff,
           CntRun                   := #stat_GENOP_GenBrk_CmdOff,
           puls_CntStart            := #stat_CntStart12,
           Cnt_started              := #stat_CntStarted12,
           mem_CntValue             := #stat_CntValue12);
_01e: NOP   0;
NETWORK
TITLE =Generator breaker OFF command (digital output)

      U(    ;
      O     #temp_GenBrkOff_StbyReady;
      O     #stat_GenBrk_Off_NoLoadR;
      O     #stat_GenBrkOff_Limit;
      O     #stat_LoadRed_TimeEx;
      O     #temp_power_avail;
      )     ;
      =     L      3.0;
      BLD   103;
      U     "true";
      SPBNB _01f;
      CALL "fc_h1_CntState16" (
           CntTyp                   := 'P',
           CntStart                 := L      3.0,
           CntValue                 := "sys_freeCnt16_100ms",
           CntOffset                := "prm_pma".p_TgenBrkOff,
           CntRun                   := #out_DO_GenBrk_Cmd_Off,
           puls_CntStart            := #stat_CntStart08,
           Cnt_started              := #stat_CntStarted08,
           mem_CntValue             := #stat_CntValue08);
_01f: NOP   0;
NETWORK
TITLE =Generator breaker OFF command via GENOP

      U     #out_DO_GenBrk_Cmd_Off;
      U     "prm_pma".p_GenBrk_OUTviaGENOP;
      O     #stat_GENOP_GenBrk_CmdOff;
      =     #out_GENOP_GenBrk_Cmd_Off;
NETWORK
TITLE =Generator breaker feedback signal after OFF command missing
//Evtl. hier auch Aus-Kommando des Gen.schutzgeräts an den Gen.schalter
//auswerten?
      U     #in_Reset;
      R     #out_Fail_FeedbOff;
      U(    ;
      U(    ;
      O     #out_GENOP_GenBrk_Cmd_Off;
      O     #out_DO_GenBrk_Cmd_Off;
      O     ;
      U     #in_EG_GB_Open;
      U     #in_EG_Set;
      )     ;
      S     #stat_FeedbOff_TimeSt;
      U(    ;
      O     #in_DI_GenBrk_FB_Off;
      O     #in_Reset;
      )     ;
      R     #stat_FeedbOff_TimeSt;
      U     #stat_FeedbOff_TimeSt;
      )     ;
      U     #stat_FeedbOff_TimeEx;
      S     #out_Fail_FeedbOff;
      NOP   0;
NETWORK
TITLE =Monitoring time for feedback signal after Off command

      U     #stat_FeedbOff_TimeSt;
      =     L      3.0;
      BLD   103;
      U     "true";
      SPBNB _020;
      CALL "fc_h1_CntState16" (
           CntTyp                   := 'D',
           CntStart                 := L      3.0,
           CntValue                 := "sys_freeCnt16_100ms",
           CntOffset                := "prm_pma".p_TgenBrkFbOff,
           CntRun                   := #stat_FeedbOff_TimeEx,
           puls_CntStart            := #stat_CntStart10,
           Cnt_started              := #stat_CntStarted10,
           mem_CntValue             := #stat_CntValue10);
_020: NOP   0;
NETWORK
TITLE =Monitoring time for plausibility control feedback sign. OFF/ON
//Normally the feedback signals "Generator breaker OFF" or "Generator breaker ON"
//are working in opposition. When they are both "0" or both "1" for a longer
//time,
//there is something wrong.
      U(    ;
      UN    #in_DI_GenBrk_FB_Off;
      UN    #in_DI_GenBrk_FB_On;
      O     ;
      U     #in_DI_GenBrk_FB_Off;
      U     #in_DI_GenBrk_FB_On;
      )     ;
      =     L      3.0;
      BLD   103;
      U     "true";
      SPBNB _021;
      CALL "fc_h1_CntState16" (
           CntTyp                   := 'D',
           CntStart                 := L      3.0,
           CntValue                 := "sys_freeCnt16_100ms",
           CntOffset                := "prm_pma".p_TgenBrkFbOffOn,
           CntRun                   := #out_Fail_FeedbOffOn,
           puls_CntStart            := #stat_CntStart11,
           Cnt_started              := #stat_CntStarted11,
           mem_CntValue             := #stat_CntValue11);
_021: NOP   0;
NETWORK
TITLE =Request for standby generator start & delayed stop command

      U(    ;
      O     #out_Fail_Ready;
      O     #out_Fail_FeedbOn;
      O     #out_Fail_SynTime;
      )     ;
      UN    #in_EG_Set;
      U     #temp_Auto;
      =     #out_StandbyStart;
      =     #out_DelayStop;
NETWORK
TITLE =Undelayed stop command

      U     #temp_GenBrkOff_StbyReady;
      =     #out_UndelayStop;
NETWORK
TITLE =

NETWORK
TITLE =Blocking of generator set by fault
//Blocking of generator set by fault only, if the failure also causes an
//undelayed
//stop. The reset of this blocking is possible only in standstill. In case of a
//delayed stop the the blocking command is given together with the stop command
//to
//the diesel engine/shaft generator.
      O     #out_UndelayStop;
      O     "false";
      =     #out_Blocking;
NETWORK
TITLE =Forced change over "Automatic" to "Semi automatic" mode
//The blocking of the generator set always causes a change over from "Automatic"
//to "Semi automatic" mode. There may be some additional conditions, which cause
//a
//changeover to "Semi automatic" mode, but no blocking.
//
//Spezielle Änderung für Notgenerator: Fehler "Generatorschalter einschaltbereit
//fehlt" wird nicht ausgewertet.
      O     #out_Blocking;
      O     #out_Fail_Ready;
      O     #out_Fail_FeedbOff;
      O     #out_Fail_FeedbOn;
      O     #out_Fail_FeedbOffOn;
      O     #stat_Fail_GenBrk_TripExt;
      O     #stat_Fail_GenBrk_TripNoR;
      O     #out_Fail_SynTime;
      =     #out_ChOver_Semi;
NETWORK
TITLE =Time delay generator breaker Off
//This "ON delay" with gen. breaker not On
      UN    #in_DI_GenBrk_FB_On;
      =     L      3.0;
      BLD   103;
      U     "true";
      SPBNB _022;
      CALL "fc_h1_CntState16" (
           CntTyp                   := 'D',
           CntStart                 := L      3.0,
           CntValue                 := "sys_freeCnt16_100ms",
           CntOffset                := 10,
           CntRun                   := #stat_GenBrk_DelayOff,
           puls_CntStart            := #stat_CntStart13,
           Cnt_started              := #stat_CntStarted13,
           mem_CntValue             := #stat_CntValue13);
_022: NOP   0;
NETWORK
TITLE =Generator breaker tripped from external
//The "Generator breaker Off" with an "ON delay" is used here as "Generator
//breaker On" with an "OFF delay".
      U     #in_Reset;
      R     #stat_Fail_GenBrk_TripExt;
      UN    #stat_GenBrk_DelayOff;
      U     #in_DI_GenBrk_ReadyClose;
      U     #in_power_avail;
      U(    ;
      U     #in_DI_GenBrk_Tripped;
      FP    #stat_PulseAux_Trip;
      )     ;
      UN    "prm_pma".p_BlockMonitBrkTrip;
      UN    #in_ext_DG_block;
      S     #stat_Fail_GenBrk_TripExt;
      NOP   0;
NETWORK
TITLE =Time delay generator breaker Off command
//This "ON delay" with NOT "Gen. breaker Off command" makes an "OFF delay" for
//"Gen. breaker Off command"
      UN    #out_DO_GenBrk_Cmd_Off;
      UN    #out_GENOP_GenBrk_Cmd_Off;
      UN    #in_PB_GenBrk_Open_Man;
      =     L      3.0;
      BLD   103;
      U     "true";
      SPBNB _023;
      CALL "fc_h1_CntState16" (
           CntTyp                   := 'D',
           CntStart                 := L      3.0,
           CntValue                 := "sys_freeCnt16_100ms",
           CntOffset                := 100,
           CntRun                   := #temp_GenBrkOffCmd_Delay,
           puls_CntStart            := #stat_CntStart14,
           Cnt_started              := #stat_CntStarted14,
           mem_CntValue             := #stat_CntValue14);
_023: NOP   0;
NETWORK
TITLE =Generator breaker tripped
//There are two conditions, which can create this failure indication:
//1. An external trip signal
//2. The feedback signal "Gen. On" has disapperared without any Off given from
//the plc S7, the GENOP71 or the Manual Off pushbutton. (Then no reason for the
//trip can be detected.)
//
//The "Generator breaker Off" with an "ON delay" is used here as "Generator
//breaker On" with an "OFF delay".
      O(    ;
      U     #in_Reset;
      R     #stat_Fail_GenBrk_TripNoR;
      UN    #in_DI_GenBrk_FB_On;
      U     #in_DI_GenBrk_FB_Off;
      FP    #stat_PulseAux_GenBrk_Off;
      U     #temp_GenBrkOffCmd_Delay;
      UN    #in_ext_DG_block;
      S     #stat_Fail_GenBrk_TripNoR;
      U     #stat_Fail_GenBrk_TripNoR;
      )     ;
      O     #stat_Fail_GenBrk_TripExt;
      =     #out_Fail_BrkTrip;
NETWORK
TITLE =Generator breaker general failure
//Spezielle Änderung für Notgenerator: Fehler "Generatorschalter einschaltbereit
//fehlt" wird nicht ausgewertet.
      O     #out_Fail_Ready;
      O     #out_Fail_FeedbOff;
      O     #out_Fail_FeedbOn;
      O     #out_Fail_FeedbOffOn;
      O     #stat_Fail_GenBrk_TripExt;
      O     #stat_Fail_GenBrk_TripNoR;
      O     #out_Fail_SynTime;
      =     #stat_Fail_GenBrk;
      =     #out_Fail_GenFailure;
NETWORK
TITLE =Indication no. 44: "Synchronizing"

      U     #out_GENOP_SynchRelease;
      =     L      3.0;
      U     L      3.0;
      BLD   102;
      =     #temp_Indication_44;
      U     L      3.0;
      SPBNB _024;
      L     44;
      T     #out_Operat_Status;
_024: NOP   0;
NETWORK
TITLE =Indication no. 45: "Simultaneous lock"

      U     #out_SimLock_Request;
      UN    #in_SimLock_Release;
      =     L      3.0;
      U     L      3.0;
      BLD   102;
      =     #temp_Indication_45;
      U     L      3.0;
      SPBNB _025;
      L     45;
      T     #out_Operat_Status;
_025: NOP   0;
NETWORK
TITLE =Indication no. 30: "_______" (No indication)
//If there is no indication coming from this FB, "30" is delivered.
      UN    #temp_Indication_44;
      UN    #temp_Indication_45;
      SPBNB _026;
      L     30;
      T     #out_Operat_Status;
_026: NOP   0;
END_FUNCTION_BLOCK



DATA_BLOCK "clsopnBrk"
TITLE =
VERSION : 0.0

"fb_57_clseopnBrk"
BEGIN
   in_DGLoad_off := FALSE;
   in_Nmb_Gen_LoadSh := 0;
   in_act_mode := B#16#0;
   in_EG_Set := FALSE;
   in_Blackout := FALSE;
   in_SimLock_Blocked := FALSE;
   in_SimLock_Fault := FALSE;
   in_SimLock_Release := FALSE;
   in_DGWG_run := FALSE;
   in_DGWG_Stop := FALSE;
   in_GenBrkOff_LoadRed := FALSE;
   in_DGWG_GenBrk_Cmd_Off := FALSE;
   in_DGWG_GenBrk_Cmd_Trip := FALSE;
   in_ChOver_Blackout := FALSE;
   in_Standby_ReadyConn := FALSE;
   in_ShoreConn_Off := FALSE;
   in_DI_GenBrk_ReadyClose := FALSE;
   in_DI_GenBrk_Tripped := FALSE;
   in_DI_GenBrk_PosNorm := FALSE;
   in_DI_GenBrk_PosTest := FALSE;
   in_DI_GenBrk_FB_On := FALSE;
   in_DI_GenBrk_FB_Off := FALSE;
   in_GENOP_SynCmd_On := FALSE;
   in_GenBrk_Ext_Release := FALSE;
   in_ext_DG_block := FALSE;
   in_EG_GB_Close := FALSE;
   in_EG_Cmd_Synchr_On := FALSE;
   in_EG_GB_Open := FALSE;
   in_PB_GenBrk_Close := FALSE;
   in_PB_GenBrk_Open := FALSE;
   in_PB_GenBrk_Open_Man := FALSE;
   in_reset_synchron := FALSE;
   in_Reset := FALSE;
   in_power_avail := FALSE;
   out_Operat_Status := 0;
   out_StandbyStart := FALSE;
   out_SimLock_Request := FALSE;
   out_DO_GenBrk_Cmd_Off := FALSE;
   out_GENOP_GenBrk_Cmd_On := FALSE;
   out_GENOP_GenBrk_Cmd_Off := FALSE;
   out_GENOP_SynchRelease := FALSE;
   out_GenBrk_Ready := FALSE;
   out_GenBrk_Ready_Standby := FALSE;
   out_GenBrk_Ready_Close := FALSE;
   out_Brk_Closed_Plausib := FALSE;
   out_UndelayStop := FALSE;
   out_DelayStop := FALSE;
   out_LoadReduction := FALSE;
   out_Blocking := FALSE;
   out_ChOver_Semi := FALSE;
   out_Fail_Ready := FALSE;
   out_Fail_FeedbOn := FALSE;
   out_Fail_FeedbOff := FALSE;
   out_Fail_FeedbOffOn := FALSE;
   out_Fail_BrkTrip := FALSE;
   out_Fail_SynTime := FALSE;
   out_Fail_GenFailure := FALSE;
   out_Fail_ShoreC_GenBrk := FALSE;
   out_Fail_ChgViaBlack := FALSE;
   stat_CntValue01 := 0;
   stat_CntValue02 := 0;
   stat_CntValue03 := 0;
   stat_CntValue04 := 0;
   stat_CntValue05 := 0;
   stat_CntValue06 := 0;
   stat_CntValue07 := 0;
   stat_CntValue08 := 0;
   stat_CntValue09 := 0;
   stat_CntValue10 := 0;
   stat_CntValue11 := 0;
   stat_CntValue12 := 0;
   stat_CntValue13 := 0;
   stat_CntValue14 := 0;
   stat_CntStart01 := FALSE;
   stat_CntStarted01 := FALSE;
   stat_CntStart02 := FALSE;
   stat_CntStarted02 := FALSE;
   stat_CntStart03 := FALSE;
   stat_CntStarted03 := FALSE;
   stat_CntStart04 := FALSE;
   stat_CntStarted04 := FALSE;
   stat_CntStart05 := FALSE;
   stat_CntStarted05 := FALSE;
   stat_CntStart06 := FALSE;
   stat_CntStarted06 := FALSE;
   stat_CntStart07 := FALSE;
   stat_CntStarted07 := FALSE;
   stat_CntStart08 := FALSE;
   stat_CntStarted08 := FALSE;
   stat_CntStart09 := FALSE;
   stat_CntStarted09 := FALSE;
   stat_CntStart10 := FALSE;
   stat_CntStarted10 := FALSE;
   stat_CntStart11 := FALSE;
   stat_CntStarted11 := FALSE;
   stat_CntStart12 := FALSE;
   stat_CntStarted12 := FALSE;
   stat_CntStart13 := FALSE;
   stat_CntStarted13 := FALSE;
   stat_CntStart14 := FALSE;
   stat_CntStarted14 := FALSE;
   stat_BrkReady_TimeEx := FALSE;
   stat_BrkClose_Semi := FALSE;
   stat_BrkOn_Sim := FALSE;
   stat_SynchOn_Pulse := FALSE;
   stat_SynchOn_EG_PAux := FALSE;
   stat_SynchOn := FALSE;
   stat_Synch_TimeEx := FALSE;
   stat_GenBrk_Off_NoLoadR := FALSE;
   stat_GenBrk_Off_LoadRed := FALSE;
   stat_LoadRed_TimeEx := FALSE;
   stat_GenBrkOff_Limit := FALSE;
   stat_GenBrkOff_StbyReady := FALSE;
   stat_FeedbOn_TimeSt := FALSE;
   stat_FeedbOn_TimeEx := FALSE;
   stat_FeedbOff_TimeSt := FALSE;
   stat_FeedbOff_TimeEx := FALSE;
   stat_GenBrk_DelayOff := FALSE;
   stat_PulseAux_Trip := FALSE;
   stat_Fail_GenBrk := FALSE;
   stat_Fail_ShoreC := FALSE;
   stat_synchron := FALSE;
   stat_Fail_GenBrk_TripExt := FALSE;
   stat_PulseAux_GenBrk_Off := FALSE;
   stat_Fail_GenBrk_TripNoR := FALSE;
   stat_GENOP_GenBrk_CmdOff := FALSE;
   stat_power_avail := FALSE;
END_DATA_BLOCK



FUNCTION "int_norm100INT" : VOID
TITLE =Scaling of a integer value --> 100.00% (integer format)
AUTHOR : Bauch
FAMILY : PMA71
NAME : Norm
VERSION : 1.0


VAR_INPUT
  in_Value : INT ;	//Input value (as Integer)
  in_Norm : INT ;	//Value for scaling (100.00%)
END_VAR
VAR_OUTPUT
  out_Value : INT ;	//Output value (as Integer)
END_VAR
BEGIN
NETWORK
TITLE =

      L     #in_Value;
      ITD   ;
      L     10000;
      *D    ;
      L     #in_Norm;
      ITD   ;
      /D    ;
      T     #out_Value;
END_FUNCTION



FUNCTION "fc_h20_NoParticip" : VOID
TITLE =Number of a signal of all participants
//
//                                                                             !
//The function list a signal over all defined participants
AUTHOR : Kahle
FAMILY : PMA71
NAME : fdbHandl
VERSION : 1.1


VAR_INPUT
  IN_bytebit : POINTER ;	//relative byte.bit address
  IN_release : WORD ;	//release source (bit0 =1:release 1.gen., ..bit12 =1:release 13.gen.
END_VAR
VAR_OUTPUT
  OUT_Signal_No : INT ;	//Number of signals
  OUT_GenSetOnbus : WORD ;
END_VAR
VAR_TEMP
  source : INT ;	//last source address
  cnt_coll : BYTE ;	//loop counter 'collected signals'
  Signal_No : BYTE ;	//temporary memory numbers of signal over all participants
  genSet_onbus : WORD ;	//generator sets on busbar (breaker close)
END_VAR
BEGIN
NETWORK
TITLE =intial. internal signals
//
//
      L     0;
      T     #genSet_onbus;
      L     122;
      T     #source; //last generator DB
      L     30;
      L     P##IN_bytebit;
      LAR1  ;
      L     D [AR1,P#2.0];
      LAR1  ; //source byte address
      L     0;
      T     #Signal_No;

NETWORK
TITLE =collect the signals from the generators

      L     14; //start =last source
lpco: T     #cnt_coll;
      L     #IN_release;
      SRW   ;
      SPZ   nxco; //if release gen(#cnt_coll) =false then ..next generator

//source =own station
      L     "prm_pma".p_station;
      +     -4;
      L     #cnt_coll;
      ==I   ;
      SPB   nxco; //if source station =own station then ...next generator

//list the signal over all participants
      AUF   DB [#source];
      UN    DBX [AR1,P#0.0];
      SPB   nxco; //signal (byte.bit) false ...next participant

      L     #Signal_No;
      +     1;
      T     #Signal_No; //add up

//generator sets on busbar
      L     #cnt_coll;
      L     DW#16#80000000;
      RLD   ;
      L     #genSet_onbus;
      OW    ;
      T     #genSet_onbus;

//next generator
nxco: L     #source;
      +     -1;
      T     #source; //next step ->next source
      L     #cnt_coll;
      LOOP  lpco;

//output
      L     #Signal_No;
      T     #OUT_Signal_No;
      L     #genSet_onbus;
      T     #OUT_GenSetOnbus;
END_FUNCTION




